VERSION 5.8 ;
BUSBITCHARS "[]" ;
DIVIDERCHAR "/" ;
UNITS
    DATABASE MICRONS 1000 ;
END UNITS

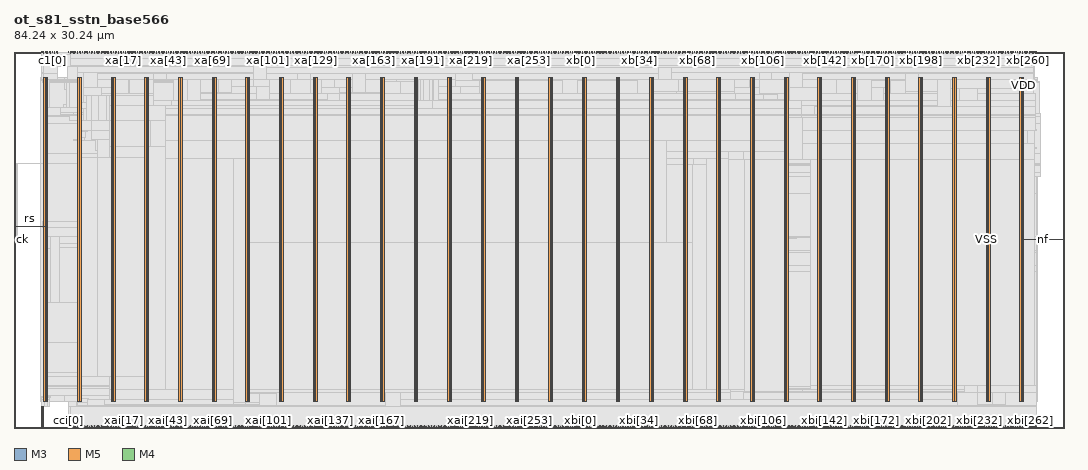
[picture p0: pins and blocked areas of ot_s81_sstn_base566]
MACRO ot_s81_sstn_base566
  FOREIGN ot_s81_sstn_base566 0 0 ;
  CLASS BLOCK ;
  SIZE 84.24 BY 30.24 ;
  PIN c0[0]
    DIRECTION INPUT ;
    USE SIGNAL ;
    PORT
      LAYER M3 ;
        RECT  2.808 30.096 2.826 30.24 ;
    END
  END c0[0]
  PIN c0[1]
    DIRECTION INPUT ;
    USE SIGNAL ;
    PORT
      LAYER M5 ;
        RECT  2.928 30.048 2.952 30.24 ;
    END
  END c0[1]
  PIN c1[0]
    DIRECTION INPUT ;
    USE SIGNAL ;
    PORT
      LAYER M3 ;
        RECT  3.096 30.096 3.114 30.24 ;
    END
  END c1[0]
  PIN c1[1]
    DIRECTION INPUT ;
    USE SIGNAL ;
    PORT
      LAYER M5 ;
        RECT  3.216 30.048 3.24 30.24 ;
    END
  END c1[1]
  PIN cc[0]
    DIRECTION OUTPUT ;
    USE SIGNAL ;
    PORT
      LAYER M3 ;
        RECT  4.392 30.096 4.41 30.24 ;
    END
  END cc[0]
  PIN cc[10]
    DIRECTION OUTPUT ;
    USE SIGNAL ;
    PORT
      LAYER M3 ;
        RECT  5.76 30.096 5.778 30.24 ;
    END
  END cc[10]
  PIN cc[11]
    DIRECTION OUTPUT ;
    USE SIGNAL ;
    PORT
      LAYER M5 ;
        RECT  5.904 30.048 5.928 30.24 ;
    END
  END cc[11]
  PIN cc[12]
    DIRECTION OUTPUT ;
    USE SIGNAL ;
    PORT
      LAYER M3 ;
        RECT  6.048 30.096 6.066 30.24 ;
    END
  END cc[12]
  PIN cc[13]
    DIRECTION OUTPUT ;
    USE SIGNAL ;
    PORT
      LAYER M5 ;
        RECT  6.192 30.048 6.216 30.24 ;
    END
  END cc[13]
  PIN cc[14]
    DIRECTION OUTPUT ;
    USE SIGNAL ;
    PORT
      LAYER M3 ;
        RECT  6.3 30.096 6.318 30.24 ;
    END
  END cc[14]
  PIN cc[1]
    DIRECTION OUTPUT ;
    USE SIGNAL ;
    PORT
      LAYER M5 ;
        RECT  4.512 30.048 4.536 30.24 ;
    END
  END cc[1]
  PIN cc[2]
    DIRECTION OUTPUT ;
    USE SIGNAL ;
    PORT
      LAYER M3 ;
        RECT  4.644 30.096 4.662 30.24 ;
    END
    PORT
      LAYER M3 ;
        RECT  4.608 30.108 4.734 30.173 ;
    END
  END cc[2]
  PIN cc[3]
    DIRECTION OUTPUT ;
    USE SIGNAL ;
    PORT
      LAYER M5 ;
        RECT  4.8 30.048 4.824 30.24 ;
    END
  END cc[3]
  PIN cc[4]
    DIRECTION OUTPUT ;
    USE SIGNAL ;
    PORT
      LAYER M3 ;
        RECT  4.932 30.096 4.95 30.24 ;
    END
  END cc[4]
  PIN cc[5]
    DIRECTION OUTPUT ;
    USE SIGNAL ;
    PORT
      LAYER M5 ;
        RECT  5.088 30.048 5.112 30.24 ;
    END
  END cc[5]
  PIN cc[6]
    DIRECTION OUTPUT ;
    USE SIGNAL ;
    PORT
      LAYER M3 ;
        RECT  5.22 30.096 5.238 30.24 ;
    END
  END cc[6]
  PIN cc[7]
    DIRECTION OUTPUT ;
    USE SIGNAL ;
    PORT
      LAYER M5 ;
        RECT  5.328 30.048 5.352 30.24 ;
    END
  END cc[7]
  PIN cc[8]
    DIRECTION OUTPUT ;
    USE SIGNAL ;
    PORT
      LAYER M3 ;
        RECT  5.472 30.096 5.49 30.24 ;
    END
  END cc[8]
  PIN cc[9]
    DIRECTION OUTPUT ;
    USE SIGNAL ;
    PORT
      LAYER M5 ;
        RECT  5.616 30.048 5.64 30.24 ;
    END
  END cc[9]
  PIN cci[0]
    DIRECTION INPUT ;
    USE SIGNAL ;
    PORT
      LAYER M3 ;
        RECT  4.392 0 4.41 0.144 ;
    END
  END cci[0]
  PIN cci[10]
    DIRECTION INPUT ;
    USE SIGNAL ;
    PORT
      LAYER M3 ;
        RECT  5.76 0 5.778 0.144 ;
    END
  END cci[10]
  PIN cci[11]
    DIRECTION INPUT ;
    USE SIGNAL ;
    PORT
      LAYER M5 ;
        RECT  5.904 0 5.928 0.192 ;
    END
  END cci[11]
  PIN cci[12]
    DIRECTION INPUT ;
    USE SIGNAL ;
    PORT
      LAYER M3 ;
        RECT  6.048 0 6.066 0.144 ;
    END
  END cci[12]
  PIN cci[13]
    DIRECTION INPUT ;
    USE SIGNAL ;
    PORT
      LAYER M5 ;
        RECT  6.192 0 6.216 0.192 ;
    END
  END cci[13]
  PIN cci[14]
    DIRECTION INPUT ;
    USE SIGNAL ;
    PORT
      LAYER M3 ;
        RECT  6.3 0 6.318 0.144 ;
    END
  END cci[14]
  PIN cci[1]
    DIRECTION INPUT ;
    USE SIGNAL ;
    PORT
      LAYER M5 ;
        RECT  4.512 0 4.536 0.192 ;
    END
  END cci[1]
  PIN cci[2]
    DIRECTION INPUT ;
    USE SIGNAL ;
    PORT
      LAYER M3 ;
        RECT  4.644 0 4.662 0.144 ;
    END
  END cci[2]
  PIN cci[3]
    DIRECTION INPUT ;
    USE SIGNAL ;
    PORT
      LAYER M5 ;
        RECT  4.8 0 4.824 0.192 ;
    END
  END cci[3]
  PIN cci[4]
    DIRECTION INPUT ;
    USE SIGNAL ;
    PORT
      LAYER M3 ;
        RECT  4.932 0 4.95 0.144 ;
    END
  END cci[4]
  PIN cci[5]
    DIRECTION INPUT ;
    USE SIGNAL ;
    PORT
      LAYER M5 ;
        RECT  5.088 0 5.112 0.192 ;
    END
  END cci[5]
  PIN cci[6]
    DIRECTION INPUT ;
    USE SIGNAL ;
    PORT
      LAYER M3 ;
        RECT  5.22 0 5.238 0.144 ;
    END
  END cci[6]
  PIN cci[7]
    DIRECTION INPUT ;
    USE SIGNAL ;
    PORT
      LAYER M5 ;
        RECT  5.328 0 5.352 0.192 ;
    END
  END cci[7]
  PIN cci[8]
    DIRECTION INPUT ;
    USE SIGNAL ;
    PORT
      LAYER M3 ;
        RECT  5.472 0 5.49 0.144 ;
    END
  END cci[8]
  PIN cci[9]
    DIRECTION INPUT ;
    USE SIGNAL ;
    PORT
      LAYER M5 ;
        RECT  5.616 0 5.64 0.192 ;
    END
  END cci[9]
  PIN ck
    DIRECTION INPUT ;
    USE SIGNAL ;
    PORT
      LAYER M4 ;
        RECT  0 15.12 0.192 15.144 ;
    END
    PORT
      LAYER M4 ;
        RECT  0.156 15.12 0.275 15.144 ;
    END
  END ck
  PIN e0[0]
    DIRECTION INPUT ;
    USE SIGNAL ;
    PORT
      LAYER M3 ;
        RECT  2.232 30.096 2.25 30.24 ;
    END
  END e0[0]
  PIN e0[1]
    DIRECTION INPUT ;
    USE SIGNAL ;
    PORT
      LAYER M5 ;
        RECT  2.352 30.048 2.376 30.24 ;
    END
  END e0[1]
  PIN e1[0]
    DIRECTION INPUT ;
    USE SIGNAL ;
    PORT
      LAYER M3 ;
        RECT  2.52 30.096 2.538 30.24 ;
    END
  END e1[0]
  PIN e1[1]
    DIRECTION INPUT ;
    USE SIGNAL ;
    PORT
      LAYER M5 ;
        RECT  2.64 30.048 2.664 30.24 ;
    END
  END e1[1]
  PIN nf
    DIRECTION INPUT ;
    USE SIGNAL ;
    PORT
      LAYER M4 ;
        RECT  84.048 15.12 84.24 15.144 ;
    END
    PORT
      LAYER M4 ;
        RECT  81.004 15.12 84.06 15.144 ;
    END
  END nf
  PIN rs
    DIRECTION INPUT ;
    USE SIGNAL ;
    PORT
      LAYER M4 ;
        RECT  0 16.128 0.192 16.152 ;
    END
    PORT
      LAYER M4 ;
        RECT  0.156 16.128 2.408 16.152 ;
    END
  END rs
  PIN si[0]
    DIRECTION INPUT ;
    USE SIGNAL ;
    PORT
      LAYER M3 ;
        RECT  3.384 30.096 3.402 30.24 ;
    END
  END si[0]
  PIN si[1]
    DIRECTION INPUT ;
    USE SIGNAL ;
    PORT
      LAYER M5 ;
        RECT  3.504 30.048 3.528 30.24 ;
    END
  END si[1]
  PIN so[0]
    DIRECTION OUTPUT ;
    USE SIGNAL ;
    PORT
      LAYER M3 ;
        RECT  2.232 0 2.25 0.144 ;
    END
    PORT
      LAYER M3 ;
        RECT  2.232 0.108 2.25 1.723 ;
    END
  END so[0]
  PIN so[1]
    DIRECTION OUTPUT ;
    USE SIGNAL ;
    PORT
      LAYER M5 ;
        RECT  2.352 0 2.376 0.192 ;
    END
    PORT
      LAYER M5 ;
        RECT  2.352 0.144 2.376 1.763 ;
    END
  END so[1]
  PIN xa[0]
    DIRECTION OUTPUT ;
    USE SIGNAL ;
    PORT
      LAYER M5 ;
        RECT  6.432 30.048 6.456 30.24 ;
    END
  END xa[0]
  PIN xa[100]
    DIRECTION OUTPUT ;
    USE SIGNAL ;
    PORT
      LAYER M5 ;
        RECT  20.256 30.048 20.28 30.24 ;
    END
  END xa[100]
  PIN xa[101]
    DIRECTION OUTPUT ;
    USE SIGNAL ;
    PORT
      LAYER M3 ;
        RECT  20.376 30.096 20.394 30.24 ;
    END
  END xa[101]
  PIN xa[102]
    DIRECTION OUTPUT ;
    USE SIGNAL ;
    PORT
      LAYER M5 ;
        RECT  20.496 30.048 20.52 30.24 ;
    END
  END xa[102]
  PIN xa[103]
    DIRECTION OUTPUT ;
    USE SIGNAL ;
    PORT
      LAYER M3 ;
        RECT  20.664 30.096 20.682 30.24 ;
    END
  END xa[103]
  PIN xa[104]
    DIRECTION OUTPUT ;
    USE SIGNAL ;
    PORT
      LAYER M5 ;
        RECT  20.784 30.048 20.808 30.24 ;
    END
  END xa[104]
  PIN xa[105]
    DIRECTION OUTPUT ;
    USE SIGNAL ;
    PORT
      LAYER M3 ;
        RECT  20.916 30.096 20.934 30.24 ;
    END
  END xa[105]
  PIN xa[106]
    DIRECTION OUTPUT ;
    USE SIGNAL ;
    PORT
      LAYER M5 ;
        RECT  21.072 30.048 21.096 30.24 ;
    END
  END xa[106]
  PIN xa[107]
    DIRECTION OUTPUT ;
    USE SIGNAL ;
    PORT
      LAYER M3 ;
        RECT  21.204 30.096 21.222 30.24 ;
    END
  END xa[107]
  PIN xa[108]
    DIRECTION OUTPUT ;
    USE SIGNAL ;
    PORT
      LAYER M5 ;
        RECT  21.312 30.048 21.336 30.24 ;
    END
  END xa[108]
  PIN xa[109]
    DIRECTION OUTPUT ;
    USE SIGNAL ;
    PORT
      LAYER M3 ;
        RECT  21.492 30.096 21.51 30.24 ;
    END
  END xa[109]
  PIN xa[10]
    DIRECTION OUTPUT ;
    USE SIGNAL ;
    PORT
      LAYER M5 ;
        RECT  7.824 30.048 7.848 30.24 ;
    END
  END xa[10]
  PIN xa[110]
    DIRECTION OUTPUT ;
    USE SIGNAL ;
    PORT
      LAYER M5 ;
        RECT  21.6 30.048 21.624 30.24 ;
    END
  END xa[110]
  PIN xa[111]
    DIRECTION OUTPUT ;
    USE SIGNAL ;
    PORT
      LAYER M3 ;
        RECT  21.744 30.096 21.762 30.24 ;
    END
  END xa[111]
  PIN xa[112]
    DIRECTION OUTPUT ;
    USE SIGNAL ;
    PORT
      LAYER M5 ;
        RECT  21.888 30.048 21.912 30.24 ;
    END
  END xa[112]
  PIN xa[113]
    DIRECTION OUTPUT ;
    USE SIGNAL ;
    PORT
      LAYER M3 ;
        RECT  22.032 30.096 22.05 30.24 ;
    END
  END xa[113]
  PIN xa[114]
    DIRECTION OUTPUT ;
    USE SIGNAL ;
    PORT
      LAYER M5 ;
        RECT  22.176 30.048 22.2 30.24 ;
    END
  END xa[114]
  PIN xa[115]
    DIRECTION OUTPUT ;
    USE SIGNAL ;
    PORT
      LAYER M3 ;
        RECT  22.32 30.096 22.338 30.24 ;
    END
  END xa[115]
  PIN xa[116]
    DIRECTION OUTPUT ;
    USE SIGNAL ;
    PORT
      LAYER M5 ;
        RECT  22.416 30.048 22.44 30.24 ;
    END
  END xa[116]
  PIN xa[117]
    DIRECTION OUTPUT ;
    USE SIGNAL ;
    PORT
      LAYER M3 ;
        RECT  22.572 30.096 22.59 30.24 ;
    END
  END xa[117]
  PIN xa[118]
    DIRECTION OUTPUT ;
    USE SIGNAL ;
    PORT
      LAYER M5 ;
        RECT  22.704 30.048 22.728 30.24 ;
    END
  END xa[118]
  PIN xa[119]
    DIRECTION OUTPUT ;
    USE SIGNAL ;
    PORT
      LAYER M3 ;
        RECT  22.86 30.096 22.878 30.24 ;
    END
  END xa[119]
  PIN xa[11]
    DIRECTION OUTPUT ;
    USE SIGNAL ;
    PORT
      LAYER M3 ;
        RECT  7.956 30.096 7.974 30.24 ;
    END
  END xa[11]
  PIN xa[120]
    DIRECTION OUTPUT ;
    USE SIGNAL ;
    PORT
      LAYER M5 ;
        RECT  22.992 30.048 23.016 30.24 ;
    END
  END xa[120]
  PIN xa[121]
    DIRECTION OUTPUT ;
    USE SIGNAL ;
    PORT
      LAYER M3 ;
        RECT  23.148 30.096 23.166 30.24 ;
    END
  END xa[121]
  PIN xa[122]
    DIRECTION OUTPUT ;
    USE SIGNAL ;
    PORT
      LAYER M5 ;
        RECT  23.28 30.048 23.304 30.24 ;
    END
  END xa[122]
  PIN xa[123]
    DIRECTION OUTPUT ;
    USE SIGNAL ;
    PORT
      LAYER M3 ;
        RECT  23.4 30.096 23.418 30.24 ;
    END
  END xa[123]
  PIN xa[124]
    DIRECTION OUTPUT ;
    USE SIGNAL ;
    PORT
      LAYER M5 ;
        RECT  23.52 30.048 23.544 30.24 ;
    END
  END xa[124]
  PIN xa[125]
    DIRECTION OUTPUT ;
    USE SIGNAL ;
    PORT
      LAYER M3 ;
        RECT  23.688 30.096 23.706 30.24 ;
    END
  END xa[125]
  PIN xa[126]
    DIRECTION OUTPUT ;
    USE SIGNAL ;
    PORT
      LAYER M5 ;
        RECT  23.808 30.048 23.832 30.24 ;
    END
  END xa[126]
  PIN xa[127]
    DIRECTION OUTPUT ;
    USE SIGNAL ;
    PORT
      LAYER M3 ;
        RECT  23.94 30.096 23.958 30.24 ;
    END
  END xa[127]
  PIN xa[128]
    DIRECTION OUTPUT ;
    USE SIGNAL ;
    PORT
      LAYER M5 ;
        RECT  24.096 30.048 24.12 30.24 ;
    END
  END xa[128]
  PIN xa[129]
    DIRECTION OUTPUT ;
    USE SIGNAL ;
    PORT
      LAYER M3 ;
        RECT  24.228 30.096 24.246 30.24 ;
    END
  END xa[129]
  PIN xa[12]
    DIRECTION OUTPUT ;
    USE SIGNAL ;
    PORT
      LAYER M5 ;
        RECT  8.112 30.048 8.136 30.24 ;
    END
  END xa[12]
  PIN xa[130]
    DIRECTION OUTPUT ;
    USE SIGNAL ;
    PORT
      LAYER M5 ;
        RECT  24.384 30.048 24.408 30.24 ;
    END
  END xa[130]
  PIN xa[131]
    DIRECTION OUTPUT ;
    USE SIGNAL ;
    PORT
      LAYER M3 ;
        RECT  24.516 30.096 24.534 30.24 ;
    END
  END xa[131]
  PIN xa[132]
    DIRECTION OUTPUT ;
    USE SIGNAL ;
    PORT
      LAYER M5 ;
        RECT  24.624 30.048 24.648 30.24 ;
    END
  END xa[132]
  PIN xa[133]
    DIRECTION OUTPUT ;
    USE SIGNAL ;
    PORT
      LAYER M3 ;
        RECT  24.768 30.096 24.786 30.24 ;
    END
  END xa[133]
  PIN xa[134]
    DIRECTION OUTPUT ;
    USE SIGNAL ;
    PORT
      LAYER M5 ;
        RECT  24.912 30.048 24.936 30.24 ;
    END
  END xa[134]
  PIN xa[135]
    DIRECTION OUTPUT ;
    USE SIGNAL ;
    PORT
      LAYER M3 ;
        RECT  25.056 30.096 25.074 30.24 ;
    END
  END xa[135]
  PIN xa[136]
    DIRECTION OUTPUT ;
    USE SIGNAL ;
    PORT
      LAYER M5 ;
        RECT  25.2 30.048 25.224 30.24 ;
    END
  END xa[136]
  PIN xa[137]
    DIRECTION OUTPUT ;
    USE SIGNAL ;
    PORT
      LAYER M3 ;
        RECT  25.344 30.096 25.362 30.24 ;
    END
  END xa[137]
  PIN xa[138]
    DIRECTION OUTPUT ;
    USE SIGNAL ;
    PORT
      LAYER M5 ;
        RECT  25.488 30.048 25.512 30.24 ;
    END
  END xa[138]
  PIN xa[139]
    DIRECTION OUTPUT ;
    USE SIGNAL ;
    PORT
      LAYER M3 ;
        RECT  25.596 30.096 25.614 30.24 ;
    END
  END xa[139]
  PIN xa[13]
    DIRECTION OUTPUT ;
    USE SIGNAL ;
    PORT
      LAYER M3 ;
        RECT  8.244 30.096 8.262 30.24 ;
    END
  END xa[13]
  PIN xa[140]
    DIRECTION OUTPUT ;
    USE SIGNAL ;
    PORT
      LAYER M5 ;
        RECT  25.728 30.048 25.752 30.24 ;
    END
  END xa[140]
  PIN xa[141]
    DIRECTION OUTPUT ;
    USE SIGNAL ;
    PORT
      LAYER M3 ;
        RECT  25.884 30.096 25.902 30.24 ;
    END
  END xa[141]
  PIN xa[142]
    DIRECTION OUTPUT ;
    USE SIGNAL ;
    PORT
      LAYER M5 ;
        RECT  26.016 30.048 26.04 30.24 ;
    END
  END xa[142]
  PIN xa[143]
    DIRECTION OUTPUT ;
    USE SIGNAL ;
    PORT
      LAYER M3 ;
        RECT  26.172 30.096 26.19 30.24 ;
    END
  END xa[143]
  PIN xa[144]
    DIRECTION OUTPUT ;
    USE SIGNAL ;
    PORT
      LAYER M5 ;
        RECT  26.304 30.048 26.328 30.24 ;
    END
  END xa[144]
  PIN xa[145]
    DIRECTION OUTPUT ;
    USE SIGNAL ;
    PORT
      LAYER M3 ;
        RECT  26.424 30.096 26.442 30.24 ;
    END
  END xa[145]
  PIN xa[146]
    DIRECTION OUTPUT ;
    USE SIGNAL ;
    PORT
      LAYER M5 ;
        RECT  26.592 30.048 26.616 30.24 ;
    END
  END xa[146]
  PIN xa[147]
    DIRECTION OUTPUT ;
    USE SIGNAL ;
    PORT
      LAYER M3 ;
        RECT  26.712 30.096 26.73 30.24 ;
    END
  END xa[147]
  PIN xa[148]
    DIRECTION OUTPUT ;
    USE SIGNAL ;
    PORT
      LAYER M5 ;
        RECT  26.832 30.048 26.856 30.24 ;
    END
  END xa[148]
  PIN xa[149]
    DIRECTION OUTPUT ;
    USE SIGNAL ;
    PORT
      LAYER M3 ;
        RECT  27 30.096 27.018 30.24 ;
    END
  END xa[149]
  PIN xa[14]
    DIRECTION OUTPUT ;
    USE SIGNAL ;
    PORT
      LAYER M5 ;
        RECT  8.352 30.048 8.376 30.24 ;
    END
  END xa[14]
  PIN xa[150]
    DIRECTION OUTPUT ;
    USE SIGNAL ;
    PORT
      LAYER M5 ;
        RECT  27.12 30.048 27.144 30.24 ;
    END
  END xa[150]
  PIN xa[151]
    DIRECTION OUTPUT ;
    USE SIGNAL ;
    PORT
      LAYER M3 ;
        RECT  27.252 30.096 27.27 30.24 ;
    END
  END xa[151]
  PIN xa[152]
    DIRECTION OUTPUT ;
    USE SIGNAL ;
    PORT
      LAYER M5 ;
        RECT  27.408 30.048 27.432 30.24 ;
    END
  END xa[152]
  PIN xa[153]
    DIRECTION OUTPUT ;
    USE SIGNAL ;
    PORT
      LAYER M3 ;
        RECT  27.54 30.096 27.558 30.24 ;
    END
  END xa[153]
  PIN xa[154]
    DIRECTION OUTPUT ;
    USE SIGNAL ;
    PORT
      LAYER M5 ;
        RECT  27.696 30.048 27.72 30.24 ;
    END
  END xa[154]
  PIN xa[155]
    DIRECTION OUTPUT ;
    USE SIGNAL ;
    PORT
      LAYER M3 ;
        RECT  27.828 30.096 27.846 30.24 ;
    END
  END xa[155]
  PIN xa[156]
    DIRECTION OUTPUT ;
    USE SIGNAL ;
    PORT
      LAYER M5 ;
        RECT  27.936 30.048 27.96 30.24 ;
    END
  END xa[156]
  PIN xa[157]
    DIRECTION OUTPUT ;
    USE SIGNAL ;
    PORT
      LAYER M3 ;
        RECT  28.08 30.096 28.098 30.24 ;
    END
  END xa[157]
  PIN xa[158]
    DIRECTION OUTPUT ;
    USE SIGNAL ;
    PORT
      LAYER M5 ;
        RECT  28.224 30.048 28.248 30.24 ;
    END
  END xa[158]
  PIN xa[159]
    DIRECTION OUTPUT ;
    USE SIGNAL ;
    PORT
      LAYER M3 ;
        RECT  28.368 30.096 28.386 30.24 ;
    END
  END xa[159]
  PIN xa[15]
    DIRECTION OUTPUT ;
    USE SIGNAL ;
    PORT
      LAYER M3 ;
        RECT  8.532 30.096 8.55 30.24 ;
    END
  END xa[15]
  PIN xa[160]
    DIRECTION OUTPUT ;
    USE SIGNAL ;
    PORT
      LAYER M5 ;
        RECT  28.512 30.048 28.536 30.24 ;
    END
  END xa[160]
  PIN xa[161]
    DIRECTION OUTPUT ;
    USE SIGNAL ;
    PORT
      LAYER M3 ;
        RECT  28.656 30.096 28.674 30.24 ;
    END
  END xa[161]
  PIN xa[162]
    DIRECTION OUTPUT ;
    USE SIGNAL ;
    PORT
      LAYER M5 ;
        RECT  28.8 30.048 28.824 30.24 ;
    END
  END xa[162]
  PIN xa[163]
    DIRECTION OUTPUT ;
    USE SIGNAL ;
    PORT
      LAYER M3 ;
        RECT  28.908 30.096 28.926 30.24 ;
    END
  END xa[163]
  PIN xa[164]
    DIRECTION OUTPUT ;
    USE SIGNAL ;
    PORT
      LAYER M5 ;
        RECT  29.04 30.048 29.064 30.24 ;
    END
  END xa[164]
  PIN xa[165]
    DIRECTION OUTPUT ;
    USE SIGNAL ;
    PORT
      LAYER M3 ;
        RECT  29.196 30.096 29.214 30.24 ;
    END
  END xa[165]
  PIN xa[166]
    DIRECTION OUTPUT ;
    USE SIGNAL ;
    PORT
      LAYER M5 ;
        RECT  29.328 30.048 29.352 30.24 ;
    END
  END xa[166]
  PIN xa[167]
    DIRECTION OUTPUT ;
    USE SIGNAL ;
    PORT
      LAYER M3 ;
        RECT  29.484 30.096 29.502 30.24 ;
    END
  END xa[167]
  PIN xa[168]
    DIRECTION OUTPUT ;
    USE SIGNAL ;
    PORT
      LAYER M5 ;
        RECT  29.616 30.048 29.64 30.24 ;
    END
  END xa[168]
  PIN xa[169]
    DIRECTION OUTPUT ;
    USE SIGNAL ;
    PORT
      LAYER M3 ;
        RECT  29.736 30.096 29.754 30.24 ;
    END
  END xa[169]
  PIN xa[16]
    DIRECTION OUTPUT ;
    USE SIGNAL ;
    PORT
      LAYER M5 ;
        RECT  8.64 30.048 8.664 30.24 ;
    END
  END xa[16]
  PIN xa[170]
    DIRECTION OUTPUT ;
    USE SIGNAL ;
    PORT
      LAYER M5 ;
        RECT  29.904 30.048 29.928 30.24 ;
    END
  END xa[170]
  PIN xa[171]
    DIRECTION OUTPUT ;
    USE SIGNAL ;
    PORT
      LAYER M3 ;
        RECT  30.024 30.096 30.042 30.24 ;
    END
  END xa[171]
  PIN xa[172]
    DIRECTION OUTPUT ;
    USE SIGNAL ;
    PORT
      LAYER M5 ;
        RECT  30.144 30.048 30.168 30.24 ;
    END
  END xa[172]
  PIN xa[173]
    DIRECTION OUTPUT ;
    USE SIGNAL ;
    PORT
      LAYER M3 ;
        RECT  30.312 30.096 30.33 30.24 ;
    END
  END xa[173]
  PIN xa[174]
    DIRECTION OUTPUT ;
    USE SIGNAL ;
    PORT
      LAYER M5 ;
        RECT  30.432 30.048 30.456 30.24 ;
    END
  END xa[174]
  PIN xa[175]
    DIRECTION OUTPUT ;
    USE SIGNAL ;
    PORT
      LAYER M3 ;
        RECT  30.564 30.096 30.582 30.24 ;
    END
  END xa[175]
  PIN xa[176]
    DIRECTION OUTPUT ;
    USE SIGNAL ;
    PORT
      LAYER M5 ;
        RECT  30.72 30.048 30.744 30.24 ;
    END
  END xa[176]
  PIN xa[177]
    DIRECTION OUTPUT ;
    USE SIGNAL ;
    PORT
      LAYER M3 ;
        RECT  30.852 30.096 30.87 30.24 ;
    END
  END xa[177]
  PIN xa[178]
    DIRECTION OUTPUT ;
    USE SIGNAL ;
    PORT
      LAYER M5 ;
        RECT  31.008 30.048 31.032 30.24 ;
    END
  END xa[178]
  PIN xa[179]
    DIRECTION OUTPUT ;
    USE SIGNAL ;
    PORT
      LAYER M3 ;
        RECT  31.14 30.096 31.158 30.24 ;
    END
  END xa[179]
  PIN xa[17]
    DIRECTION OUTPUT ;
    USE SIGNAL ;
    PORT
      LAYER M3 ;
        RECT  8.784 30.096 8.802 30.24 ;
    END
  END xa[17]
  PIN xa[180]
    DIRECTION OUTPUT ;
    USE SIGNAL ;
    PORT
      LAYER M5 ;
        RECT  31.248 30.048 31.272 30.24 ;
    END
  END xa[180]
  PIN xa[181]
    DIRECTION OUTPUT ;
    USE SIGNAL ;
    PORT
      LAYER M3 ;
        RECT  31.392 30.096 31.41 30.24 ;
    END
  END xa[181]
  PIN xa[182]
    DIRECTION OUTPUT ;
    USE SIGNAL ;
    PORT
      LAYER M5 ;
        RECT  31.536 30.048 31.56 30.24 ;
    END
  END xa[182]
  PIN xa[183]
    DIRECTION OUTPUT ;
    USE SIGNAL ;
    PORT
      LAYER M3 ;
        RECT  31.68 30.096 31.698 30.24 ;
    END
  END xa[183]
  PIN xa[184]
    DIRECTION OUTPUT ;
    USE SIGNAL ;
    PORT
      LAYER M5 ;
        RECT  31.824 30.048 31.848 30.24 ;
    END
  END xa[184]
  PIN xa[185]
    DIRECTION OUTPUT ;
    USE SIGNAL ;
    PORT
      LAYER M3 ;
        RECT  31.968 30.096 31.986 30.24 ;
    END
  END xa[185]
  PIN xa[186]
    DIRECTION OUTPUT ;
    USE SIGNAL ;
    PORT
      LAYER M5 ;
        RECT  32.112 30.048 32.136 30.24 ;
    END
  END xa[186]
  PIN xa[187]
    DIRECTION OUTPUT ;
    USE SIGNAL ;
    PORT
      LAYER M3 ;
        RECT  32.22 30.096 32.238 30.24 ;
    END
  END xa[187]
  PIN xa[188]
    DIRECTION OUTPUT ;
    USE SIGNAL ;
    PORT
      LAYER M5 ;
        RECT  32.352 30.048 32.376 30.24 ;
    END
  END xa[188]
  PIN xa[189]
    DIRECTION OUTPUT ;
    USE SIGNAL ;
    PORT
      LAYER M3 ;
        RECT  32.508 30.096 32.526 30.24 ;
    END
  END xa[189]
  PIN xa[18]
    DIRECTION OUTPUT ;
    USE SIGNAL ;
    PORT
      LAYER M5 ;
        RECT  8.928 30.048 8.952 30.24 ;
    END
  END xa[18]
  PIN xa[190]
    DIRECTION OUTPUT ;
    USE SIGNAL ;
    PORT
      LAYER M5 ;
        RECT  32.64 30.048 32.664 30.24 ;
    END
  END xa[190]
  PIN xa[191]
    DIRECTION OUTPUT ;
    USE SIGNAL ;
    PORT
      LAYER M3 ;
        RECT  32.796 30.096 32.814 30.24 ;
    END
  END xa[191]
  PIN xa[192]
    DIRECTION OUTPUT ;
    USE SIGNAL ;
    PORT
      LAYER M5 ;
        RECT  32.928 30.048 32.952 30.24 ;
    END
  END xa[192]
  PIN xa[193]
    DIRECTION OUTPUT ;
    USE SIGNAL ;
    PORT
      LAYER M3 ;
        RECT  33.048 30.096 33.066 30.24 ;
    END
  END xa[193]
  PIN xa[194]
    DIRECTION OUTPUT ;
    USE SIGNAL ;
    PORT
      LAYER M5 ;
        RECT  33.216 30.048 33.24 30.24 ;
    END
  END xa[194]
  PIN xa[195]
    DIRECTION OUTPUT ;
    USE SIGNAL ;
    PORT
      LAYER M3 ;
        RECT  33.336 30.096 33.354 30.24 ;
    END
  END xa[195]
  PIN xa[196]
    DIRECTION OUTPUT ;
    USE SIGNAL ;
    PORT
      LAYER M5 ;
        RECT  33.456 30.048 33.48 30.24 ;
    END
  END xa[196]
  PIN xa[197]
    DIRECTION OUTPUT ;
    USE SIGNAL ;
    PORT
      LAYER M3 ;
        RECT  33.624 30.096 33.642 30.24 ;
    END
  END xa[197]
  PIN xa[198]
    DIRECTION OUTPUT ;
    USE SIGNAL ;
    PORT
      LAYER M5 ;
        RECT  33.744 30.048 33.768 30.24 ;
    END
  END xa[198]
  PIN xa[199]
    DIRECTION OUTPUT ;
    USE SIGNAL ;
    PORT
      LAYER M3 ;
        RECT  33.876 30.096 33.894 30.24 ;
    END
  END xa[199]
  PIN xa[19]
    DIRECTION OUTPUT ;
    USE SIGNAL ;
    PORT
      LAYER M3 ;
        RECT  9.072 30.096 9.09 30.24 ;
    END
  END xa[19]
  PIN xa[1]
    DIRECTION OUTPUT ;
    USE SIGNAL ;
    PORT
      LAYER M3 ;
        RECT  6.588 30.096 6.606 30.24 ;
    END
  END xa[1]
  PIN xa[200]
    DIRECTION OUTPUT ;
    USE SIGNAL ;
    PORT
      LAYER M5 ;
        RECT  34.032 30.048 34.056 30.24 ;
    END
  END xa[200]
  PIN xa[201]
    DIRECTION OUTPUT ;
    USE SIGNAL ;
    PORT
      LAYER M3 ;
        RECT  34.164 30.096 34.182 30.24 ;
    END
  END xa[201]
  PIN xa[202]
    DIRECTION OUTPUT ;
    USE SIGNAL ;
    PORT
      LAYER M5 ;
        RECT  34.272 30.048 34.296 30.24 ;
    END
  END xa[202]
  PIN xa[203]
    DIRECTION OUTPUT ;
    USE SIGNAL ;
    PORT
      LAYER M3 ;
        RECT  34.452 30.096 34.47 30.24 ;
    END
  END xa[203]
  PIN xa[204]
    DIRECTION OUTPUT ;
    USE SIGNAL ;
    PORT
      LAYER M5 ;
        RECT  34.56 30.048 34.584 30.24 ;
    END
  END xa[204]
  PIN xa[205]
    DIRECTION OUTPUT ;
    USE SIGNAL ;
    PORT
      LAYER M3 ;
        RECT  34.704 30.096 34.722 30.24 ;
    END
  END xa[205]
  PIN xa[206]
    DIRECTION OUTPUT ;
    USE SIGNAL ;
    PORT
      LAYER M5 ;
        RECT  34.848 30.048 34.872 30.24 ;
    END
  END xa[206]
  PIN xa[207]
    DIRECTION OUTPUT ;
    USE SIGNAL ;
    PORT
      LAYER M3 ;
        RECT  34.992 30.096 35.01 30.24 ;
    END
  END xa[207]
  PIN xa[208]
    DIRECTION OUTPUT ;
    USE SIGNAL ;
    PORT
      LAYER M5 ;
        RECT  35.136 30.048 35.16 30.24 ;
    END
  END xa[208]
  PIN xa[209]
    DIRECTION OUTPUT ;
    USE SIGNAL ;
    PORT
      LAYER M3 ;
        RECT  35.28 30.096 35.298 30.24 ;
    END
  END xa[209]
  PIN xa[20]
    DIRECTION OUTPUT ;
    USE SIGNAL ;
    PORT
      LAYER M5 ;
        RECT  9.216 30.048 9.24 30.24 ;
    END
  END xa[20]
  PIN xa[210]
    DIRECTION OUTPUT ;
    USE SIGNAL ;
    PORT
      LAYER M5 ;
        RECT  35.376 30.048 35.4 30.24 ;
    END
  END xa[210]
  PIN xa[211]
    DIRECTION OUTPUT ;
    USE SIGNAL ;
    PORT
      LAYER M3 ;
        RECT  35.532 30.096 35.55 30.24 ;
    END
  END xa[211]
  PIN xa[212]
    DIRECTION OUTPUT ;
    USE SIGNAL ;
    PORT
      LAYER M5 ;
        RECT  35.664 30.048 35.688 30.24 ;
    END
  END xa[212]
  PIN xa[213]
    DIRECTION OUTPUT ;
    USE SIGNAL ;
    PORT
      LAYER M3 ;
        RECT  35.82 30.096 35.838 30.24 ;
    END
  END xa[213]
  PIN xa[214]
    DIRECTION OUTPUT ;
    USE SIGNAL ;
    PORT
      LAYER M5 ;
        RECT  35.952 30.048 35.976 30.24 ;
    END
  END xa[214]
  PIN xa[215]
    DIRECTION OUTPUT ;
    USE SIGNAL ;
    PORT
      LAYER M3 ;
        RECT  36.108 30.096 36.126 30.24 ;
    END
  END xa[215]
  PIN xa[216]
    DIRECTION OUTPUT ;
    USE SIGNAL ;
    PORT
      LAYER M5 ;
        RECT  36.24 30.048 36.264 30.24 ;
    END
  END xa[216]
  PIN xa[217]
    DIRECTION OUTPUT ;
    USE SIGNAL ;
    PORT
      LAYER M3 ;
        RECT  36.36 30.096 36.378 30.24 ;
    END
  END xa[217]
  PIN xa[218]
    DIRECTION OUTPUT ;
    USE SIGNAL ;
    PORT
      LAYER M5 ;
        RECT  36.48 30.048 36.504 30.24 ;
    END
  END xa[218]
  PIN xa[219]
    DIRECTION OUTPUT ;
    USE SIGNAL ;
    PORT
      LAYER M3 ;
        RECT  36.648 30.096 36.666 30.24 ;
    END
  END xa[219]
  PIN xa[21]
    DIRECTION OUTPUT ;
    USE SIGNAL ;
    PORT
      LAYER M3 ;
        RECT  9.36 30.096 9.378 30.24 ;
    END
  END xa[21]
  PIN xa[220]
    DIRECTION OUTPUT ;
    USE SIGNAL ;
    PORT
      LAYER M5 ;
        RECT  36.768 30.048 36.792 30.24 ;
    END
  END xa[220]
  PIN xa[221]
    DIRECTION OUTPUT ;
    USE SIGNAL ;
    PORT
      LAYER M3 ;
        RECT  36.9 30.096 36.918 30.24 ;
    END
  END xa[221]
  PIN xa[222]
    DIRECTION OUTPUT ;
    USE SIGNAL ;
    PORT
      LAYER M5 ;
        RECT  37.056 30.048 37.08 30.24 ;
    END
  END xa[222]
  PIN xa[223]
    DIRECTION OUTPUT ;
    USE SIGNAL ;
    PORT
      LAYER M3 ;
        RECT  37.188 30.096 37.206 30.24 ;
    END
  END xa[223]
  PIN xa[224]
    DIRECTION OUTPUT ;
    USE SIGNAL ;
    PORT
      LAYER M5 ;
        RECT  37.344 30.048 37.368 30.24 ;
    END
  END xa[224]
  PIN xa[225]
    DIRECTION OUTPUT ;
    USE SIGNAL ;
    PORT
      LAYER M3 ;
        RECT  37.476 30.096 37.494 30.24 ;
    END
  END xa[225]
  PIN xa[226]
    DIRECTION OUTPUT ;
    USE SIGNAL ;
    PORT
      LAYER M5 ;
        RECT  37.584 30.048 37.608 30.24 ;
    END
  END xa[226]
  PIN xa[227]
    DIRECTION OUTPUT ;
    USE SIGNAL ;
    PORT
      LAYER M3 ;
        RECT  37.728 30.096 37.746 30.24 ;
    END
  END xa[227]
  PIN xa[228]
    DIRECTION OUTPUT ;
    USE SIGNAL ;
    PORT
      LAYER M5 ;
        RECT  37.872 30.048 37.896 30.24 ;
    END
  END xa[228]
  PIN xa[229]
    DIRECTION OUTPUT ;
    USE SIGNAL ;
    PORT
      LAYER M3 ;
        RECT  38.016 30.096 38.034 30.24 ;
    END
  END xa[229]
  PIN xa[22]
    DIRECTION OUTPUT ;
    USE SIGNAL ;
    PORT
      LAYER M5 ;
        RECT  9.456 30.048 9.48 30.24 ;
    END
  END xa[22]
  PIN xa[230]
    DIRECTION OUTPUT ;
    USE SIGNAL ;
    PORT
      LAYER M5 ;
        RECT  38.16 30.048 38.184 30.24 ;
    END
  END xa[230]
  PIN xa[231]
    DIRECTION OUTPUT ;
    USE SIGNAL ;
    PORT
      LAYER M3 ;
        RECT  38.304 30.096 38.322 30.24 ;
    END
  END xa[231]
  PIN xa[232]
    DIRECTION OUTPUT ;
    USE SIGNAL ;
    PORT
      LAYER M5 ;
        RECT  38.448 30.048 38.472 30.24 ;
    END
  END xa[232]
  PIN xa[233]
    DIRECTION OUTPUT ;
    USE SIGNAL ;
    PORT
      LAYER M3 ;
        RECT  38.556 30.096 38.574 30.24 ;
    END
  END xa[233]
  PIN xa[234]
    DIRECTION OUTPUT ;
    USE SIGNAL ;
    PORT
      LAYER M5 ;
        RECT  38.688 30.048 38.712 30.24 ;
    END
  END xa[234]
  PIN xa[235]
    DIRECTION OUTPUT ;
    USE SIGNAL ;
    PORT
      LAYER M3 ;
        RECT  38.844 30.096 38.862 30.24 ;
    END
  END xa[235]
  PIN xa[236]
    DIRECTION OUTPUT ;
    USE SIGNAL ;
    PORT
      LAYER M5 ;
        RECT  38.976 30.048 39 30.24 ;
    END
  END xa[236]
  PIN xa[237]
    DIRECTION OUTPUT ;
    USE SIGNAL ;
    PORT
      LAYER M3 ;
        RECT  39.132 30.096 39.15 30.24 ;
    END
  END xa[237]
  PIN xa[238]
    DIRECTION OUTPUT ;
    USE SIGNAL ;
    PORT
      LAYER M5 ;
        RECT  39.264 30.048 39.288 30.24 ;
    END
  END xa[238]
  PIN xa[239]
    DIRECTION OUTPUT ;
    USE SIGNAL ;
    PORT
      LAYER M3 ;
        RECT  39.384 30.096 39.402 30.24 ;
    END
  END xa[239]
  PIN xa[23]
    DIRECTION OUTPUT ;
    USE SIGNAL ;
    PORT
      LAYER M3 ;
        RECT  9.612 30.096 9.63 30.24 ;
    END
  END xa[23]
  PIN xa[240]
    DIRECTION OUTPUT ;
    USE SIGNAL ;
    PORT
      LAYER M5 ;
        RECT  39.552 30.048 39.576 30.24 ;
    END
  END xa[240]
  PIN xa[241]
    DIRECTION OUTPUT ;
    USE SIGNAL ;
    PORT
      LAYER M3 ;
        RECT  39.672 30.096 39.69 30.24 ;
    END
  END xa[241]
  PIN xa[242]
    DIRECTION OUTPUT ;
    USE SIGNAL ;
    PORT
      LAYER M5 ;
        RECT  39.792 30.048 39.816 30.24 ;
    END
  END xa[242]
  PIN xa[243]
    DIRECTION OUTPUT ;
    USE SIGNAL ;
    PORT
      LAYER M3 ;
        RECT  39.96 30.096 39.978 30.24 ;
    END
  END xa[243]
  PIN xa[244]
    DIRECTION OUTPUT ;
    USE SIGNAL ;
    PORT
      LAYER M5 ;
        RECT  40.08 30.048 40.104 30.24 ;
    END
  END xa[244]
  PIN xa[245]
    DIRECTION OUTPUT ;
    USE SIGNAL ;
    PORT
      LAYER M3 ;
        RECT  40.212 30.096 40.23 30.24 ;
    END
  END xa[245]
  PIN xa[246]
    DIRECTION OUTPUT ;
    USE SIGNAL ;
    PORT
      LAYER M5 ;
        RECT  40.368 30.048 40.392 30.24 ;
    END
  END xa[246]
  PIN xa[247]
    DIRECTION OUTPUT ;
    USE SIGNAL ;
    PORT
      LAYER M3 ;
        RECT  40.5 30.096 40.518 30.24 ;
    END
  END xa[247]
  PIN xa[248]
    DIRECTION OUTPUT ;
    USE SIGNAL ;
    PORT
      LAYER M5 ;
        RECT  40.656 30.048 40.68 30.24 ;
    END
  END xa[248]
  PIN xa[249]
    DIRECTION OUTPUT ;
    USE SIGNAL ;
    PORT
      LAYER M3 ;
        RECT  40.788 30.096 40.806 30.24 ;
    END
  END xa[249]
  PIN xa[24]
    DIRECTION OUTPUT ;
    USE SIGNAL ;
    PORT
      LAYER M5 ;
        RECT  9.744 30.048 9.768 30.24 ;
    END
  END xa[24]
  PIN xa[250]
    DIRECTION OUTPUT ;
    USE SIGNAL ;
    PORT
      LAYER M5 ;
        RECT  40.896 30.048 40.92 30.24 ;
    END
  END xa[250]
  PIN xa[251]
    DIRECTION OUTPUT ;
    USE SIGNAL ;
    PORT
      LAYER M3 ;
        RECT  41.04 30.096 41.058 30.24 ;
    END
  END xa[251]
  PIN xa[252]
    DIRECTION OUTPUT ;
    USE SIGNAL ;
    PORT
      LAYER M5 ;
        RECT  41.184 30.048 41.208 30.24 ;
    END
  END xa[252]
  PIN xa[253]
    DIRECTION OUTPUT ;
    USE SIGNAL ;
    PORT
      LAYER M3 ;
        RECT  41.328 30.096 41.346 30.24 ;
    END
  END xa[253]
  PIN xa[254]
    DIRECTION OUTPUT ;
    USE SIGNAL ;
    PORT
      LAYER M5 ;
        RECT  41.472 30.048 41.496 30.24 ;
    END
  END xa[254]
  PIN xa[255]
    DIRECTION OUTPUT ;
    USE SIGNAL ;
    PORT
      LAYER M3 ;
        RECT  41.616 30.096 41.634 30.24 ;
    END
  END xa[255]
  PIN xa[256]
    DIRECTION OUTPUT ;
    USE SIGNAL ;
    PORT
      LAYER M5 ;
        RECT  41.76 30.048 41.784 30.24 ;
    END
  END xa[256]
  PIN xa[257]
    DIRECTION OUTPUT ;
    USE SIGNAL ;
    PORT
      LAYER M3 ;
        RECT  41.868 30.096 41.886 30.24 ;
    END
  END xa[257]
  PIN xa[258]
    DIRECTION OUTPUT ;
    USE SIGNAL ;
    PORT
      LAYER M5 ;
        RECT  42 30.048 42.024 30.24 ;
    END
  END xa[258]
  PIN xa[259]
    DIRECTION OUTPUT ;
    USE SIGNAL ;
    PORT
      LAYER M3 ;
        RECT  42.156 30.096 42.174 30.24 ;
    END
  END xa[259]
  PIN xa[25]
    DIRECTION OUTPUT ;
    USE SIGNAL ;
    PORT
      LAYER M3 ;
        RECT  9.9 30.096 9.918 30.24 ;
    END
  END xa[25]
  PIN xa[260]
    DIRECTION OUTPUT ;
    USE SIGNAL ;
    PORT
      LAYER M5 ;
        RECT  42.288 30.048 42.312 30.24 ;
    END
  END xa[260]
  PIN xa[261]
    DIRECTION OUTPUT ;
    USE SIGNAL ;
    PORT
      LAYER M3 ;
        RECT  42.444 30.096 42.462 30.24 ;
    END
  END xa[261]
  PIN xa[262]
    DIRECTION OUTPUT ;
    USE SIGNAL ;
    PORT
      LAYER M5 ;
        RECT  42.576 30.048 42.6 30.24 ;
    END
  END xa[262]
  PIN xa[263]
    DIRECTION OUTPUT ;
    USE SIGNAL ;
    PORT
      LAYER M3 ;
        RECT  42.696 30.096 42.714 30.24 ;
    END
  END xa[263]
  PIN xa[264]
    DIRECTION OUTPUT ;
    USE SIGNAL ;
    PORT
      LAYER M5 ;
        RECT  42.864 30.048 42.888 30.24 ;
    END
  END xa[264]
  PIN xa[265]
    DIRECTION OUTPUT ;
    USE SIGNAL ;
    PORT
      LAYER M3 ;
        RECT  42.984 30.096 43.002 30.24 ;
    END
  END xa[265]
  PIN xa[266]
    DIRECTION OUTPUT ;
    USE SIGNAL ;
    PORT
      LAYER M5 ;
        RECT  43.104 30.048 43.128 30.24 ;
    END
  END xa[266]
  PIN xa[267]
    DIRECTION OUTPUT ;
    USE SIGNAL ;
    PORT
      LAYER M3 ;
        RECT  43.272 30.096 43.29 30.24 ;
    END
  END xa[267]
  PIN xa[268]
    DIRECTION OUTPUT ;
    USE SIGNAL ;
    PORT
      LAYER M5 ;
        RECT  43.392 30.048 43.416 30.24 ;
    END
  END xa[268]
  PIN xa[269]
    DIRECTION OUTPUT ;
    USE SIGNAL ;
    PORT
      LAYER M3 ;
        RECT  43.524 30.096 43.542 30.24 ;
    END
  END xa[269]
  PIN xa[26]
    DIRECTION OUTPUT ;
    USE SIGNAL ;
    PORT
      LAYER M5 ;
        RECT  10.032 30.048 10.056 30.24 ;
    END
  END xa[26]
  PIN xa[270]
    DIRECTION OUTPUT ;
    USE SIGNAL ;
    PORT
      LAYER M5 ;
        RECT  43.68 30.048 43.704 30.24 ;
    END
  END xa[270]
  PIN xa[271]
    DIRECTION OUTPUT ;
    USE SIGNAL ;
    PORT
      LAYER M3 ;
        RECT  43.812 30.096 43.83 30.24 ;
    END
  END xa[271]
  PIN xa[272]
    DIRECTION OUTPUT ;
    USE SIGNAL ;
    PORT
      LAYER M5 ;
        RECT  43.968 30.048 43.992 30.24 ;
    END
  END xa[272]
  PIN xa[273]
    DIRECTION OUTPUT ;
    USE SIGNAL ;
    PORT
      LAYER M3 ;
        RECT  44.1 30.096 44.118 30.24 ;
    END
  END xa[273]
  PIN xa[274]
    DIRECTION OUTPUT ;
    USE SIGNAL ;
    PORT
      LAYER M5 ;
        RECT  44.208 30.048 44.232 30.24 ;
    END
  END xa[274]
  PIN xa[275]
    DIRECTION OUTPUT ;
    USE SIGNAL ;
    PORT
      LAYER M3 ;
        RECT  44.352 30.096 44.37 30.24 ;
    END
  END xa[275]
  PIN xa[276]
    DIRECTION OUTPUT ;
    USE SIGNAL ;
    PORT
      LAYER M5 ;
        RECT  44.496 30.048 44.52 30.24 ;
    END
  END xa[276]
  PIN xa[277]
    DIRECTION OUTPUT ;
    USE SIGNAL ;
    PORT
      LAYER M3 ;
        RECT  44.64 30.096 44.658 30.24 ;
    END
  END xa[277]
  PIN xa[278]
    DIRECTION OUTPUT ;
    USE SIGNAL ;
    PORT
      LAYER M5 ;
        RECT  44.784 30.048 44.808 30.24 ;
    END
  END xa[278]
  PIN xa[279]
    DIRECTION OUTPUT ;
    USE SIGNAL ;
    PORT
      LAYER M3 ;
        RECT  44.928 30.096 44.946 30.24 ;
    END
  END xa[279]
  PIN xa[27]
    DIRECTION OUTPUT ;
    USE SIGNAL ;
    PORT
      LAYER M3 ;
        RECT  10.188 30.096 10.206 30.24 ;
    END
  END xa[27]
  PIN xa[280]
    DIRECTION OUTPUT ;
    USE SIGNAL ;
    PORT
      LAYER M5 ;
        RECT  45.072 30.048 45.096 30.24 ;
    END
  END xa[280]
  PIN xa[281]
    DIRECTION OUTPUT ;
    USE SIGNAL ;
    PORT
      LAYER M3 ;
        RECT  45.18 30.096 45.198 30.24 ;
    END
  END xa[281]
  PIN xa[282]
    DIRECTION OUTPUT ;
    USE SIGNAL ;
    PORT
      LAYER M5 ;
        RECT  45.312 30.048 45.336 30.24 ;
    END
  END xa[282]
  PIN xa[28]
    DIRECTION OUTPUT ;
    USE SIGNAL ;
    PORT
      LAYER M5 ;
        RECT  10.32 30.048 10.344 30.24 ;
    END
  END xa[28]
  PIN xa[29]
    DIRECTION OUTPUT ;
    USE SIGNAL ;
    PORT
      LAYER M3 ;
        RECT  10.44 30.096 10.458 30.24 ;
    END
  END xa[29]
  PIN xa[2]
    DIRECTION OUTPUT ;
    USE SIGNAL ;
    PORT
      LAYER M5 ;
        RECT  6.72 30.048 6.744 30.24 ;
    END
  END xa[2]
  PIN xa[30]
    DIRECTION OUTPUT ;
    USE SIGNAL ;
    PORT
      LAYER M5 ;
        RECT  10.56 30.048 10.584 30.24 ;
    END
  END xa[30]
  PIN xa[31]
    DIRECTION OUTPUT ;
    USE SIGNAL ;
    PORT
      LAYER M3 ;
        RECT  10.728 30.096 10.746 30.24 ;
    END
  END xa[31]
  PIN xa[32]
    DIRECTION OUTPUT ;
    USE SIGNAL ;
    PORT
      LAYER M5 ;
        RECT  10.848 30.048 10.872 30.24 ;
    END
  END xa[32]
  PIN xa[33]
    DIRECTION OUTPUT ;
    USE SIGNAL ;
    PORT
      LAYER M3 ;
        RECT  10.98 30.096 10.998 30.24 ;
    END
  END xa[33]
  PIN xa[34]
    DIRECTION OUTPUT ;
    USE SIGNAL ;
    PORT
      LAYER M5 ;
        RECT  11.136 30.048 11.16 30.24 ;
    END
  END xa[34]
  PIN xa[35]
    DIRECTION OUTPUT ;
    USE SIGNAL ;
    PORT
      LAYER M3 ;
        RECT  11.268 30.096 11.286 30.24 ;
    END
  END xa[35]
  PIN xa[36]
    DIRECTION OUTPUT ;
    USE SIGNAL ;
    PORT
      LAYER M5 ;
        RECT  11.424 30.048 11.448 30.24 ;
    END
  END xa[36]
  PIN xa[37]
    DIRECTION OUTPUT ;
    USE SIGNAL ;
    PORT
      LAYER M3 ;
        RECT  11.556 30.096 11.574 30.24 ;
    END
  END xa[37]
  PIN xa[38]
    DIRECTION OUTPUT ;
    USE SIGNAL ;
    PORT
      LAYER M5 ;
        RECT  11.664 30.048 11.688 30.24 ;
    END
  END xa[38]
  PIN xa[39]
    DIRECTION OUTPUT ;
    USE SIGNAL ;
    PORT
      LAYER M3 ;
        RECT  11.808 30.096 11.826 30.24 ;
    END
  END xa[39]
  PIN xa[3]
    DIRECTION OUTPUT ;
    USE SIGNAL ;
    PORT
      LAYER M3 ;
        RECT  6.876 30.096 6.894 30.24 ;
    END
  END xa[3]
  PIN xa[40]
    DIRECTION OUTPUT ;
    USE SIGNAL ;
    PORT
      LAYER M5 ;
        RECT  11.952 30.048 11.976 30.24 ;
    END
  END xa[40]
  PIN xa[41]
    DIRECTION OUTPUT ;
    USE SIGNAL ;
    PORT
      LAYER M3 ;
        RECT  12.096 30.096 12.114 30.24 ;
    END
  END xa[41]
  PIN xa[42]
    DIRECTION OUTPUT ;
    USE SIGNAL ;
    PORT
      LAYER M5 ;
        RECT  12.24 30.048 12.264 30.24 ;
    END
  END xa[42]
  PIN xa[43]
    DIRECTION OUTPUT ;
    USE SIGNAL ;
    PORT
      LAYER M3 ;
        RECT  12.384 30.096 12.402 30.24 ;
    END
  END xa[43]
  PIN xa[44]
    DIRECTION OUTPUT ;
    USE SIGNAL ;
    PORT
      LAYER M5 ;
        RECT  12.528 30.048 12.552 30.24 ;
    END
  END xa[44]
  PIN xa[45]
    DIRECTION OUTPUT ;
    USE SIGNAL ;
    PORT
      LAYER M3 ;
        RECT  12.636 30.096 12.654 30.24 ;
    END
  END xa[45]
  PIN xa[46]
    DIRECTION OUTPUT ;
    USE SIGNAL ;
    PORT
      LAYER M5 ;
        RECT  12.768 30.048 12.792 30.24 ;
    END
  END xa[46]
  PIN xa[47]
    DIRECTION OUTPUT ;
    USE SIGNAL ;
    PORT
      LAYER M3 ;
        RECT  12.924 30.096 12.942 30.24 ;
    END
  END xa[47]
  PIN xa[48]
    DIRECTION OUTPUT ;
    USE SIGNAL ;
    PORT
      LAYER M5 ;
        RECT  13.056 30.048 13.08 30.24 ;
    END
  END xa[48]
  PIN xa[49]
    DIRECTION OUTPUT ;
    USE SIGNAL ;
    PORT
      LAYER M3 ;
        RECT  13.212 30.096 13.23 30.24 ;
    END
  END xa[49]
  PIN xa[4]
    DIRECTION OUTPUT ;
    USE SIGNAL ;
    PORT
      LAYER M5 ;
        RECT  7.008 30.048 7.032 30.24 ;
    END
  END xa[4]
  PIN xa[50]
    DIRECTION OUTPUT ;
    USE SIGNAL ;
    PORT
      LAYER M5 ;
        RECT  13.344 30.048 13.368 30.24 ;
    END
  END xa[50]
  PIN xa[51]
    DIRECTION OUTPUT ;
    USE SIGNAL ;
    PORT
      LAYER M3 ;
        RECT  13.464 30.096 13.482 30.24 ;
    END
  END xa[51]
  PIN xa[52]
    DIRECTION OUTPUT ;
    USE SIGNAL ;
    PORT
      LAYER M5 ;
        RECT  13.632 30.048 13.656 30.24 ;
    END
  END xa[52]
  PIN xa[53]
    DIRECTION OUTPUT ;
    USE SIGNAL ;
    PORT
      LAYER M3 ;
        RECT  13.752 30.096 13.77 30.24 ;
    END
  END xa[53]
  PIN xa[54]
    DIRECTION OUTPUT ;
    USE SIGNAL ;
    PORT
      LAYER M5 ;
        RECT  13.872 30.048 13.896 30.24 ;
    END
  END xa[54]
  PIN xa[55]
    DIRECTION OUTPUT ;
    USE SIGNAL ;
    PORT
      LAYER M3 ;
        RECT  14.04 30.096 14.058 30.24 ;
    END
  END xa[55]
  PIN xa[56]
    DIRECTION OUTPUT ;
    USE SIGNAL ;
    PORT
      LAYER M5 ;
        RECT  14.16 30.048 14.184 30.24 ;
    END
  END xa[56]
  PIN xa[57]
    DIRECTION OUTPUT ;
    USE SIGNAL ;
    PORT
      LAYER M3 ;
        RECT  14.292 30.096 14.31 30.24 ;
    END
  END xa[57]
  PIN xa[58]
    DIRECTION OUTPUT ;
    USE SIGNAL ;
    PORT
      LAYER M5 ;
        RECT  14.448 30.048 14.472 30.24 ;
    END
  END xa[58]
  PIN xa[59]
    DIRECTION OUTPUT ;
    USE SIGNAL ;
    PORT
      LAYER M3 ;
        RECT  14.58 30.096 14.598 30.24 ;
    END
  END xa[59]
  PIN xa[5]
    DIRECTION OUTPUT ;
    USE SIGNAL ;
    PORT
      LAYER M3 ;
        RECT  7.128 30.096 7.146 30.24 ;
    END
  END xa[5]
  PIN xa[60]
    DIRECTION OUTPUT ;
    USE SIGNAL ;
    PORT
      LAYER M5 ;
        RECT  14.736 30.048 14.76 30.24 ;
    END
  END xa[60]
  PIN xa[61]
    DIRECTION OUTPUT ;
    USE SIGNAL ;
    PORT
      LAYER M3 ;
        RECT  14.868 30.096 14.886 30.24 ;
    END
  END xa[61]
  PIN xa[62]
    DIRECTION OUTPUT ;
    USE SIGNAL ;
    PORT
      LAYER M5 ;
        RECT  14.976 30.048 15 30.24 ;
    END
  END xa[62]
  PIN xa[63]
    DIRECTION OUTPUT ;
    USE SIGNAL ;
    PORT
      LAYER M3 ;
        RECT  15.12 30.096 15.138 30.24 ;
    END
  END xa[63]
  PIN xa[64]
    DIRECTION OUTPUT ;
    USE SIGNAL ;
    PORT
      LAYER M5 ;
        RECT  15.264 30.048 15.288 30.24 ;
    END
  END xa[64]
  PIN xa[65]
    DIRECTION OUTPUT ;
    USE SIGNAL ;
    PORT
      LAYER M3 ;
        RECT  15.408 30.096 15.426 30.24 ;
    END
  END xa[65]
  PIN xa[66]
    DIRECTION OUTPUT ;
    USE SIGNAL ;
    PORT
      LAYER M5 ;
        RECT  15.552 30.048 15.576 30.24 ;
    END
  END xa[66]
  PIN xa[67]
    DIRECTION OUTPUT ;
    USE SIGNAL ;
    PORT
      LAYER M3 ;
        RECT  15.696 30.096 15.714 30.24 ;
    END
  END xa[67]
  PIN xa[68]
    DIRECTION OUTPUT ;
    USE SIGNAL ;
    PORT
      LAYER M5 ;
        RECT  15.84 30.048 15.864 30.24 ;
    END
  END xa[68]
  PIN xa[69]
    DIRECTION OUTPUT ;
    USE SIGNAL ;
    PORT
      LAYER M3 ;
        RECT  15.948 30.096 15.966 30.24 ;
    END
  END xa[69]
  PIN xa[6]
    DIRECTION OUTPUT ;
    USE SIGNAL ;
    PORT
      LAYER M5 ;
        RECT  7.296 30.048 7.32 30.24 ;
    END
  END xa[6]
  PIN xa[70]
    DIRECTION OUTPUT ;
    USE SIGNAL ;
    PORT
      LAYER M5 ;
        RECT  16.08 30.048 16.104 30.24 ;
    END
  END xa[70]
  PIN xa[71]
    DIRECTION OUTPUT ;
    USE SIGNAL ;
    PORT
      LAYER M3 ;
        RECT  16.236 30.096 16.254 30.24 ;
    END
  END xa[71]
  PIN xa[72]
    DIRECTION OUTPUT ;
    USE SIGNAL ;
    PORT
      LAYER M5 ;
        RECT  16.368 30.048 16.392 30.24 ;
    END
  END xa[72]
  PIN xa[73]
    DIRECTION OUTPUT ;
    USE SIGNAL ;
    PORT
      LAYER M3 ;
        RECT  16.524 30.096 16.542 30.24 ;
    END
  END xa[73]
  PIN xa[74]
    DIRECTION OUTPUT ;
    USE SIGNAL ;
    PORT
      LAYER M5 ;
        RECT  16.656 30.048 16.68 30.24 ;
    END
  END xa[74]
  PIN xa[75]
    DIRECTION OUTPUT ;
    USE SIGNAL ;
    PORT
      LAYER M3 ;
        RECT  16.776 30.096 16.794 30.24 ;
    END
  END xa[75]
  PIN xa[76]
    DIRECTION OUTPUT ;
    USE SIGNAL ;
    PORT
      LAYER M5 ;
        RECT  16.944 30.048 16.968 30.24 ;
    END
  END xa[76]
  PIN xa[77]
    DIRECTION OUTPUT ;
    USE SIGNAL ;
    PORT
      LAYER M3 ;
        RECT  17.064 30.096 17.082 30.24 ;
    END
  END xa[77]
  PIN xa[78]
    DIRECTION OUTPUT ;
    USE SIGNAL ;
    PORT
      LAYER M5 ;
        RECT  17.184 30.048 17.208 30.24 ;
    END
  END xa[78]
  PIN xa[79]
    DIRECTION OUTPUT ;
    USE SIGNAL ;
    PORT
      LAYER M3 ;
        RECT  17.352 30.096 17.37 30.24 ;
    END
  END xa[79]
  PIN xa[7]
    DIRECTION OUTPUT ;
    USE SIGNAL ;
    PORT
      LAYER M3 ;
        RECT  7.416 30.096 7.434 30.24 ;
    END
  END xa[7]
  PIN xa[80]
    DIRECTION OUTPUT ;
    USE SIGNAL ;
    PORT
      LAYER M5 ;
        RECT  17.472 30.048 17.496 30.24 ;
    END
  END xa[80]
  PIN xa[81]
    DIRECTION OUTPUT ;
    USE SIGNAL ;
    PORT
      LAYER M3 ;
        RECT  17.604 30.096 17.622 30.24 ;
    END
  END xa[81]
  PIN xa[82]
    DIRECTION OUTPUT ;
    USE SIGNAL ;
    PORT
      LAYER M5 ;
        RECT  17.76 30.048 17.784 30.24 ;
    END
  END xa[82]
  PIN xa[83]
    DIRECTION OUTPUT ;
    USE SIGNAL ;
    PORT
      LAYER M3 ;
        RECT  17.892 30.096 17.91 30.24 ;
    END
  END xa[83]
  PIN xa[84]
    DIRECTION OUTPUT ;
    USE SIGNAL ;
    PORT
      LAYER M5 ;
        RECT  18.048 30.048 18.072 30.24 ;
    END
  END xa[84]
  PIN xa[85]
    DIRECTION OUTPUT ;
    USE SIGNAL ;
    PORT
      LAYER M3 ;
        RECT  18.18 30.096 18.198 30.24 ;
    END
  END xa[85]
  PIN xa[86]
    DIRECTION OUTPUT ;
    USE SIGNAL ;
    PORT
      LAYER M5 ;
        RECT  18.288 30.048 18.312 30.24 ;
    END
  END xa[86]
  PIN xa[87]
    DIRECTION OUTPUT ;
    USE SIGNAL ;
    PORT
      LAYER M3 ;
        RECT  18.432 30.096 18.45 30.24 ;
    END
  END xa[87]
  PIN xa[88]
    DIRECTION OUTPUT ;
    USE SIGNAL ;
    PORT
      LAYER M5 ;
        RECT  18.576 30.048 18.6 30.24 ;
    END
  END xa[88]
  PIN xa[89]
    DIRECTION OUTPUT ;
    USE SIGNAL ;
    PORT
      LAYER M3 ;
        RECT  18.72 30.096 18.738 30.24 ;
    END
  END xa[89]
  PIN xa[8]
    DIRECTION OUTPUT ;
    USE SIGNAL ;
    PORT
      LAYER M5 ;
        RECT  7.536 30.048 7.56 30.24 ;
    END
  END xa[8]
  PIN xa[90]
    DIRECTION OUTPUT ;
    USE SIGNAL ;
    PORT
      LAYER M5 ;
        RECT  18.864 30.048 18.888 30.24 ;
    END
  END xa[90]
  PIN xa[91]
    DIRECTION OUTPUT ;
    USE SIGNAL ;
    PORT
      LAYER M3 ;
        RECT  19.008 30.096 19.026 30.24 ;
    END
  END xa[91]
  PIN xa[92]
    DIRECTION OUTPUT ;
    USE SIGNAL ;
    PORT
      LAYER M5 ;
        RECT  19.152 30.048 19.176 30.24 ;
    END
  END xa[92]
  PIN xa[93]
    DIRECTION OUTPUT ;
    USE SIGNAL ;
    PORT
      LAYER M3 ;
        RECT  19.26 30.096 19.278 30.24 ;
    END
  END xa[93]
  PIN xa[94]
    DIRECTION OUTPUT ;
    USE SIGNAL ;
    PORT
      LAYER M5 ;
        RECT  19.392 30.048 19.416 30.24 ;
    END
  END xa[94]
  PIN xa[95]
    DIRECTION OUTPUT ;
    USE SIGNAL ;
    PORT
      LAYER M3 ;
        RECT  19.548 30.096 19.566 30.24 ;
    END
  END xa[95]
  PIN xa[96]
    DIRECTION OUTPUT ;
    USE SIGNAL ;
    PORT
      LAYER M5 ;
        RECT  19.68 30.048 19.704 30.24 ;
    END
  END xa[96]
  PIN xa[97]
    DIRECTION OUTPUT ;
    USE SIGNAL ;
    PORT
      LAYER M3 ;
        RECT  19.836 30.096 19.854 30.24 ;
    END
  END xa[97]
  PIN xa[98]
    DIRECTION OUTPUT ;
    USE SIGNAL ;
    PORT
      LAYER M5 ;
        RECT  19.968 30.048 19.992 30.24 ;
    END
  END xa[98]
  PIN xa[99]
    DIRECTION OUTPUT ;
    USE SIGNAL ;
    PORT
      LAYER M3 ;
        RECT  20.088 30.096 20.106 30.24 ;
    END
  END xa[99]
  PIN xa[9]
    DIRECTION OUTPUT ;
    USE SIGNAL ;
    PORT
      LAYER M3 ;
        RECT  7.704 30.096 7.722 30.24 ;
    END
  END xa[9]
  PIN xai[0]
    DIRECTION INPUT ;
    USE SIGNAL ;
    PORT
      LAYER M5 ;
        RECT  6.432 0 6.456 0.192 ;
    END
  END xai[0]
  PIN xai[100]
    DIRECTION INPUT ;
    USE SIGNAL ;
    PORT
      LAYER M5 ;
        RECT  20.256 0 20.28 0.192 ;
    END
  END xai[100]
  PIN xai[101]
    DIRECTION INPUT ;
    USE SIGNAL ;
    PORT
      LAYER M3 ;
        RECT  20.376 0 20.394 0.144 ;
    END
  END xai[101]
  PIN xai[102]
    DIRECTION INPUT ;
    USE SIGNAL ;
    PORT
      LAYER M5 ;
        RECT  20.496 0 20.52 0.192 ;
    END
  END xai[102]
  PIN xai[103]
    DIRECTION INPUT ;
    USE SIGNAL ;
    PORT
      LAYER M3 ;
        RECT  20.664 0 20.682 0.144 ;
    END
  END xai[103]
  PIN xai[104]
    DIRECTION INPUT ;
    USE SIGNAL ;
    PORT
      LAYER M5 ;
        RECT  20.784 0 20.808 0.192 ;
    END
  END xai[104]
  PIN xai[105]
    DIRECTION INPUT ;
    USE SIGNAL ;
    PORT
      LAYER M3 ;
        RECT  20.916 0 20.934 0.144 ;
    END
  END xai[105]
  PIN xai[106]
    DIRECTION INPUT ;
    USE SIGNAL ;
    PORT
      LAYER M5 ;
        RECT  21.072 0 21.096 0.192 ;
    END
  END xai[106]
  PIN xai[107]
    DIRECTION INPUT ;
    USE SIGNAL ;
    PORT
      LAYER M3 ;
        RECT  21.204 0 21.222 0.144 ;
    END
  END xai[107]
  PIN xai[108]
    DIRECTION INPUT ;
    USE SIGNAL ;
    PORT
      LAYER M5 ;
        RECT  21.312 0 21.336 0.192 ;
    END
  END xai[108]
  PIN xai[109]
    DIRECTION INPUT ;
    USE SIGNAL ;
    PORT
      LAYER M3 ;
        RECT  21.492 0 21.51 0.144 ;
    END
  END xai[109]
  PIN xai[10]
    DIRECTION INPUT ;
    USE SIGNAL ;
    PORT
      LAYER M5 ;
        RECT  7.824 0 7.848 0.192 ;
    END
  END xai[10]
  PIN xai[110]
    DIRECTION INPUT ;
    USE SIGNAL ;
    PORT
      LAYER M5 ;
        RECT  21.6 0 21.624 0.192 ;
    END
  END xai[110]
  PIN xai[111]
    DIRECTION INPUT ;
    USE SIGNAL ;
    PORT
      LAYER M3 ;
        RECT  21.744 0 21.762 0.144 ;
    END
  END xai[111]
  PIN xai[112]
    DIRECTION INPUT ;
    USE SIGNAL ;
    PORT
      LAYER M5 ;
        RECT  21.888 0 21.912 0.192 ;
    END
  END xai[112]
  PIN xai[113]
    DIRECTION INPUT ;
    USE SIGNAL ;
    PORT
      LAYER M3 ;
        RECT  22.032 0 22.05 0.144 ;
    END
  END xai[113]
  PIN xai[114]
    DIRECTION INPUT ;
    USE SIGNAL ;
    PORT
      LAYER M5 ;
        RECT  22.176 0 22.2 0.192 ;
    END
  END xai[114]
  PIN xai[115]
    DIRECTION INPUT ;
    USE SIGNAL ;
    PORT
      LAYER M3 ;
        RECT  22.32 0 22.338 0.144 ;
    END
  END xai[115]
  PIN xai[116]
    DIRECTION INPUT ;
    USE SIGNAL ;
    PORT
      LAYER M5 ;
        RECT  22.416 0 22.44 0.192 ;
    END
  END xai[116]
  PIN xai[117]
    DIRECTION INPUT ;
    USE SIGNAL ;
    PORT
      LAYER M3 ;
        RECT  22.572 0 22.59 0.144 ;
    END
  END xai[117]
  PIN xai[118]
    DIRECTION INPUT ;
    USE SIGNAL ;
    PORT
      LAYER M5 ;
        RECT  22.704 0 22.728 0.192 ;
    END
  END xai[118]
  PIN xai[119]
    DIRECTION INPUT ;
    USE SIGNAL ;
    PORT
      LAYER M3 ;
        RECT  22.86 0 22.878 0.144 ;
    END
  END xai[119]
  PIN xai[11]
    DIRECTION INPUT ;
    USE SIGNAL ;
    PORT
      LAYER M3 ;
        RECT  7.956 0 7.974 0.144 ;
    END
  END xai[11]
  PIN xai[120]
    DIRECTION INPUT ;
    USE SIGNAL ;
    PORT
      LAYER M5 ;
        RECT  22.992 0 23.016 0.192 ;
    END
  END xai[120]
  PIN xai[121]
    DIRECTION INPUT ;
    USE SIGNAL ;
    PORT
      LAYER M3 ;
        RECT  23.148 0 23.166 0.144 ;
    END
  END xai[121]
  PIN xai[122]
    DIRECTION INPUT ;
    USE SIGNAL ;
    PORT
      LAYER M5 ;
        RECT  23.28 0 23.304 0.192 ;
    END
  END xai[122]
  PIN xai[123]
    DIRECTION INPUT ;
    USE SIGNAL ;
    PORT
      LAYER M3 ;
        RECT  23.4 0 23.418 0.144 ;
    END
  END xai[123]
  PIN xai[124]
    DIRECTION INPUT ;
    USE SIGNAL ;
    PORT
      LAYER M5 ;
        RECT  23.52 0 23.544 0.192 ;
    END
  END xai[124]
  PIN xai[125]
    DIRECTION INPUT ;
    USE SIGNAL ;
    PORT
      LAYER M3 ;
        RECT  23.688 0 23.706 0.144 ;
    END
  END xai[125]
  PIN xai[126]
    DIRECTION INPUT ;
    USE SIGNAL ;
    PORT
      LAYER M5 ;
        RECT  23.808 0 23.832 0.192 ;
    END
  END xai[126]
  PIN xai[127]
    DIRECTION INPUT ;
    USE SIGNAL ;
    PORT
      LAYER M3 ;
        RECT  23.94 0 23.958 0.144 ;
    END
  END xai[127]
  PIN xai[128]
    DIRECTION INPUT ;
    USE SIGNAL ;
    PORT
      LAYER M5 ;
        RECT  24.096 0 24.12 0.192 ;
    END
  END xai[128]
  PIN xai[129]
    DIRECTION INPUT ;
    USE SIGNAL ;
    PORT
      LAYER M3 ;
        RECT  24.228 0 24.246 0.144 ;
    END
  END xai[129]
  PIN xai[12]
    DIRECTION INPUT ;
    USE SIGNAL ;
    PORT
      LAYER M5 ;
        RECT  8.112 0 8.136 0.192 ;
    END
  END xai[12]
  PIN xai[130]
    DIRECTION INPUT ;
    USE SIGNAL ;
    PORT
      LAYER M5 ;
        RECT  24.384 0 24.408 0.192 ;
    END
  END xai[130]
  PIN xai[131]
    DIRECTION INPUT ;
    USE SIGNAL ;
    PORT
      LAYER M3 ;
        RECT  24.516 0 24.534 0.144 ;
    END
  END xai[131]
  PIN xai[132]
    DIRECTION INPUT ;
    USE SIGNAL ;
    PORT
      LAYER M5 ;
        RECT  24.624 0 24.648 0.192 ;
    END
  END xai[132]
  PIN xai[133]
    DIRECTION INPUT ;
    USE SIGNAL ;
    PORT
      LAYER M3 ;
        RECT  24.768 0 24.786 0.144 ;
    END
  END xai[133]
  PIN xai[134]
    DIRECTION INPUT ;
    USE SIGNAL ;
    PORT
      LAYER M5 ;
        RECT  24.912 0 24.936 0.192 ;
    END
  END xai[134]
  PIN xai[135]
    DIRECTION INPUT ;
    USE SIGNAL ;
    PORT
      LAYER M3 ;
        RECT  25.056 0 25.074 0.144 ;
    END
  END xai[135]
  PIN xai[136]
    DIRECTION INPUT ;
    USE SIGNAL ;
    PORT
      LAYER M5 ;
        RECT  25.2 0 25.224 0.192 ;
    END
  END xai[136]
  PIN xai[137]
    DIRECTION INPUT ;
    USE SIGNAL ;
    PORT
      LAYER M3 ;
        RECT  25.344 0 25.362 0.144 ;
    END
  END xai[137]
  PIN xai[138]
    DIRECTION INPUT ;
    USE SIGNAL ;
    PORT
      LAYER M5 ;
        RECT  25.488 0 25.512 0.192 ;
    END
  END xai[138]
  PIN xai[139]
    DIRECTION INPUT ;
    USE SIGNAL ;
    PORT
      LAYER M3 ;
        RECT  25.596 0 25.614 0.144 ;
    END
  END xai[139]
  PIN xai[13]
    DIRECTION INPUT ;
    USE SIGNAL ;
    PORT
      LAYER M3 ;
        RECT  8.244 0 8.262 0.144 ;
    END
  END xai[13]
  PIN xai[140]
    DIRECTION INPUT ;
    USE SIGNAL ;
    PORT
      LAYER M5 ;
        RECT  25.728 0 25.752 0.192 ;
    END
  END xai[140]
  PIN xai[141]
    DIRECTION INPUT ;
    USE SIGNAL ;
    PORT
      LAYER M3 ;
        RECT  25.884 0 25.902 0.144 ;
    END
  END xai[141]
  PIN xai[142]
    DIRECTION INPUT ;
    USE SIGNAL ;
    PORT
      LAYER M5 ;
        RECT  26.016 0 26.04 0.192 ;
    END
  END xai[142]
  PIN xai[143]
    DIRECTION INPUT ;
    USE SIGNAL ;
    PORT
      LAYER M3 ;
        RECT  26.172 0 26.19 0.144 ;
    END
  END xai[143]
  PIN xai[144]
    DIRECTION INPUT ;
    USE SIGNAL ;
    PORT
      LAYER M5 ;
        RECT  26.304 0 26.328 0.192 ;
    END
  END xai[144]
  PIN xai[145]
    DIRECTION INPUT ;
    USE SIGNAL ;
    PORT
      LAYER M3 ;
        RECT  26.424 0 26.442 0.144 ;
    END
  END xai[145]
  PIN xai[146]
    DIRECTION INPUT ;
    USE SIGNAL ;
    PORT
      LAYER M5 ;
        RECT  26.592 0 26.616 0.192 ;
    END
  END xai[146]
  PIN xai[147]
    DIRECTION INPUT ;
    USE SIGNAL ;
    PORT
      LAYER M3 ;
        RECT  26.712 0 26.73 0.144 ;
    END
  END xai[147]
  PIN xai[148]
    DIRECTION INPUT ;
    USE SIGNAL ;
    PORT
      LAYER M5 ;
        RECT  26.832 0 26.856 0.192 ;
    END
  END xai[148]
  PIN xai[149]
    DIRECTION INPUT ;
    USE SIGNAL ;
    PORT
      LAYER M3 ;
        RECT  27 0 27.018 0.144 ;
    END
  END xai[149]
  PIN xai[14]
    DIRECTION INPUT ;
    USE SIGNAL ;
    PORT
      LAYER M5 ;
        RECT  8.352 0 8.376 0.192 ;
    END
  END xai[14]
  PIN xai[150]
    DIRECTION INPUT ;
    USE SIGNAL ;
    PORT
      LAYER M5 ;
        RECT  27.12 0 27.144 0.192 ;
    END
  END xai[150]
  PIN xai[151]
    DIRECTION INPUT ;
    USE SIGNAL ;
    PORT
      LAYER M3 ;
        RECT  27.252 0 27.27 0.144 ;
    END
  END xai[151]
  PIN xai[152]
    DIRECTION INPUT ;
    USE SIGNAL ;
    PORT
      LAYER M5 ;
        RECT  27.408 0 27.432 0.192 ;
    END
  END xai[152]
  PIN xai[153]
    DIRECTION INPUT ;
    USE SIGNAL ;
    PORT
      LAYER M3 ;
        RECT  27.54 0 27.558 0.144 ;
    END
  END xai[153]
  PIN xai[154]
    DIRECTION INPUT ;
    USE SIGNAL ;
    PORT
      LAYER M5 ;
        RECT  27.696 0 27.72 0.192 ;
    END
  END xai[154]
  PIN xai[155]
    DIRECTION INPUT ;
    USE SIGNAL ;
    PORT
      LAYER M3 ;
        RECT  27.828 0 27.846 0.144 ;
    END
  END xai[155]
  PIN xai[156]
    DIRECTION INPUT ;
    USE SIGNAL ;
    PORT
      LAYER M5 ;
        RECT  27.936 0 27.96 0.192 ;
    END
  END xai[156]
  PIN xai[157]
    DIRECTION INPUT ;
    USE SIGNAL ;
    PORT
      LAYER M3 ;
        RECT  28.08 0 28.098 0.144 ;
    END
  END xai[157]
  PIN xai[158]
    DIRECTION INPUT ;
    USE SIGNAL ;
    PORT
      LAYER M5 ;
        RECT  28.224 0 28.248 0.192 ;
    END
  END xai[158]
  PIN xai[159]
    DIRECTION INPUT ;
    USE SIGNAL ;
    PORT
      LAYER M3 ;
        RECT  28.368 0 28.386 0.144 ;
    END
  END xai[159]
  PIN xai[15]
    DIRECTION INPUT ;
    USE SIGNAL ;
    PORT
      LAYER M3 ;
        RECT  8.532 0 8.55 0.144 ;
    END
  END xai[15]
  PIN xai[160]
    DIRECTION INPUT ;
    USE SIGNAL ;
    PORT
      LAYER M5 ;
        RECT  28.512 0 28.536 0.192 ;
    END
  END xai[160]
  PIN xai[161]
    DIRECTION INPUT ;
    USE SIGNAL ;
    PORT
      LAYER M3 ;
        RECT  28.656 0 28.674 0.144 ;
    END
  END xai[161]
  PIN xai[162]
    DIRECTION INPUT ;
    USE SIGNAL ;
    PORT
      LAYER M5 ;
        RECT  28.8 0 28.824 0.192 ;
    END
  END xai[162]
  PIN xai[163]
    DIRECTION INPUT ;
    USE SIGNAL ;
    PORT
      LAYER M3 ;
        RECT  28.908 0 28.926 0.144 ;
    END
  END xai[163]
  PIN xai[164]
    DIRECTION INPUT ;
    USE SIGNAL ;
    PORT
      LAYER M5 ;
        RECT  29.04 0 29.064 0.192 ;
    END
  END xai[164]
  PIN xai[165]
    DIRECTION INPUT ;
    USE SIGNAL ;
    PORT
      LAYER M3 ;
        RECT  29.196 0 29.214 0.144 ;
    END
  END xai[165]
  PIN xai[166]
    DIRECTION INPUT ;
    USE SIGNAL ;
    PORT
      LAYER M5 ;
        RECT  29.328 0 29.352 0.192 ;
    END
  END xai[166]
  PIN xai[167]
    DIRECTION INPUT ;
    USE SIGNAL ;
    PORT
      LAYER M3 ;
        RECT  29.484 0 29.502 0.144 ;
    END
  END xai[167]
  PIN xai[168]
    DIRECTION INPUT ;
    USE SIGNAL ;
    PORT
      LAYER M5 ;
        RECT  29.616 0 29.64 0.192 ;
    END
  END xai[168]
  PIN xai[169]
    DIRECTION INPUT ;
    USE SIGNAL ;
    PORT
      LAYER M3 ;
        RECT  29.736 0 29.754 0.144 ;
    END
  END xai[169]
  PIN xai[16]
    DIRECTION INPUT ;
    USE SIGNAL ;
    PORT
      LAYER M5 ;
        RECT  8.64 0 8.664 0.192 ;
    END
  END xai[16]
  PIN xai[170]
    DIRECTION INPUT ;
    USE SIGNAL ;
    PORT
      LAYER M5 ;
        RECT  29.904 0 29.928 0.192 ;
    END
  END xai[170]
  PIN xai[171]
    DIRECTION INPUT ;
    USE SIGNAL ;
    PORT
      LAYER M3 ;
        RECT  30.024 0 30.042 0.144 ;
    END
  END xai[171]
  PIN xai[172]
    DIRECTION INPUT ;
    USE SIGNAL ;
    PORT
      LAYER M5 ;
        RECT  30.144 0 30.168 0.192 ;
    END
  END xai[172]
  PIN xai[173]
    DIRECTION INPUT ;
    USE SIGNAL ;
    PORT
      LAYER M3 ;
        RECT  30.312 0 30.33 0.144 ;
    END
  END xai[173]
  PIN xai[174]
    DIRECTION INPUT ;
    USE SIGNAL ;
    PORT
      LAYER M5 ;
        RECT  30.432 0 30.456 0.192 ;
    END
  END xai[174]
  PIN xai[175]
    DIRECTION INPUT ;
    USE SIGNAL ;
    PORT
      LAYER M3 ;
        RECT  30.564 0 30.582 0.144 ;
    END
  END xai[175]
  PIN xai[176]
    DIRECTION INPUT ;
    USE SIGNAL ;
    PORT
      LAYER M5 ;
        RECT  30.72 0 30.744 0.192 ;
    END
  END xai[176]
  PIN xai[177]
    DIRECTION INPUT ;
    USE SIGNAL ;
    PORT
      LAYER M3 ;
        RECT  30.852 0 30.87 0.144 ;
    END
  END xai[177]
  PIN xai[178]
    DIRECTION INPUT ;
    USE SIGNAL ;
    PORT
      LAYER M5 ;
        RECT  31.008 0 31.032 0.192 ;
    END
  END xai[178]
  PIN xai[179]
    DIRECTION INPUT ;
    USE SIGNAL ;
    PORT
      LAYER M3 ;
        RECT  31.14 0 31.158 0.144 ;
    END
  END xai[179]
  PIN xai[17]
    DIRECTION INPUT ;
    USE SIGNAL ;
    PORT
      LAYER M3 ;
        RECT  8.784 0 8.802 0.144 ;
    END
  END xai[17]
  PIN xai[180]
    DIRECTION INPUT ;
    USE SIGNAL ;
    PORT
      LAYER M5 ;
        RECT  31.248 0 31.272 0.192 ;
    END
  END xai[180]
  PIN xai[181]
    DIRECTION INPUT ;
    USE SIGNAL ;
    PORT
      LAYER M3 ;
        RECT  31.392 0 31.41 0.144 ;
    END
  END xai[181]
  PIN xai[182]
    DIRECTION INPUT ;
    USE SIGNAL ;
    PORT
      LAYER M5 ;
        RECT  31.536 0 31.56 0.192 ;
    END
  END xai[182]
  PIN xai[183]
    DIRECTION INPUT ;
    USE SIGNAL ;
    PORT
      LAYER M3 ;
        RECT  31.68 0 31.698 0.144 ;
    END
  END xai[183]
  PIN xai[184]
    DIRECTION INPUT ;
    USE SIGNAL ;
    PORT
      LAYER M5 ;
        RECT  31.824 0 31.848 0.192 ;
    END
  END xai[184]
  PIN xai[185]
    DIRECTION INPUT ;
    USE SIGNAL ;
    PORT
      LAYER M3 ;
        RECT  31.968 0 31.986 0.144 ;
    END
  END xai[185]
  PIN xai[186]
    DIRECTION INPUT ;
    USE SIGNAL ;
    PORT
      LAYER M5 ;
        RECT  32.112 0 32.136 0.192 ;
    END
  END xai[186]
  PIN xai[187]
    DIRECTION INPUT ;
    USE SIGNAL ;
    PORT
      LAYER M3 ;
        RECT  32.22 0 32.238 0.144 ;
    END
  END xai[187]
  PIN xai[188]
    DIRECTION INPUT ;
    USE SIGNAL ;
    PORT
      LAYER M5 ;
        RECT  32.352 0 32.376 0.192 ;
    END
  END xai[188]
  PIN xai[189]
    DIRECTION INPUT ;
    USE SIGNAL ;
    PORT
      LAYER M3 ;
        RECT  32.508 0 32.526 0.144 ;
    END
  END xai[189]
  PIN xai[18]
    DIRECTION INPUT ;
    USE SIGNAL ;
    PORT
      LAYER M5 ;
        RECT  8.928 0 8.952 0.192 ;
    END
  END xai[18]
  PIN xai[190]
    DIRECTION INPUT ;
    USE SIGNAL ;
    PORT
      LAYER M5 ;
        RECT  32.64 0 32.664 0.192 ;
    END
  END xai[190]
  PIN xai[191]
    DIRECTION INPUT ;
    USE SIGNAL ;
    PORT
      LAYER M3 ;
        RECT  32.796 0 32.814 0.144 ;
    END
  END xai[191]
  PIN xai[192]
    DIRECTION INPUT ;
    USE SIGNAL ;
    PORT
      LAYER M5 ;
        RECT  32.928 0 32.952 0.192 ;
    END
  END xai[192]
  PIN xai[193]
    DIRECTION INPUT ;
    USE SIGNAL ;
    PORT
      LAYER M3 ;
        RECT  33.048 0 33.066 0.144 ;
    END
  END xai[193]
  PIN xai[194]
    DIRECTION INPUT ;
    USE SIGNAL ;
    PORT
      LAYER M5 ;
        RECT  33.216 0 33.24 0.192 ;
    END
  END xai[194]
  PIN xai[195]
    DIRECTION INPUT ;
    USE SIGNAL ;
    PORT
      LAYER M3 ;
        RECT  33.336 0 33.354 0.144 ;
    END
  END xai[195]
  PIN xai[196]
    DIRECTION INPUT ;
    USE SIGNAL ;
    PORT
      LAYER M5 ;
        RECT  33.456 0 33.48 0.192 ;
    END
  END xai[196]
  PIN xai[197]
    DIRECTION INPUT ;
    USE SIGNAL ;
    PORT
      LAYER M3 ;
        RECT  33.624 0 33.642 0.144 ;
    END
  END xai[197]
  PIN xai[198]
    DIRECTION INPUT ;
    USE SIGNAL ;
    PORT
      LAYER M5 ;
        RECT  33.744 0 33.768 0.192 ;
    END
  END xai[198]
  PIN xai[199]
    DIRECTION INPUT ;
    USE SIGNAL ;
    PORT
      LAYER M3 ;
        RECT  33.876 0 33.894 0.144 ;
    END
  END xai[199]
  PIN xai[19]
    DIRECTION INPUT ;
    USE SIGNAL ;
    PORT
      LAYER M3 ;
        RECT  9.072 0 9.09 0.144 ;
    END
  END xai[19]
  PIN xai[1]
    DIRECTION INPUT ;
    USE SIGNAL ;
    PORT
      LAYER M3 ;
        RECT  6.588 0 6.606 0.144 ;
    END
  END xai[1]
  PIN xai[200]
    DIRECTION INPUT ;
    USE SIGNAL ;
    PORT
      LAYER M5 ;
        RECT  34.032 0 34.056 0.192 ;
    END
  END xai[200]
  PIN xai[201]
    DIRECTION INPUT ;
    USE SIGNAL ;
    PORT
      LAYER M3 ;
        RECT  34.164 0 34.182 0.144 ;
    END
  END xai[201]
  PIN xai[202]
    DIRECTION INPUT ;
    USE SIGNAL ;
    PORT
      LAYER M5 ;
        RECT  34.272 0 34.296 0.192 ;
    END
  END xai[202]
  PIN xai[203]
    DIRECTION INPUT ;
    USE SIGNAL ;
    PORT
      LAYER M3 ;
        RECT  34.452 0 34.47 0.144 ;
    END
  END xai[203]
  PIN xai[204]
    DIRECTION INPUT ;
    USE SIGNAL ;
    PORT
      LAYER M5 ;
        RECT  34.56 0 34.584 0.192 ;
    END
  END xai[204]
  PIN xai[205]
    DIRECTION INPUT ;
    USE SIGNAL ;
    PORT
      LAYER M3 ;
        RECT  34.704 0 34.722 0.144 ;
    END
  END xai[205]
  PIN xai[206]
    DIRECTION INPUT ;
    USE SIGNAL ;
    PORT
      LAYER M5 ;
        RECT  34.848 0 34.872 0.192 ;
    END
  END xai[206]
  PIN xai[207]
    DIRECTION INPUT ;
    USE SIGNAL ;
    PORT
      LAYER M3 ;
        RECT  34.992 0 35.01 0.144 ;
    END
  END xai[207]
  PIN xai[208]
    DIRECTION INPUT ;
    USE SIGNAL ;
    PORT
      LAYER M5 ;
        RECT  35.136 0 35.16 0.192 ;
    END
  END xai[208]
  PIN xai[209]
    DIRECTION INPUT ;
    USE SIGNAL ;
    PORT
      LAYER M3 ;
        RECT  35.28 0 35.298 0.144 ;
    END
  END xai[209]
  PIN xai[20]
    DIRECTION INPUT ;
    USE SIGNAL ;
    PORT
      LAYER M5 ;
        RECT  9.216 0 9.24 0.192 ;
    END
  END xai[20]
  PIN xai[210]
    DIRECTION INPUT ;
    USE SIGNAL ;
    PORT
      LAYER M5 ;
        RECT  35.376 0 35.4 0.192 ;
    END
  END xai[210]
  PIN xai[211]
    DIRECTION INPUT ;
    USE SIGNAL ;
    PORT
      LAYER M3 ;
        RECT  35.532 0 35.55 0.144 ;
    END
  END xai[211]
  PIN xai[212]
    DIRECTION INPUT ;
    USE SIGNAL ;
    PORT
      LAYER M5 ;
        RECT  35.664 0 35.688 0.192 ;
    END
  END xai[212]
  PIN xai[213]
    DIRECTION INPUT ;
    USE SIGNAL ;
    PORT
      LAYER M3 ;
        RECT  35.82 0 35.838 0.144 ;
    END
  END xai[213]
  PIN xai[214]
    DIRECTION INPUT ;
    USE SIGNAL ;
    PORT
      LAYER M5 ;
        RECT  35.952 0 35.976 0.192 ;
    END
  END xai[214]
  PIN xai[215]
    DIRECTION INPUT ;
    USE SIGNAL ;
    PORT
      LAYER M3 ;
        RECT  36.108 0 36.126 0.144 ;
    END
  END xai[215]
  PIN xai[216]
    DIRECTION INPUT ;
    USE SIGNAL ;
    PORT
      LAYER M5 ;
        RECT  36.24 0 36.264 0.192 ;
    END
  END xai[216]
  PIN xai[217]
    DIRECTION INPUT ;
    USE SIGNAL ;
    PORT
      LAYER M3 ;
        RECT  36.36 0 36.378 0.144 ;
    END
  END xai[217]
  PIN xai[218]
    DIRECTION INPUT ;
    USE SIGNAL ;
    PORT
      LAYER M5 ;
        RECT  36.48 0 36.504 0.192 ;
    END
  END xai[218]
  PIN xai[219]
    DIRECTION INPUT ;
    USE SIGNAL ;
    PORT
      LAYER M3 ;
        RECT  36.648 0 36.666 0.144 ;
    END
  END xai[219]
  PIN xai[21]
    DIRECTION INPUT ;
    USE SIGNAL ;
    PORT
      LAYER M3 ;
        RECT  9.36 0 9.378 0.144 ;
    END
  END xai[21]
  PIN xai[220]
    DIRECTION INPUT ;
    USE SIGNAL ;
    PORT
      LAYER M5 ;
        RECT  36.768 0 36.792 0.192 ;
    END
  END xai[220]
  PIN xai[221]
    DIRECTION INPUT ;
    USE SIGNAL ;
    PORT
      LAYER M3 ;
        RECT  36.9 0 36.918 0.144 ;
    END
  END xai[221]
  PIN xai[222]
    DIRECTION INPUT ;
    USE SIGNAL ;
    PORT
      LAYER M5 ;
        RECT  37.056 0 37.08 0.192 ;
    END
  END xai[222]
  PIN xai[223]
    DIRECTION INPUT ;
    USE SIGNAL ;
    PORT
      LAYER M3 ;
        RECT  37.188 0 37.206 0.144 ;
    END
  END xai[223]
  PIN xai[224]
    DIRECTION INPUT ;
    USE SIGNAL ;
    PORT
      LAYER M5 ;
        RECT  37.344 0 37.368 0.192 ;
    END
  END xai[224]
  PIN xai[225]
    DIRECTION INPUT ;
    USE SIGNAL ;
    PORT
      LAYER M3 ;
        RECT  37.476 0 37.494 0.144 ;
    END
  END xai[225]
  PIN xai[226]
    DIRECTION INPUT ;
    USE SIGNAL ;
    PORT
      LAYER M5 ;
        RECT  37.584 0 37.608 0.192 ;
    END
  END xai[226]
  PIN xai[227]
    DIRECTION INPUT ;
    USE SIGNAL ;
    PORT
      LAYER M3 ;
        RECT  37.728 0 37.746 0.144 ;
    END
  END xai[227]
  PIN xai[228]
    DIRECTION INPUT ;
    USE SIGNAL ;
    PORT
      LAYER M5 ;
        RECT  37.872 0 37.896 0.192 ;
    END
  END xai[228]
  PIN xai[229]
    DIRECTION INPUT ;
    USE SIGNAL ;
    PORT
      LAYER M3 ;
        RECT  38.016 0 38.034 0.144 ;
    END
  END xai[229]
  PIN xai[22]
    DIRECTION INPUT ;
    USE SIGNAL ;
    PORT
      LAYER M5 ;
        RECT  9.456 0 9.48 0.192 ;
    END
  END xai[22]
  PIN xai[230]
    DIRECTION INPUT ;
    USE SIGNAL ;
    PORT
      LAYER M5 ;
        RECT  38.16 0 38.184 0.192 ;
    END
  END xai[230]
  PIN xai[231]
    DIRECTION INPUT ;
    USE SIGNAL ;
    PORT
      LAYER M3 ;
        RECT  38.304 0 38.322 0.144 ;
    END
  END xai[231]
  PIN xai[232]
    DIRECTION INPUT ;
    USE SIGNAL ;
    PORT
      LAYER M5 ;
        RECT  38.448 0 38.472 0.192 ;
    END
  END xai[232]
  PIN xai[233]
    DIRECTION INPUT ;
    USE SIGNAL ;
    PORT
      LAYER M3 ;
        RECT  38.556 0 38.574 0.144 ;
    END
  END xai[233]
  PIN xai[234]
    DIRECTION INPUT ;
    USE SIGNAL ;
    PORT
      LAYER M5 ;
        RECT  38.688 0 38.712 0.192 ;
    END
  END xai[234]
  PIN xai[235]
    DIRECTION INPUT ;
    USE SIGNAL ;
    PORT
      LAYER M3 ;
        RECT  38.844 0 38.862 0.144 ;
    END
  END xai[235]
  PIN xai[236]
    DIRECTION INPUT ;
    USE SIGNAL ;
    PORT
      LAYER M5 ;
        RECT  38.976 0 39 0.192 ;
    END
  END xai[236]
  PIN xai[237]
    DIRECTION INPUT ;
    USE SIGNAL ;
    PORT
      LAYER M3 ;
        RECT  39.132 0 39.15 0.144 ;
    END
  END xai[237]
  PIN xai[238]
    DIRECTION INPUT ;
    USE SIGNAL ;
    PORT
      LAYER M5 ;
        RECT  39.264 0 39.288 0.192 ;
    END
  END xai[238]
  PIN xai[239]
    DIRECTION INPUT ;
    USE SIGNAL ;
    PORT
      LAYER M3 ;
        RECT  39.384 0 39.402 0.144 ;
    END
  END xai[239]
  PIN xai[23]
    DIRECTION INPUT ;
    USE SIGNAL ;
    PORT
      LAYER M3 ;
        RECT  9.612 0 9.63 0.144 ;
    END
  END xai[23]
  PIN xai[240]
    DIRECTION INPUT ;
    USE SIGNAL ;
    PORT
      LAYER M5 ;
        RECT  39.552 0 39.576 0.192 ;
    END
  END xai[240]
  PIN xai[241]
    DIRECTION INPUT ;
    USE SIGNAL ;
    PORT
      LAYER M3 ;
        RECT  39.672 0 39.69 0.144 ;
    END
  END xai[241]
  PIN xai[242]
    DIRECTION INPUT ;
    USE SIGNAL ;
    PORT
      LAYER M5 ;
        RECT  39.792 0 39.816 0.192 ;
    END
  END xai[242]
  PIN xai[243]
    DIRECTION INPUT ;
    USE SIGNAL ;
    PORT
      LAYER M3 ;
        RECT  39.96 0 39.978 0.144 ;
    END
  END xai[243]
  PIN xai[244]
    DIRECTION INPUT ;
    USE SIGNAL ;
    PORT
      LAYER M5 ;
        RECT  40.08 0 40.104 0.192 ;
    END
  END xai[244]
  PIN xai[245]
    DIRECTION INPUT ;
    USE SIGNAL ;
    PORT
      LAYER M3 ;
        RECT  40.212 0 40.23 0.144 ;
    END
  END xai[245]
  PIN xai[246]
    DIRECTION INPUT ;
    USE SIGNAL ;
    PORT
      LAYER M5 ;
        RECT  40.368 0 40.392 0.192 ;
    END
  END xai[246]
  PIN xai[247]
    DIRECTION INPUT ;
    USE SIGNAL ;
    PORT
      LAYER M3 ;
        RECT  40.5 0 40.518 0.144 ;
    END
  END xai[247]
  PIN xai[248]
    DIRECTION INPUT ;
    USE SIGNAL ;
    PORT
      LAYER M5 ;
        RECT  40.656 0 40.68 0.192 ;
    END
  END xai[248]
  PIN xai[249]
    DIRECTION INPUT ;
    USE SIGNAL ;
    PORT
      LAYER M3 ;
        RECT  40.788 0 40.806 0.144 ;
    END
  END xai[249]
  PIN xai[24]
    DIRECTION INPUT ;
    USE SIGNAL ;
    PORT
      LAYER M5 ;
        RECT  9.744 0 9.768 0.192 ;
    END
  END xai[24]
  PIN xai[250]
    DIRECTION INPUT ;
    USE SIGNAL ;
    PORT
      LAYER M5 ;
        RECT  40.896 0 40.92 0.192 ;
    END
  END xai[250]
  PIN xai[251]
    DIRECTION INPUT ;
    USE SIGNAL ;
    PORT
      LAYER M3 ;
        RECT  41.04 0 41.058 0.144 ;
    END
  END xai[251]
  PIN xai[252]
    DIRECTION INPUT ;
    USE SIGNAL ;
    PORT
      LAYER M5 ;
        RECT  41.184 0 41.208 0.192 ;
    END
  END xai[252]
  PIN xai[253]
    DIRECTION INPUT ;
    USE SIGNAL ;
    PORT
      LAYER M3 ;
        RECT  41.328 0 41.346 0.144 ;
    END
  END xai[253]
  PIN xai[254]
    DIRECTION INPUT ;
    USE SIGNAL ;
    PORT
      LAYER M5 ;
        RECT  41.472 0 41.496 0.192 ;
    END
  END xai[254]
  PIN xai[255]
    DIRECTION INPUT ;
    USE SIGNAL ;
    PORT
      LAYER M3 ;
        RECT  41.616 0 41.634 0.144 ;
    END
  END xai[255]
  PIN xai[256]
    DIRECTION INPUT ;
    USE SIGNAL ;
    PORT
      LAYER M5 ;
        RECT  41.76 0 41.784 0.192 ;
    END
  END xai[256]
  PIN xai[257]
    DIRECTION INPUT ;
    USE SIGNAL ;
    PORT
      LAYER M3 ;
        RECT  41.868 0 41.886 0.144 ;
    END
  END xai[257]
  PIN xai[258]
    DIRECTION INPUT ;
    USE SIGNAL ;
    PORT
      LAYER M5 ;
        RECT  42 0 42.024 0.192 ;
    END
  END xai[258]
  PIN xai[259]
    DIRECTION INPUT ;
    USE SIGNAL ;
    PORT
      LAYER M3 ;
        RECT  42.156 0 42.174 0.144 ;
    END
  END xai[259]
  PIN xai[25]
    DIRECTION INPUT ;
    USE SIGNAL ;
    PORT
      LAYER M3 ;
        RECT  9.9 0 9.918 0.144 ;
    END
  END xai[25]
  PIN xai[260]
    DIRECTION INPUT ;
    USE SIGNAL ;
    PORT
      LAYER M5 ;
        RECT  42.288 0 42.312 0.192 ;
    END
  END xai[260]
  PIN xai[261]
    DIRECTION INPUT ;
    USE SIGNAL ;
    PORT
      LAYER M3 ;
        RECT  42.444 0 42.462 0.144 ;
    END
  END xai[261]
  PIN xai[262]
    DIRECTION INPUT ;
    USE SIGNAL ;
    PORT
      LAYER M5 ;
        RECT  42.576 0 42.6 0.192 ;
    END
  END xai[262]
  PIN xai[263]
    DIRECTION INPUT ;
    USE SIGNAL ;
    PORT
      LAYER M3 ;
        RECT  42.696 0 42.714 0.144 ;
    END
  END xai[263]
  PIN xai[264]
    DIRECTION INPUT ;
    USE SIGNAL ;
    PORT
      LAYER M5 ;
        RECT  42.864 0 42.888 0.192 ;
    END
  END xai[264]
  PIN xai[265]
    DIRECTION INPUT ;
    USE SIGNAL ;
    PORT
      LAYER M3 ;
        RECT  42.984 0 43.002 0.144 ;
    END
  END xai[265]
  PIN xai[266]
    DIRECTION INPUT ;
    USE SIGNAL ;
    PORT
      LAYER M5 ;
        RECT  43.104 0 43.128 0.192 ;
    END
  END xai[266]
  PIN xai[267]
    DIRECTION INPUT ;
    USE SIGNAL ;
    PORT
      LAYER M3 ;
        RECT  43.272 0 43.29 0.144 ;
    END
  END xai[267]
  PIN xai[268]
    DIRECTION INPUT ;
    USE SIGNAL ;
    PORT
      LAYER M5 ;
        RECT  43.392 0 43.416 0.192 ;
    END
  END xai[268]
  PIN xai[269]
    DIRECTION INPUT ;
    USE SIGNAL ;
    PORT
      LAYER M3 ;
        RECT  43.524 0 43.542 0.144 ;
    END
  END xai[269]
  PIN xai[26]
    DIRECTION INPUT ;
    USE SIGNAL ;
    PORT
      LAYER M5 ;
        RECT  10.032 0 10.056 0.192 ;
    END
  END xai[26]
  PIN xai[270]
    DIRECTION INPUT ;
    USE SIGNAL ;
    PORT
      LAYER M5 ;
        RECT  43.68 0 43.704 0.192 ;
    END
  END xai[270]
  PIN xai[271]
    DIRECTION INPUT ;
    USE SIGNAL ;
    PORT
      LAYER M3 ;
        RECT  43.812 0 43.83 0.144 ;
    END
  END xai[271]
  PIN xai[272]
    DIRECTION INPUT ;
    USE SIGNAL ;
    PORT
      LAYER M5 ;
        RECT  43.968 0 43.992 0.192 ;
    END
  END xai[272]
  PIN xai[273]
    DIRECTION INPUT ;
    USE SIGNAL ;
    PORT
      LAYER M3 ;
        RECT  44.1 0 44.118 0.144 ;
    END
  END xai[273]
  PIN xai[274]
    DIRECTION INPUT ;
    USE SIGNAL ;
    PORT
      LAYER M5 ;
        RECT  44.208 0 44.232 0.192 ;
    END
  END xai[274]
  PIN xai[275]
    DIRECTION INPUT ;
    USE SIGNAL ;
    PORT
      LAYER M3 ;
        RECT  44.352 0 44.37 0.144 ;
    END
  END xai[275]
  PIN xai[276]
    DIRECTION INPUT ;
    USE SIGNAL ;
    PORT
      LAYER M5 ;
        RECT  44.496 0 44.52 0.192 ;
    END
  END xai[276]
  PIN xai[277]
    DIRECTION INPUT ;
    USE SIGNAL ;
    PORT
      LAYER M3 ;
        RECT  44.64 0 44.658 0.144 ;
    END
  END xai[277]
  PIN xai[278]
    DIRECTION INPUT ;
    USE SIGNAL ;
    PORT
      LAYER M5 ;
        RECT  44.784 0 44.808 0.192 ;
    END
  END xai[278]
  PIN xai[279]
    DIRECTION INPUT ;
    USE SIGNAL ;
    PORT
      LAYER M3 ;
        RECT  44.928 0 44.946 0.144 ;
    END
  END xai[279]
  PIN xai[27]
    DIRECTION INPUT ;
    USE SIGNAL ;
    PORT
      LAYER M3 ;
        RECT  10.188 0 10.206 0.144 ;
    END
  END xai[27]
  PIN xai[280]
    DIRECTION INPUT ;
    USE SIGNAL ;
    PORT
      LAYER M5 ;
        RECT  45.072 0 45.096 0.192 ;
    END
  END xai[280]
  PIN xai[281]
    DIRECTION INPUT ;
    USE SIGNAL ;
    PORT
      LAYER M3 ;
        RECT  45.18 0 45.198 0.144 ;
    END
  END xai[281]
  PIN xai[282]
    DIRECTION INPUT ;
    USE SIGNAL ;
    PORT
      LAYER M5 ;
        RECT  45.312 0 45.336 0.192 ;
    END
  END xai[282]
  PIN xai[28]
    DIRECTION INPUT ;
    USE SIGNAL ;
    PORT
      LAYER M5 ;
        RECT  10.32 0 10.344 0.192 ;
    END
  END xai[28]
  PIN xai[29]
    DIRECTION INPUT ;
    USE SIGNAL ;
    PORT
      LAYER M3 ;
        RECT  10.44 0 10.458 0.144 ;
    END
  END xai[29]
  PIN xai[2]
    DIRECTION INPUT ;
    USE SIGNAL ;
    PORT
      LAYER M5 ;
        RECT  6.72 0 6.744 0.192 ;
    END
  END xai[2]
  PIN xai[30]
    DIRECTION INPUT ;
    USE SIGNAL ;
    PORT
      LAYER M5 ;
        RECT  10.56 0 10.584 0.192 ;
    END
  END xai[30]
  PIN xai[31]
    DIRECTION INPUT ;
    USE SIGNAL ;
    PORT
      LAYER M3 ;
        RECT  10.728 0 10.746 0.144 ;
    END
  END xai[31]
  PIN xai[32]
    DIRECTION INPUT ;
    USE SIGNAL ;
    PORT
      LAYER M5 ;
        RECT  10.848 0 10.872 0.192 ;
    END
  END xai[32]
  PIN xai[33]
    DIRECTION INPUT ;
    USE SIGNAL ;
    PORT
      LAYER M3 ;
        RECT  10.98 0 10.998 0.144 ;
    END
  END xai[33]
  PIN xai[34]
    DIRECTION INPUT ;
    USE SIGNAL ;
    PORT
      LAYER M5 ;
        RECT  11.136 0 11.16 0.192 ;
    END
  END xai[34]
  PIN xai[35]
    DIRECTION INPUT ;
    USE SIGNAL ;
    PORT
      LAYER M3 ;
        RECT  11.268 0 11.286 0.144 ;
    END
  END xai[35]
  PIN xai[36]
    DIRECTION INPUT ;
    USE SIGNAL ;
    PORT
      LAYER M5 ;
        RECT  11.424 0 11.448 0.192 ;
    END
  END xai[36]
  PIN xai[37]
    DIRECTION INPUT ;
    USE SIGNAL ;
    PORT
      LAYER M3 ;
        RECT  11.556 0 11.574 0.144 ;
    END
  END xai[37]
  PIN xai[38]
    DIRECTION INPUT ;
    USE SIGNAL ;
    PORT
      LAYER M5 ;
        RECT  11.664 0 11.688 0.192 ;
    END
  END xai[38]
  PIN xai[39]
    DIRECTION INPUT ;
    USE SIGNAL ;
    PORT
      LAYER M3 ;
        RECT  11.808 0 11.826 0.144 ;
    END
  END xai[39]
  PIN xai[3]
    DIRECTION INPUT ;
    USE SIGNAL ;
    PORT
      LAYER M3 ;
        RECT  6.876 0 6.894 0.144 ;
    END
  END xai[3]
  PIN xai[40]
    DIRECTION INPUT ;
    USE SIGNAL ;
    PORT
      LAYER M5 ;
        RECT  11.952 0 11.976 0.192 ;
    END
  END xai[40]
  PIN xai[41]
    DIRECTION INPUT ;
    USE SIGNAL ;
    PORT
      LAYER M3 ;
        RECT  12.096 0 12.114 0.144 ;
    END
  END xai[41]
  PIN xai[42]
    DIRECTION INPUT ;
    USE SIGNAL ;
    PORT
      LAYER M5 ;
        RECT  12.24 0 12.264 0.192 ;
    END
  END xai[42]
  PIN xai[43]
    DIRECTION INPUT ;
    USE SIGNAL ;
    PORT
      LAYER M3 ;
        RECT  12.384 0 12.402 0.144 ;
    END
  END xai[43]
  PIN xai[44]
    DIRECTION INPUT ;
    USE SIGNAL ;
    PORT
      LAYER M5 ;
        RECT  12.528 0 12.552 0.192 ;
    END
  END xai[44]
  PIN xai[45]
    DIRECTION INPUT ;
    USE SIGNAL ;
    PORT
      LAYER M3 ;
        RECT  12.636 0 12.654 0.144 ;
    END
  END xai[45]
  PIN xai[46]
    DIRECTION INPUT ;
    USE SIGNAL ;
    PORT
      LAYER M5 ;
        RECT  12.768 0 12.792 0.192 ;
    END
  END xai[46]
  PIN xai[47]
    DIRECTION INPUT ;
    USE SIGNAL ;
    PORT
      LAYER M3 ;
        RECT  12.924 0 12.942 0.144 ;
    END
  END xai[47]
  PIN xai[48]
    DIRECTION INPUT ;
    USE SIGNAL ;
    PORT
      LAYER M5 ;
        RECT  13.056 0 13.08 0.192 ;
    END
  END xai[48]
  PIN xai[49]
    DIRECTION INPUT ;
    USE SIGNAL ;
    PORT
      LAYER M3 ;
        RECT  13.212 0 13.23 0.144 ;
    END
  END xai[49]
  PIN xai[4]
    DIRECTION INPUT ;
    USE SIGNAL ;
    PORT
      LAYER M5 ;
        RECT  7.008 0 7.032 0.192 ;
    END
  END xai[4]
  PIN xai[50]
    DIRECTION INPUT ;
    USE SIGNAL ;
    PORT
      LAYER M5 ;
        RECT  13.344 0 13.368 0.192 ;
    END
  END xai[50]
  PIN xai[51]
    DIRECTION INPUT ;
    USE SIGNAL ;
    PORT
      LAYER M3 ;
        RECT  13.464 0 13.482 0.144 ;
    END
  END xai[51]
  PIN xai[52]
    DIRECTION INPUT ;
    USE SIGNAL ;
    PORT
      LAYER M5 ;
        RECT  13.632 0 13.656 0.192 ;
    END
  END xai[52]
  PIN xai[53]
    DIRECTION INPUT ;
    USE SIGNAL ;
    PORT
      LAYER M3 ;
        RECT  13.752 0 13.77 0.144 ;
    END
  END xai[53]
  PIN xai[54]
    DIRECTION INPUT ;
    USE SIGNAL ;
    PORT
      LAYER M5 ;
        RECT  13.872 0 13.896 0.192 ;
    END
  END xai[54]
  PIN xai[55]
    DIRECTION INPUT ;
    USE SIGNAL ;
    PORT
      LAYER M3 ;
        RECT  14.04 0 14.058 0.144 ;
    END
  END xai[55]
  PIN xai[56]
    DIRECTION INPUT ;
    USE SIGNAL ;
    PORT
      LAYER M5 ;
        RECT  14.16 0 14.184 0.192 ;
    END
  END xai[56]
  PIN xai[57]
    DIRECTION INPUT ;
    USE SIGNAL ;
    PORT
      LAYER M3 ;
        RECT  14.292 0 14.31 0.144 ;
    END
  END xai[57]
  PIN xai[58]
    DIRECTION INPUT ;
    USE SIGNAL ;
    PORT
      LAYER M5 ;
        RECT  14.448 0 14.472 0.192 ;
    END
  END xai[58]
  PIN xai[59]
    DIRECTION INPUT ;
    USE SIGNAL ;
    PORT
      LAYER M3 ;
        RECT  14.58 0 14.598 0.144 ;
    END
  END xai[59]
  PIN xai[5]
    DIRECTION INPUT ;
    USE SIGNAL ;
    PORT
      LAYER M3 ;
        RECT  7.128 0 7.146 0.144 ;
    END
  END xai[5]
  PIN xai[60]
    DIRECTION INPUT ;
    USE SIGNAL ;
    PORT
      LAYER M5 ;
        RECT  14.736 0 14.76 0.192 ;
    END
  END xai[60]
  PIN xai[61]
    DIRECTION INPUT ;
    USE SIGNAL ;
    PORT
      LAYER M3 ;
        RECT  14.868 0 14.886 0.144 ;
    END
  END xai[61]
  PIN xai[62]
    DIRECTION INPUT ;
    USE SIGNAL ;
    PORT
      LAYER M5 ;
        RECT  14.976 0 15 0.192 ;
    END
  END xai[62]
  PIN xai[63]
    DIRECTION INPUT ;
    USE SIGNAL ;
    PORT
      LAYER M3 ;
        RECT  15.12 0 15.138 0.144 ;
    END
  END xai[63]
  PIN xai[64]
    DIRECTION INPUT ;
    USE SIGNAL ;
    PORT
      LAYER M5 ;
        RECT  15.264 0 15.288 0.192 ;
    END
  END xai[64]
  PIN xai[65]
    DIRECTION INPUT ;
    USE SIGNAL ;
    PORT
      LAYER M3 ;
        RECT  15.408 0 15.426 0.144 ;
    END
  END xai[65]
  PIN xai[66]
    DIRECTION INPUT ;
    USE SIGNAL ;
    PORT
      LAYER M5 ;
        RECT  15.552 0 15.576 0.192 ;
    END
  END xai[66]
  PIN xai[67]
    DIRECTION INPUT ;
    USE SIGNAL ;
    PORT
      LAYER M3 ;
        RECT  15.696 0 15.714 0.144 ;
    END
  END xai[67]
  PIN xai[68]
    DIRECTION INPUT ;
    USE SIGNAL ;
    PORT
      LAYER M5 ;
        RECT  15.84 0 15.864 0.192 ;
    END
  END xai[68]
  PIN xai[69]
    DIRECTION INPUT ;
    USE SIGNAL ;
    PORT
      LAYER M3 ;
        RECT  15.948 0 15.966 0.144 ;
    END
  END xai[69]
  PIN xai[6]
    DIRECTION INPUT ;
    USE SIGNAL ;
    PORT
      LAYER M5 ;
        RECT  7.296 0 7.32 0.192 ;
    END
  END xai[6]
  PIN xai[70]
    DIRECTION INPUT ;
    USE SIGNAL ;
    PORT
      LAYER M5 ;
        RECT  16.08 0 16.104 0.192 ;
    END
  END xai[70]
  PIN xai[71]
    DIRECTION INPUT ;
    USE SIGNAL ;
    PORT
      LAYER M3 ;
        RECT  16.236 0 16.254 0.144 ;
    END
  END xai[71]
  PIN xai[72]
    DIRECTION INPUT ;
    USE SIGNAL ;
    PORT
      LAYER M5 ;
        RECT  16.368 0 16.392 0.192 ;
    END
  END xai[72]
  PIN xai[73]
    DIRECTION INPUT ;
    USE SIGNAL ;
    PORT
      LAYER M3 ;
        RECT  16.524 0 16.542 0.144 ;
    END
  END xai[73]
  PIN xai[74]
    DIRECTION INPUT ;
    USE SIGNAL ;
    PORT
      LAYER M5 ;
        RECT  16.656 0 16.68 0.192 ;
    END
  END xai[74]
  PIN xai[75]
    DIRECTION INPUT ;
    USE SIGNAL ;
    PORT
      LAYER M3 ;
        RECT  16.776 0 16.794 0.144 ;
    END
  END xai[75]
  PIN xai[76]
    DIRECTION INPUT ;
    USE SIGNAL ;
    PORT
      LAYER M5 ;
        RECT  16.944 0 16.968 0.192 ;
    END
  END xai[76]
  PIN xai[77]
    DIRECTION INPUT ;
    USE SIGNAL ;
    PORT
      LAYER M3 ;
        RECT  17.064 0 17.082 0.144 ;
    END
  END xai[77]
  PIN xai[78]
    DIRECTION INPUT ;
    USE SIGNAL ;
    PORT
      LAYER M5 ;
        RECT  17.184 0 17.208 0.192 ;
    END
  END xai[78]
  PIN xai[79]
    DIRECTION INPUT ;
    USE SIGNAL ;
    PORT
      LAYER M3 ;
        RECT  17.352 0 17.37 0.144 ;
    END
  END xai[79]
  PIN xai[7]
    DIRECTION INPUT ;
    USE SIGNAL ;
    PORT
      LAYER M3 ;
        RECT  7.416 0 7.434 0.144 ;
    END
  END xai[7]
  PIN xai[80]
    DIRECTION INPUT ;
    USE SIGNAL ;
    PORT
      LAYER M5 ;
        RECT  17.472 0 17.496 0.192 ;
    END
  END xai[80]
  PIN xai[81]
    DIRECTION INPUT ;
    USE SIGNAL ;
    PORT
      LAYER M3 ;
        RECT  17.604 0 17.622 0.144 ;
    END
  END xai[81]
  PIN xai[82]
    DIRECTION INPUT ;
    USE SIGNAL ;
    PORT
      LAYER M5 ;
        RECT  17.76 0 17.784 0.192 ;
    END
  END xai[82]
  PIN xai[83]
    DIRECTION INPUT ;
    USE SIGNAL ;
    PORT
      LAYER M3 ;
        RECT  17.892 0 17.91 0.144 ;
    END
  END xai[83]
  PIN xai[84]
    DIRECTION INPUT ;
    USE SIGNAL ;
    PORT
      LAYER M5 ;
        RECT  18.048 0 18.072 0.192 ;
    END
  END xai[84]
  PIN xai[85]
    DIRECTION INPUT ;
    USE SIGNAL ;
    PORT
      LAYER M3 ;
        RECT  18.18 0 18.198 0.144 ;
    END
  END xai[85]
  PIN xai[86]
    DIRECTION INPUT ;
    USE SIGNAL ;
    PORT
      LAYER M5 ;
        RECT  18.288 0 18.312 0.192 ;
    END
  END xai[86]
  PIN xai[87]
    DIRECTION INPUT ;
    USE SIGNAL ;
    PORT
      LAYER M3 ;
        RECT  18.432 0 18.45 0.144 ;
    END
  END xai[87]
  PIN xai[88]
    DIRECTION INPUT ;
    USE SIGNAL ;
    PORT
      LAYER M5 ;
        RECT  18.576 0 18.6 0.192 ;
    END
  END xai[88]
  PIN xai[89]
    DIRECTION INPUT ;
    USE SIGNAL ;
    PORT
      LAYER M3 ;
        RECT  18.72 0 18.738 0.144 ;
    END
  END xai[89]
  PIN xai[8]
    DIRECTION INPUT ;
    USE SIGNAL ;
    PORT
      LAYER M5 ;
        RECT  7.536 0 7.56 0.192 ;
    END
  END xai[8]
  PIN xai[90]
    DIRECTION INPUT ;
    USE SIGNAL ;
    PORT
      LAYER M5 ;
        RECT  18.864 0 18.888 0.192 ;
    END
  END xai[90]
  PIN xai[91]
    DIRECTION INPUT ;
    USE SIGNAL ;
    PORT
      LAYER M3 ;
        RECT  19.008 0 19.026 0.144 ;
    END
  END xai[91]
  PIN xai[92]
    DIRECTION INPUT ;
    USE SIGNAL ;
    PORT
      LAYER M5 ;
        RECT  19.152 0 19.176 0.192 ;
    END
  END xai[92]
  PIN xai[93]
    DIRECTION INPUT ;
    USE SIGNAL ;
    PORT
      LAYER M3 ;
        RECT  19.26 0 19.278 0.144 ;
    END
  END xai[93]
  PIN xai[94]
    DIRECTION INPUT ;
    USE SIGNAL ;
    PORT
      LAYER M5 ;
        RECT  19.392 0 19.416 0.192 ;
    END
  END xai[94]
  PIN xai[95]
    DIRECTION INPUT ;
    USE SIGNAL ;
    PORT
      LAYER M3 ;
        RECT  19.548 0 19.566 0.144 ;
    END
  END xai[95]
  PIN xai[96]
    DIRECTION INPUT ;
    USE SIGNAL ;
    PORT
      LAYER M5 ;
        RECT  19.68 0 19.704 0.192 ;
    END
  END xai[96]
  PIN xai[97]
    DIRECTION INPUT ;
    USE SIGNAL ;
    PORT
      LAYER M3 ;
        RECT  19.836 0 19.854 0.144 ;
    END
  END xai[97]
  PIN xai[98]
    DIRECTION INPUT ;
    USE SIGNAL ;
    PORT
      LAYER M5 ;
        RECT  19.968 0 19.992 0.192 ;
    END
  END xai[98]
  PIN xai[99]
    DIRECTION INPUT ;
    USE SIGNAL ;
    PORT
      LAYER M3 ;
        RECT  20.088 0 20.106 0.144 ;
    END
  END xai[99]
  PIN xai[9]
    DIRECTION INPUT ;
    USE SIGNAL ;
    PORT
      LAYER M3 ;
        RECT  7.704 0 7.722 0.144 ;
    END
  END xai[9]
  PIN xb[0]
    DIRECTION OUTPUT ;
    USE SIGNAL ;
    PORT
      LAYER M3 ;
        RECT  45.468 30.096 45.486 30.24 ;
    END
  END xb[0]
  PIN xb[100]
    DIRECTION OUTPUT ;
    USE SIGNAL ;
    PORT
      LAYER M3 ;
        RECT  59.256 30.096 59.274 30.24 ;
    END
  END xb[100]
  PIN xb[101]
    DIRECTION OUTPUT ;
    USE SIGNAL ;
    PORT
      LAYER M5 ;
        RECT  59.376 30.048 59.4 30.24 ;
    END
  END xb[101]
  PIN xb[102]
    DIRECTION OUTPUT ;
    USE SIGNAL ;
    PORT
      LAYER M3 ;
        RECT  59.544 30.096 59.562 30.24 ;
    END
  END xb[102]
  PIN xb[103]
    DIRECTION OUTPUT ;
    USE SIGNAL ;
    PORT
      LAYER M5 ;
        RECT  59.664 30.048 59.688 30.24 ;
    END
  END xb[103]
  PIN xb[104]
    DIRECTION OUTPUT ;
    USE SIGNAL ;
    PORT
      LAYER M3 ;
        RECT  59.796 30.096 59.814 30.24 ;
    END
  END xb[104]
  PIN xb[105]
    DIRECTION OUTPUT ;
    USE SIGNAL ;
    PORT
      LAYER M5 ;
        RECT  59.952 30.048 59.976 30.24 ;
    END
  END xb[105]
  PIN xb[106]
    DIRECTION OUTPUT ;
    USE SIGNAL ;
    PORT
      LAYER M3 ;
        RECT  60.084 30.096 60.102 30.24 ;
    END
  END xb[106]
  PIN xb[107]
    DIRECTION OUTPUT ;
    USE SIGNAL ;
    PORT
      LAYER M5 ;
        RECT  60.192 30.048 60.216 30.24 ;
    END
  END xb[107]
  PIN xb[108]
    DIRECTION OUTPUT ;
    USE SIGNAL ;
    PORT
      LAYER M3 ;
        RECT  60.372 30.096 60.39 30.24 ;
    END
  END xb[108]
  PIN xb[109]
    DIRECTION OUTPUT ;
    USE SIGNAL ;
    PORT
      LAYER M5 ;
        RECT  60.48 30.048 60.504 30.24 ;
    END
  END xb[109]
  PIN xb[10]
    DIRECTION OUTPUT ;
    USE SIGNAL ;
    PORT
      LAYER M3 ;
        RECT  46.836 30.096 46.854 30.24 ;
    END
  END xb[10]
  PIN xb[110]
    DIRECTION OUTPUT ;
    USE SIGNAL ;
    PORT
      LAYER M3 ;
        RECT  60.624 30.096 60.642 30.24 ;
    END
  END xb[110]
  PIN xb[111]
    DIRECTION OUTPUT ;
    USE SIGNAL ;
    PORT
      LAYER M5 ;
        RECT  60.768 30.048 60.792 30.24 ;
    END
  END xb[111]
  PIN xb[112]
    DIRECTION OUTPUT ;
    USE SIGNAL ;
    PORT
      LAYER M3 ;
        RECT  60.912 30.096 60.93 30.24 ;
    END
  END xb[112]
  PIN xb[113]
    DIRECTION OUTPUT ;
    USE SIGNAL ;
    PORT
      LAYER M5 ;
        RECT  61.056 30.048 61.08 30.24 ;
    END
  END xb[113]
  PIN xb[114]
    DIRECTION OUTPUT ;
    USE SIGNAL ;
    PORT
      LAYER M3 ;
        RECT  61.2 30.096 61.218 30.24 ;
    END
  END xb[114]
  PIN xb[115]
    DIRECTION OUTPUT ;
    USE SIGNAL ;
    PORT
      LAYER M5 ;
        RECT  61.296 30.048 61.32 30.24 ;
    END
  END xb[115]
  PIN xb[116]
    DIRECTION OUTPUT ;
    USE SIGNAL ;
    PORT
      LAYER M3 ;
        RECT  61.452 30.096 61.47 30.24 ;
    END
  END xb[116]
  PIN xb[117]
    DIRECTION OUTPUT ;
    USE SIGNAL ;
    PORT
      LAYER M5 ;
        RECT  61.584 30.048 61.608 30.24 ;
    END
  END xb[117]
  PIN xb[118]
    DIRECTION OUTPUT ;
    USE SIGNAL ;
    PORT
      LAYER M3 ;
        RECT  61.74 30.096 61.758 30.24 ;
    END
  END xb[118]
  PIN xb[119]
    DIRECTION OUTPUT ;
    USE SIGNAL ;
    PORT
      LAYER M5 ;
        RECT  61.872 30.048 61.896 30.24 ;
    END
  END xb[119]
  PIN xb[11]
    DIRECTION OUTPUT ;
    USE SIGNAL ;
    PORT
      LAYER M5 ;
        RECT  46.992 30.048 47.016 30.24 ;
    END
  END xb[11]
  PIN xb[120]
    DIRECTION OUTPUT ;
    USE SIGNAL ;
    PORT
      LAYER M3 ;
        RECT  62.028 30.096 62.046 30.24 ;
    END
  END xb[120]
  PIN xb[121]
    DIRECTION OUTPUT ;
    USE SIGNAL ;
    PORT
      LAYER M5 ;
        RECT  62.16 30.048 62.184 30.24 ;
    END
  END xb[121]
  PIN xb[122]
    DIRECTION OUTPUT ;
    USE SIGNAL ;
    PORT
      LAYER M3 ;
        RECT  62.28 30.096 62.298 30.24 ;
    END
  END xb[122]
  PIN xb[123]
    DIRECTION OUTPUT ;
    USE SIGNAL ;
    PORT
      LAYER M5 ;
        RECT  62.4 30.048 62.424 30.24 ;
    END
  END xb[123]
  PIN xb[124]
    DIRECTION OUTPUT ;
    USE SIGNAL ;
    PORT
      LAYER M3 ;
        RECT  62.568 30.096 62.586 30.24 ;
    END
  END xb[124]
  PIN xb[125]
    DIRECTION OUTPUT ;
    USE SIGNAL ;
    PORT
      LAYER M5 ;
        RECT  62.688 30.048 62.712 30.24 ;
    END
  END xb[125]
  PIN xb[126]
    DIRECTION OUTPUT ;
    USE SIGNAL ;
    PORT
      LAYER M3 ;
        RECT  62.82 30.096 62.838 30.24 ;
    END
  END xb[126]
  PIN xb[127]
    DIRECTION OUTPUT ;
    USE SIGNAL ;
    PORT
      LAYER M5 ;
        RECT  62.976 30.048 63 30.24 ;
    END
  END xb[127]
  PIN xb[128]
    DIRECTION OUTPUT ;
    USE SIGNAL ;
    PORT
      LAYER M3 ;
        RECT  63.108 30.096 63.126 30.24 ;
    END
  END xb[128]
  PIN xb[129]
    DIRECTION OUTPUT ;
    USE SIGNAL ;
    PORT
      LAYER M5 ;
        RECT  63.264 30.048 63.288 30.24 ;
    END
  END xb[129]
  PIN xb[12]
    DIRECTION OUTPUT ;
    USE SIGNAL ;
    PORT
      LAYER M3 ;
        RECT  47.124 30.096 47.142 30.24 ;
    END
  END xb[12]
  PIN xb[130]
    DIRECTION OUTPUT ;
    USE SIGNAL ;
    PORT
      LAYER M3 ;
        RECT  63.396 30.096 63.414 30.24 ;
    END
  END xb[130]
  PIN xb[131]
    DIRECTION OUTPUT ;
    USE SIGNAL ;
    PORT
      LAYER M5 ;
        RECT  63.504 30.048 63.528 30.24 ;
    END
  END xb[131]
  PIN xb[132]
    DIRECTION OUTPUT ;
    USE SIGNAL ;
    PORT
      LAYER M3 ;
        RECT  63.648 30.096 63.666 30.24 ;
    END
  END xb[132]
  PIN xb[133]
    DIRECTION OUTPUT ;
    USE SIGNAL ;
    PORT
      LAYER M5 ;
        RECT  63.792 30.048 63.816 30.24 ;
    END
  END xb[133]
  PIN xb[134]
    DIRECTION OUTPUT ;
    USE SIGNAL ;
    PORT
      LAYER M3 ;
        RECT  63.936 30.096 63.954 30.24 ;
    END
  END xb[134]
  PIN xb[135]
    DIRECTION OUTPUT ;
    USE SIGNAL ;
    PORT
      LAYER M5 ;
        RECT  64.08 30.048 64.104 30.24 ;
    END
  END xb[135]
  PIN xb[136]
    DIRECTION OUTPUT ;
    USE SIGNAL ;
    PORT
      LAYER M3 ;
        RECT  64.224 30.096 64.242 30.24 ;
    END
  END xb[136]
  PIN xb[137]
    DIRECTION OUTPUT ;
    USE SIGNAL ;
    PORT
      LAYER M5 ;
        RECT  64.368 30.048 64.392 30.24 ;
    END
  END xb[137]
  PIN xb[138]
    DIRECTION OUTPUT ;
    USE SIGNAL ;
    PORT
      LAYER M3 ;
        RECT  64.476 30.096 64.494 30.24 ;
    END
  END xb[138]
  PIN xb[139]
    DIRECTION OUTPUT ;
    USE SIGNAL ;
    PORT
      LAYER M5 ;
        RECT  64.608 30.048 64.632 30.24 ;
    END
  END xb[139]
  PIN xb[13]
    DIRECTION OUTPUT ;
    USE SIGNAL ;
    PORT
      LAYER M5 ;
        RECT  47.232 30.048 47.256 30.24 ;
    END
  END xb[13]
  PIN xb[140]
    DIRECTION OUTPUT ;
    USE SIGNAL ;
    PORT
      LAYER M3 ;
        RECT  64.764 30.096 64.782 30.24 ;
    END
  END xb[140]
  PIN xb[141]
    DIRECTION OUTPUT ;
    USE SIGNAL ;
    PORT
      LAYER M5 ;
        RECT  64.896 30.048 64.92 30.24 ;
    END
  END xb[141]
  PIN xb[142]
    DIRECTION OUTPUT ;
    USE SIGNAL ;
    PORT
      LAYER M3 ;
        RECT  65.052 30.096 65.07 30.24 ;
    END
  END xb[142]
  PIN xb[143]
    DIRECTION OUTPUT ;
    USE SIGNAL ;
    PORT
      LAYER M5 ;
        RECT  65.184 30.048 65.208 30.24 ;
    END
  END xb[143]
  PIN xb[144]
    DIRECTION OUTPUT ;
    USE SIGNAL ;
    PORT
      LAYER M3 ;
        RECT  65.304 30.096 65.322 30.24 ;
    END
  END xb[144]
  PIN xb[145]
    DIRECTION OUTPUT ;
    USE SIGNAL ;
    PORT
      LAYER M5 ;
        RECT  65.472 30.048 65.496 30.24 ;
    END
  END xb[145]
  PIN xb[146]
    DIRECTION OUTPUT ;
    USE SIGNAL ;
    PORT
      LAYER M3 ;
        RECT  65.592 30.096 65.61 30.24 ;
    END
  END xb[146]
  PIN xb[147]
    DIRECTION OUTPUT ;
    USE SIGNAL ;
    PORT
      LAYER M5 ;
        RECT  65.712 30.048 65.736 30.24 ;
    END
  END xb[147]
  PIN xb[148]
    DIRECTION OUTPUT ;
    USE SIGNAL ;
    PORT
      LAYER M3 ;
        RECT  65.88 30.096 65.898 30.24 ;
    END
  END xb[148]
  PIN xb[149]
    DIRECTION OUTPUT ;
    USE SIGNAL ;
    PORT
      LAYER M5 ;
        RECT  66 30.048 66.024 30.24 ;
    END
  END xb[149]
  PIN xb[14]
    DIRECTION OUTPUT ;
    USE SIGNAL ;
    PORT
      LAYER M3 ;
        RECT  47.412 30.096 47.43 30.24 ;
    END
  END xb[14]
  PIN xb[150]
    DIRECTION OUTPUT ;
    USE SIGNAL ;
    PORT
      LAYER M3 ;
        RECT  66.132 30.096 66.15 30.24 ;
    END
  END xb[150]
  PIN xb[151]
    DIRECTION OUTPUT ;
    USE SIGNAL ;
    PORT
      LAYER M5 ;
        RECT  66.288 30.048 66.312 30.24 ;
    END
  END xb[151]
  PIN xb[152]
    DIRECTION OUTPUT ;
    USE SIGNAL ;
    PORT
      LAYER M3 ;
        RECT  66.42 30.096 66.438 30.24 ;
    END
  END xb[152]
  PIN xb[153]
    DIRECTION OUTPUT ;
    USE SIGNAL ;
    PORT
      LAYER M5 ;
        RECT  66.576 30.048 66.6 30.24 ;
    END
  END xb[153]
  PIN xb[154]
    DIRECTION OUTPUT ;
    USE SIGNAL ;
    PORT
      LAYER M3 ;
        RECT  66.708 30.096 66.726 30.24 ;
    END
  END xb[154]
  PIN xb[155]
    DIRECTION OUTPUT ;
    USE SIGNAL ;
    PORT
      LAYER M5 ;
        RECT  66.816 30.048 66.84 30.24 ;
    END
  END xb[155]
  PIN xb[156]
    DIRECTION OUTPUT ;
    USE SIGNAL ;
    PORT
      LAYER M3 ;
        RECT  66.96 30.096 66.978 30.24 ;
    END
  END xb[156]
  PIN xb[157]
    DIRECTION OUTPUT ;
    USE SIGNAL ;
    PORT
      LAYER M5 ;
        RECT  67.104 30.048 67.128 30.24 ;
    END
  END xb[157]
  PIN xb[158]
    DIRECTION OUTPUT ;
    USE SIGNAL ;
    PORT
      LAYER M3 ;
        RECT  67.248 30.096 67.266 30.24 ;
    END
  END xb[158]
  PIN xb[159]
    DIRECTION OUTPUT ;
    USE SIGNAL ;
    PORT
      LAYER M5 ;
        RECT  67.392 30.048 67.416 30.24 ;
    END
  END xb[159]
  PIN xb[15]
    DIRECTION OUTPUT ;
    USE SIGNAL ;
    PORT
      LAYER M5 ;
        RECT  47.52 30.048 47.544 30.24 ;
    END
  END xb[15]
  PIN xb[160]
    DIRECTION OUTPUT ;
    USE SIGNAL ;
    PORT
      LAYER M3 ;
        RECT  67.536 30.096 67.554 30.24 ;
    END
  END xb[160]
  PIN xb[161]
    DIRECTION OUTPUT ;
    USE SIGNAL ;
    PORT
      LAYER M5 ;
        RECT  67.68 30.048 67.704 30.24 ;
    END
  END xb[161]
  PIN xb[162]
    DIRECTION OUTPUT ;
    USE SIGNAL ;
    PORT
      LAYER M3 ;
        RECT  67.788 30.096 67.806 30.24 ;
    END
  END xb[162]
  PIN xb[163]
    DIRECTION OUTPUT ;
    USE SIGNAL ;
    PORT
      LAYER M5 ;
        RECT  67.92 30.048 67.944 30.24 ;
    END
  END xb[163]
  PIN xb[164]
    DIRECTION OUTPUT ;
    USE SIGNAL ;
    PORT
      LAYER M3 ;
        RECT  68.076 30.096 68.094 30.24 ;
    END
  END xb[164]
  PIN xb[165]
    DIRECTION OUTPUT ;
    USE SIGNAL ;
    PORT
      LAYER M5 ;
        RECT  68.208 30.048 68.232 30.24 ;
    END
  END xb[165]
  PIN xb[166]
    DIRECTION OUTPUT ;
    USE SIGNAL ;
    PORT
      LAYER M3 ;
        RECT  68.364 30.096 68.382 30.24 ;
    END
  END xb[166]
  PIN xb[167]
    DIRECTION OUTPUT ;
    USE SIGNAL ;
    PORT
      LAYER M5 ;
        RECT  68.496 30.048 68.52 30.24 ;
    END
  END xb[167]
  PIN xb[168]
    DIRECTION OUTPUT ;
    USE SIGNAL ;
    PORT
      LAYER M3 ;
        RECT  68.616 30.096 68.634 30.24 ;
    END
  END xb[168]
  PIN xb[169]
    DIRECTION OUTPUT ;
    USE SIGNAL ;
    PORT
      LAYER M5 ;
        RECT  68.784 30.048 68.808 30.24 ;
    END
  END xb[169]
  PIN xb[16]
    DIRECTION OUTPUT ;
    USE SIGNAL ;
    PORT
      LAYER M3 ;
        RECT  47.664 30.096 47.682 30.24 ;
    END
  END xb[16]
  PIN xb[170]
    DIRECTION OUTPUT ;
    USE SIGNAL ;
    PORT
      LAYER M3 ;
        RECT  68.904 30.096 68.922 30.24 ;
    END
  END xb[170]
  PIN xb[171]
    DIRECTION OUTPUT ;
    USE SIGNAL ;
    PORT
      LAYER M5 ;
        RECT  69.024 30.048 69.048 30.24 ;
    END
  END xb[171]
  PIN xb[172]
    DIRECTION OUTPUT ;
    USE SIGNAL ;
    PORT
      LAYER M3 ;
        RECT  69.192 30.096 69.21 30.24 ;
    END
  END xb[172]
  PIN xb[173]
    DIRECTION OUTPUT ;
    USE SIGNAL ;
    PORT
      LAYER M5 ;
        RECT  69.312 30.048 69.336 30.24 ;
    END
  END xb[173]
  PIN xb[174]
    DIRECTION OUTPUT ;
    USE SIGNAL ;
    PORT
      LAYER M3 ;
        RECT  69.444 30.096 69.462 30.24 ;
    END
  END xb[174]
  PIN xb[175]
    DIRECTION OUTPUT ;
    USE SIGNAL ;
    PORT
      LAYER M5 ;
        RECT  69.6 30.048 69.624 30.24 ;
    END
  END xb[175]
  PIN xb[176]
    DIRECTION OUTPUT ;
    USE SIGNAL ;
    PORT
      LAYER M3 ;
        RECT  69.732 30.096 69.75 30.24 ;
    END
  END xb[176]
  PIN xb[177]
    DIRECTION OUTPUT ;
    USE SIGNAL ;
    PORT
      LAYER M5 ;
        RECT  69.888 30.048 69.912 30.24 ;
    END
  END xb[177]
  PIN xb[178]
    DIRECTION OUTPUT ;
    USE SIGNAL ;
    PORT
      LAYER M3 ;
        RECT  70.02 30.096 70.038 30.24 ;
    END
  END xb[178]
  PIN xb[179]
    DIRECTION OUTPUT ;
    USE SIGNAL ;
    PORT
      LAYER M5 ;
        RECT  70.128 30.048 70.152 30.24 ;
    END
  END xb[179]
  PIN xb[17]
    DIRECTION OUTPUT ;
    USE SIGNAL ;
    PORT
      LAYER M5 ;
        RECT  47.808 30.048 47.832 30.24 ;
    END
  END xb[17]
  PIN xb[180]
    DIRECTION OUTPUT ;
    USE SIGNAL ;
    PORT
      LAYER M3 ;
        RECT  70.272 30.096 70.29 30.24 ;
    END
  END xb[180]
  PIN xb[181]
    DIRECTION OUTPUT ;
    USE SIGNAL ;
    PORT
      LAYER M5 ;
        RECT  70.416 30.048 70.44 30.24 ;
    END
  END xb[181]
  PIN xb[182]
    DIRECTION OUTPUT ;
    USE SIGNAL ;
    PORT
      LAYER M3 ;
        RECT  70.56 30.096 70.578 30.24 ;
    END
  END xb[182]
  PIN xb[183]
    DIRECTION OUTPUT ;
    USE SIGNAL ;
    PORT
      LAYER M5 ;
        RECT  70.704 30.048 70.728 30.24 ;
    END
  END xb[183]
  PIN xb[184]
    DIRECTION OUTPUT ;
    USE SIGNAL ;
    PORT
      LAYER M3 ;
        RECT  70.848 30.096 70.866 30.24 ;
    END
  END xb[184]
  PIN xb[185]
    DIRECTION OUTPUT ;
    USE SIGNAL ;
    PORT
      LAYER M5 ;
        RECT  70.992 30.048 71.016 30.24 ;
    END
  END xb[185]
  PIN xb[186]
    DIRECTION OUTPUT ;
    USE SIGNAL ;
    PORT
      LAYER M3 ;
        RECT  71.1 30.096 71.118 30.24 ;
    END
  END xb[186]
  PIN xb[187]
    DIRECTION OUTPUT ;
    USE SIGNAL ;
    PORT
      LAYER M5 ;
        RECT  71.232 30.048 71.256 30.24 ;
    END
  END xb[187]
  PIN xb[188]
    DIRECTION OUTPUT ;
    USE SIGNAL ;
    PORT
      LAYER M3 ;
        RECT  71.388 30.096 71.406 30.24 ;
    END
  END xb[188]
  PIN xb[189]
    DIRECTION OUTPUT ;
    USE SIGNAL ;
    PORT
      LAYER M5 ;
        RECT  71.52 30.048 71.544 30.24 ;
    END
  END xb[189]
  PIN xb[18]
    DIRECTION OUTPUT ;
    USE SIGNAL ;
    PORT
      LAYER M3 ;
        RECT  47.952 30.096 47.97 30.24 ;
    END
  END xb[18]
  PIN xb[190]
    DIRECTION OUTPUT ;
    USE SIGNAL ;
    PORT
      LAYER M3 ;
        RECT  71.676 30.096 71.694 30.24 ;
    END
  END xb[190]
  PIN xb[191]
    DIRECTION OUTPUT ;
    USE SIGNAL ;
    PORT
      LAYER M5 ;
        RECT  71.808 30.048 71.832 30.24 ;
    END
  END xb[191]
  PIN xb[192]
    DIRECTION OUTPUT ;
    USE SIGNAL ;
    PORT
      LAYER M3 ;
        RECT  71.928 30.096 71.946 30.24 ;
    END
  END xb[192]
  PIN xb[193]
    DIRECTION OUTPUT ;
    USE SIGNAL ;
    PORT
      LAYER M5 ;
        RECT  72.096 30.048 72.12 30.24 ;
    END
  END xb[193]
  PIN xb[194]
    DIRECTION OUTPUT ;
    USE SIGNAL ;
    PORT
      LAYER M3 ;
        RECT  72.216 30.096 72.234 30.24 ;
    END
  END xb[194]
  PIN xb[195]
    DIRECTION OUTPUT ;
    USE SIGNAL ;
    PORT
      LAYER M5 ;
        RECT  72.336 30.048 72.36 30.24 ;
    END
  END xb[195]
  PIN xb[196]
    DIRECTION OUTPUT ;
    USE SIGNAL ;
    PORT
      LAYER M3 ;
        RECT  72.504 30.096 72.522 30.24 ;
    END
  END xb[196]
  PIN xb[197]
    DIRECTION OUTPUT ;
    USE SIGNAL ;
    PORT
      LAYER M5 ;
        RECT  72.624 30.048 72.648 30.24 ;
    END
  END xb[197]
  PIN xb[198]
    DIRECTION OUTPUT ;
    USE SIGNAL ;
    PORT
      LAYER M3 ;
        RECT  72.756 30.096 72.774 30.24 ;
    END
  END xb[198]
  PIN xb[199]
    DIRECTION OUTPUT ;
    USE SIGNAL ;
    PORT
      LAYER M5 ;
        RECT  72.912 30.048 72.936 30.24 ;
    END
  END xb[199]
  PIN xb[19]
    DIRECTION OUTPUT ;
    USE SIGNAL ;
    PORT
      LAYER M5 ;
        RECT  48.096 30.048 48.12 30.24 ;
    END
  END xb[19]
  PIN xb[1]
    DIRECTION OUTPUT ;
    USE SIGNAL ;
    PORT
      LAYER M5 ;
        RECT  45.6 30.048 45.624 30.24 ;
    END
  END xb[1]
  PIN xb[200]
    DIRECTION OUTPUT ;
    USE SIGNAL ;
    PORT
      LAYER M3 ;
        RECT  73.044 30.096 73.062 30.24 ;
    END
  END xb[200]
  PIN xb[201]
    DIRECTION OUTPUT ;
    USE SIGNAL ;
    PORT
      LAYER M5 ;
        RECT  73.152 30.048 73.176 30.24 ;
    END
  END xb[201]
  PIN xb[202]
    DIRECTION OUTPUT ;
    USE SIGNAL ;
    PORT
      LAYER M3 ;
        RECT  73.332 30.096 73.35 30.24 ;
    END
  END xb[202]
  PIN xb[203]
    DIRECTION OUTPUT ;
    USE SIGNAL ;
    PORT
      LAYER M5 ;
        RECT  73.44 30.048 73.464 30.24 ;
    END
  END xb[203]
  PIN xb[204]
    DIRECTION OUTPUT ;
    USE SIGNAL ;
    PORT
      LAYER M3 ;
        RECT  73.584 30.096 73.602 30.24 ;
    END
  END xb[204]
  PIN xb[205]
    DIRECTION OUTPUT ;
    USE SIGNAL ;
    PORT
      LAYER M5 ;
        RECT  73.728 30.048 73.752 30.24 ;
    END
  END xb[205]
  PIN xb[206]
    DIRECTION OUTPUT ;
    USE SIGNAL ;
    PORT
      LAYER M3 ;
        RECT  73.872 30.096 73.89 30.24 ;
    END
  END xb[206]
  PIN xb[207]
    DIRECTION OUTPUT ;
    USE SIGNAL ;
    PORT
      LAYER M5 ;
        RECT  74.016 30.048 74.04 30.24 ;
    END
  END xb[207]
  PIN xb[208]
    DIRECTION OUTPUT ;
    USE SIGNAL ;
    PORT
      LAYER M3 ;
        RECT  74.16 30.096 74.178 30.24 ;
    END
  END xb[208]
  PIN xb[209]
    DIRECTION OUTPUT ;
    USE SIGNAL ;
    PORT
      LAYER M5 ;
        RECT  74.256 30.048 74.28 30.24 ;
    END
  END xb[209]
  PIN xb[20]
    DIRECTION OUTPUT ;
    USE SIGNAL ;
    PORT
      LAYER M3 ;
        RECT  48.24 30.096 48.258 30.24 ;
    END
  END xb[20]
  PIN xb[210]
    DIRECTION OUTPUT ;
    USE SIGNAL ;
    PORT
      LAYER M3 ;
        RECT  74.412 30.096 74.43 30.24 ;
    END
  END xb[210]
  PIN xb[211]
    DIRECTION OUTPUT ;
    USE SIGNAL ;
    PORT
      LAYER M5 ;
        RECT  74.544 30.048 74.568 30.24 ;
    END
  END xb[211]
  PIN xb[212]
    DIRECTION OUTPUT ;
    USE SIGNAL ;
    PORT
      LAYER M3 ;
        RECT  74.7 30.096 74.718 30.24 ;
    END
  END xb[212]
  PIN xb[213]
    DIRECTION OUTPUT ;
    USE SIGNAL ;
    PORT
      LAYER M5 ;
        RECT  74.832 30.048 74.856 30.24 ;
    END
  END xb[213]
  PIN xb[214]
    DIRECTION OUTPUT ;
    USE SIGNAL ;
    PORT
      LAYER M3 ;
        RECT  74.988 30.096 75.006 30.24 ;
    END
  END xb[214]
  PIN xb[215]
    DIRECTION OUTPUT ;
    USE SIGNAL ;
    PORT
      LAYER M5 ;
        RECT  75.12 30.048 75.144 30.24 ;
    END
  END xb[215]
  PIN xb[216]
    DIRECTION OUTPUT ;
    USE SIGNAL ;
    PORT
      LAYER M3 ;
        RECT  75.24 30.096 75.258 30.24 ;
    END
  END xb[216]
  PIN xb[217]
    DIRECTION OUTPUT ;
    USE SIGNAL ;
    PORT
      LAYER M5 ;
        RECT  75.36 30.048 75.384 30.24 ;
    END
  END xb[217]
  PIN xb[218]
    DIRECTION OUTPUT ;
    USE SIGNAL ;
    PORT
      LAYER M3 ;
        RECT  75.528 30.096 75.546 30.24 ;
    END
  END xb[218]
  PIN xb[219]
    DIRECTION OUTPUT ;
    USE SIGNAL ;
    PORT
      LAYER M5 ;
        RECT  75.648 30.048 75.672 30.24 ;
    END
  END xb[219]
  PIN xb[21]
    DIRECTION OUTPUT ;
    USE SIGNAL ;
    PORT
      LAYER M5 ;
        RECT  48.336 30.048 48.36 30.24 ;
    END
  END xb[21]
  PIN xb[220]
    DIRECTION OUTPUT ;
    USE SIGNAL ;
    PORT
      LAYER M3 ;
        RECT  75.78 30.096 75.798 30.24 ;
    END
  END xb[220]
  PIN xb[221]
    DIRECTION OUTPUT ;
    USE SIGNAL ;
    PORT
      LAYER M5 ;
        RECT  75.936 30.048 75.96 30.24 ;
    END
  END xb[221]
  PIN xb[222]
    DIRECTION OUTPUT ;
    USE SIGNAL ;
    PORT
      LAYER M3 ;
        RECT  76.068 30.096 76.086 30.24 ;
    END
  END xb[222]
  PIN xb[223]
    DIRECTION OUTPUT ;
    USE SIGNAL ;
    PORT
      LAYER M5 ;
        RECT  76.224 30.048 76.248 30.24 ;
    END
  END xb[223]
  PIN xb[224]
    DIRECTION OUTPUT ;
    USE SIGNAL ;
    PORT
      LAYER M3 ;
        RECT  76.356 30.096 76.374 30.24 ;
    END
  END xb[224]
  PIN xb[225]
    DIRECTION OUTPUT ;
    USE SIGNAL ;
    PORT
      LAYER M5 ;
        RECT  76.464 30.048 76.488 30.24 ;
    END
  END xb[225]
  PIN xb[226]
    DIRECTION OUTPUT ;
    USE SIGNAL ;
    PORT
      LAYER M3 ;
        RECT  76.608 30.096 76.626 30.24 ;
    END
  END xb[226]
  PIN xb[227]
    DIRECTION OUTPUT ;
    USE SIGNAL ;
    PORT
      LAYER M5 ;
        RECT  76.752 30.048 76.776 30.24 ;
    END
  END xb[227]
  PIN xb[228]
    DIRECTION OUTPUT ;
    USE SIGNAL ;
    PORT
      LAYER M3 ;
        RECT  76.896 30.096 76.914 30.24 ;
    END
  END xb[228]
  PIN xb[229]
    DIRECTION OUTPUT ;
    USE SIGNAL ;
    PORT
      LAYER M5 ;
        RECT  77.04 30.048 77.064 30.24 ;
    END
  END xb[229]
  PIN xb[22]
    DIRECTION OUTPUT ;
    USE SIGNAL ;
    PORT
      LAYER M3 ;
        RECT  48.492 30.096 48.51 30.24 ;
    END
  END xb[22]
  PIN xb[230]
    DIRECTION OUTPUT ;
    USE SIGNAL ;
    PORT
      LAYER M3 ;
        RECT  77.184 30.096 77.202 30.24 ;
    END
  END xb[230]
  PIN xb[231]
    DIRECTION OUTPUT ;
    USE SIGNAL ;
    PORT
      LAYER M5 ;
        RECT  77.328 30.048 77.352 30.24 ;
    END
  END xb[231]
  PIN xb[232]
    DIRECTION OUTPUT ;
    USE SIGNAL ;
    PORT
      LAYER M3 ;
        RECT  77.436 30.096 77.454 30.24 ;
    END
  END xb[232]
  PIN xb[233]
    DIRECTION OUTPUT ;
    USE SIGNAL ;
    PORT
      LAYER M5 ;
        RECT  77.568 30.048 77.592 30.24 ;
    END
  END xb[233]
  PIN xb[234]
    DIRECTION OUTPUT ;
    USE SIGNAL ;
    PORT
      LAYER M3 ;
        RECT  77.724 30.096 77.742 30.24 ;
    END
  END xb[234]
  PIN xb[235]
    DIRECTION OUTPUT ;
    USE SIGNAL ;
    PORT
      LAYER M5 ;
        RECT  77.856 30.048 77.88 30.24 ;
    END
  END xb[235]
  PIN xb[236]
    DIRECTION OUTPUT ;
    USE SIGNAL ;
    PORT
      LAYER M3 ;
        RECT  78.012 30.096 78.03 30.24 ;
    END
  END xb[236]
  PIN xb[237]
    DIRECTION OUTPUT ;
    USE SIGNAL ;
    PORT
      LAYER M5 ;
        RECT  78.144 30.048 78.168 30.24 ;
    END
  END xb[237]
  PIN xb[238]
    DIRECTION OUTPUT ;
    USE SIGNAL ;
    PORT
      LAYER M3 ;
        RECT  78.264 30.096 78.282 30.24 ;
    END
  END xb[238]
  PIN xb[239]
    DIRECTION OUTPUT ;
    USE SIGNAL ;
    PORT
      LAYER M5 ;
        RECT  78.432 30.048 78.456 30.24 ;
    END
  END xb[239]
  PIN xb[23]
    DIRECTION OUTPUT ;
    USE SIGNAL ;
    PORT
      LAYER M5 ;
        RECT  48.624 30.048 48.648 30.24 ;
    END
  END xb[23]
  PIN xb[240]
    DIRECTION OUTPUT ;
    USE SIGNAL ;
    PORT
      LAYER M3 ;
        RECT  78.552 30.096 78.57 30.24 ;
    END
  END xb[240]
  PIN xb[241]
    DIRECTION OUTPUT ;
    USE SIGNAL ;
    PORT
      LAYER M5 ;
        RECT  78.672 30.048 78.696 30.24 ;
    END
  END xb[241]
  PIN xb[242]
    DIRECTION OUTPUT ;
    USE SIGNAL ;
    PORT
      LAYER M3 ;
        RECT  78.84 30.096 78.858 30.24 ;
    END
  END xb[242]
  PIN xb[243]
    DIRECTION OUTPUT ;
    USE SIGNAL ;
    PORT
      LAYER M5 ;
        RECT  78.96 30.048 78.984 30.24 ;
    END
  END xb[243]
  PIN xb[244]
    DIRECTION OUTPUT ;
    USE SIGNAL ;
    PORT
      LAYER M3 ;
        RECT  79.092 30.096 79.11 30.24 ;
    END
  END xb[244]
  PIN xb[245]
    DIRECTION OUTPUT ;
    USE SIGNAL ;
    PORT
      LAYER M5 ;
        RECT  79.248 30.048 79.272 30.24 ;
    END
  END xb[245]
  PIN xb[246]
    DIRECTION OUTPUT ;
    USE SIGNAL ;
    PORT
      LAYER M3 ;
        RECT  79.38 30.096 79.398 30.24 ;
    END
  END xb[246]
  PIN xb[247]
    DIRECTION OUTPUT ;
    USE SIGNAL ;
    PORT
      LAYER M5 ;
        RECT  79.536 30.048 79.56 30.24 ;
    END
  END xb[247]
  PIN xb[248]
    DIRECTION OUTPUT ;
    USE SIGNAL ;
    PORT
      LAYER M3 ;
        RECT  79.668 30.096 79.686 30.24 ;
    END
  END xb[248]
  PIN xb[249]
    DIRECTION OUTPUT ;
    USE SIGNAL ;
    PORT
      LAYER M5 ;
        RECT  79.776 30.048 79.8 30.24 ;
    END
  END xb[249]
  PIN xb[24]
    DIRECTION OUTPUT ;
    USE SIGNAL ;
    PORT
      LAYER M3 ;
        RECT  48.78 30.096 48.798 30.24 ;
    END
  END xb[24]
  PIN xb[250]
    DIRECTION OUTPUT ;
    USE SIGNAL ;
    PORT
      LAYER M3 ;
        RECT  79.92 30.096 79.938 30.24 ;
    END
  END xb[250]
  PIN xb[251]
    DIRECTION OUTPUT ;
    USE SIGNAL ;
    PORT
      LAYER M5 ;
        RECT  80.064 30.048 80.088 30.24 ;
    END
  END xb[251]
  PIN xb[252]
    DIRECTION OUTPUT ;
    USE SIGNAL ;
    PORT
      LAYER M3 ;
        RECT  80.208 30.096 80.226 30.24 ;
    END
  END xb[252]
  PIN xb[253]
    DIRECTION OUTPUT ;
    USE SIGNAL ;
    PORT
      LAYER M5 ;
        RECT  80.352 30.048 80.376 30.24 ;
    END
  END xb[253]
  PIN xb[254]
    DIRECTION OUTPUT ;
    USE SIGNAL ;
    PORT
      LAYER M3 ;
        RECT  80.496 30.096 80.514 30.24 ;
    END
  END xb[254]
  PIN xb[255]
    DIRECTION OUTPUT ;
    USE SIGNAL ;
    PORT
      LAYER M5 ;
        RECT  80.64 30.048 80.664 30.24 ;
    END
  END xb[255]
  PIN xb[256]
    DIRECTION OUTPUT ;
    USE SIGNAL ;
    PORT
      LAYER M3 ;
        RECT  80.748 30.096 80.766 30.24 ;
    END
  END xb[256]
  PIN xb[257]
    DIRECTION OUTPUT ;
    USE SIGNAL ;
    PORT
      LAYER M5 ;
        RECT  80.88 30.048 80.904 30.24 ;
    END
  END xb[257]
  PIN xb[258]
    DIRECTION OUTPUT ;
    USE SIGNAL ;
    PORT
      LAYER M3 ;
        RECT  81.036 30.096 81.054 30.24 ;
    END
  END xb[258]
  PIN xb[259]
    DIRECTION OUTPUT ;
    USE SIGNAL ;
    PORT
      LAYER M5 ;
        RECT  81.168 30.048 81.192 30.24 ;
    END
  END xb[259]
  PIN xb[25]
    DIRECTION OUTPUT ;
    USE SIGNAL ;
    PORT
      LAYER M5 ;
        RECT  48.912 30.048 48.936 30.24 ;
    END
  END xb[25]
  PIN xb[260]
    DIRECTION OUTPUT ;
    USE SIGNAL ;
    PORT
      LAYER M3 ;
        RECT  81.324 30.096 81.342 30.24 ;
    END
  END xb[260]
  PIN xb[261]
    DIRECTION OUTPUT ;
    USE SIGNAL ;
    PORT
      LAYER M5 ;
        RECT  81.456 30.048 81.48 30.24 ;
    END
  END xb[261]
  PIN xb[262]
    DIRECTION OUTPUT ;
    USE SIGNAL ;
    PORT
      LAYER M3 ;
        RECT  81.576 30.096 81.594 30.24 ;
    END
  END xb[262]
  PIN xb[263]
    DIRECTION OUTPUT ;
    USE SIGNAL ;
    PORT
      LAYER M5 ;
        RECT  81.744 30.048 81.768 30.24 ;
    END
  END xb[263]
  PIN xb[264]
    DIRECTION OUTPUT ;
    USE SIGNAL ;
    PORT
      LAYER M3 ;
        RECT  81.864 30.096 81.882 30.24 ;
    END
  END xb[264]
  PIN xb[265]
    DIRECTION OUTPUT ;
    USE SIGNAL ;
    PORT
      LAYER M5 ;
        RECT  81.984 30.048 82.008 30.24 ;
    END
  END xb[265]
  PIN xb[26]
    DIRECTION OUTPUT ;
    USE SIGNAL ;
    PORT
      LAYER M3 ;
        RECT  49.068 30.096 49.086 30.24 ;
    END
  END xb[26]
  PIN xb[27]
    DIRECTION OUTPUT ;
    USE SIGNAL ;
    PORT
      LAYER M5 ;
        RECT  49.2 30.048 49.224 30.24 ;
    END
  END xb[27]
  PIN xb[28]
    DIRECTION OUTPUT ;
    USE SIGNAL ;
    PORT
      LAYER M3 ;
        RECT  49.32 30.096 49.338 30.24 ;
    END
  END xb[28]
  PIN xb[29]
    DIRECTION OUTPUT ;
    USE SIGNAL ;
    PORT
      LAYER M5 ;
        RECT  49.44 30.048 49.464 30.24 ;
    END
  END xb[29]
  PIN xb[2]
    DIRECTION OUTPUT ;
    USE SIGNAL ;
    PORT
      LAYER M3 ;
        RECT  45.756 30.096 45.774 30.24 ;
    END
  END xb[2]
  PIN xb[30]
    DIRECTION OUTPUT ;
    USE SIGNAL ;
    PORT
      LAYER M3 ;
        RECT  49.608 30.096 49.626 30.24 ;
    END
  END xb[30]
  PIN xb[31]
    DIRECTION OUTPUT ;
    USE SIGNAL ;
    PORT
      LAYER M5 ;
        RECT  49.728 30.048 49.752 30.24 ;
    END
  END xb[31]
  PIN xb[32]
    DIRECTION OUTPUT ;
    USE SIGNAL ;
    PORT
      LAYER M3 ;
        RECT  49.86 30.096 49.878 30.24 ;
    END
  END xb[32]
  PIN xb[33]
    DIRECTION OUTPUT ;
    USE SIGNAL ;
    PORT
      LAYER M5 ;
        RECT  50.016 30.048 50.04 30.24 ;
    END
  END xb[33]
  PIN xb[34]
    DIRECTION OUTPUT ;
    USE SIGNAL ;
    PORT
      LAYER M3 ;
        RECT  50.148 30.096 50.166 30.24 ;
    END
  END xb[34]
  PIN xb[35]
    DIRECTION OUTPUT ;
    USE SIGNAL ;
    PORT
      LAYER M5 ;
        RECT  50.304 30.048 50.328 30.24 ;
    END
  END xb[35]
  PIN xb[36]
    DIRECTION OUTPUT ;
    USE SIGNAL ;
    PORT
      LAYER M3 ;
        RECT  50.436 30.096 50.454 30.24 ;
    END
  END xb[36]
  PIN xb[37]
    DIRECTION OUTPUT ;
    USE SIGNAL ;
    PORT
      LAYER M5 ;
        RECT  50.544 30.048 50.568 30.24 ;
    END
  END xb[37]
  PIN xb[38]
    DIRECTION OUTPUT ;
    USE SIGNAL ;
    PORT
      LAYER M3 ;
        RECT  50.688 30.096 50.706 30.24 ;
    END
  END xb[38]
  PIN xb[39]
    DIRECTION OUTPUT ;
    USE SIGNAL ;
    PORT
      LAYER M5 ;
        RECT  50.832 30.048 50.856 30.24 ;
    END
  END xb[39]
  PIN xb[3]
    DIRECTION OUTPUT ;
    USE SIGNAL ;
    PORT
      LAYER M5 ;
        RECT  45.888 30.048 45.912 30.24 ;
    END
  END xb[3]
  PIN xb[40]
    DIRECTION OUTPUT ;
    USE SIGNAL ;
    PORT
      LAYER M3 ;
        RECT  50.976 30.096 50.994 30.24 ;
    END
  END xb[40]
  PIN xb[41]
    DIRECTION OUTPUT ;
    USE SIGNAL ;
    PORT
      LAYER M5 ;
        RECT  51.12 30.048 51.144 30.24 ;
    END
  END xb[41]
  PIN xb[42]
    DIRECTION OUTPUT ;
    USE SIGNAL ;
    PORT
      LAYER M3 ;
        RECT  51.264 30.096 51.282 30.24 ;
    END
  END xb[42]
  PIN xb[43]
    DIRECTION OUTPUT ;
    USE SIGNAL ;
    PORT
      LAYER M5 ;
        RECT  51.408 30.048 51.432 30.24 ;
    END
  END xb[43]
  PIN xb[44]
    DIRECTION OUTPUT ;
    USE SIGNAL ;
    PORT
      LAYER M3 ;
        RECT  51.516 30.096 51.534 30.24 ;
    END
  END xb[44]
  PIN xb[45]
    DIRECTION OUTPUT ;
    USE SIGNAL ;
    PORT
      LAYER M5 ;
        RECT  51.648 30.048 51.672 30.24 ;
    END
  END xb[45]
  PIN xb[46]
    DIRECTION OUTPUT ;
    USE SIGNAL ;
    PORT
      LAYER M3 ;
        RECT  51.804 30.096 51.822 30.24 ;
    END
  END xb[46]
  PIN xb[47]
    DIRECTION OUTPUT ;
    USE SIGNAL ;
    PORT
      LAYER M5 ;
        RECT  51.936 30.048 51.96 30.24 ;
    END
  END xb[47]
  PIN xb[48]
    DIRECTION OUTPUT ;
    USE SIGNAL ;
    PORT
      LAYER M3 ;
        RECT  52.092 30.096 52.11 30.24 ;
    END
  END xb[48]
  PIN xb[49]
    DIRECTION OUTPUT ;
    USE SIGNAL ;
    PORT
      LAYER M5 ;
        RECT  52.224 30.048 52.248 30.24 ;
    END
  END xb[49]
  PIN xb[4]
    DIRECTION OUTPUT ;
    USE SIGNAL ;
    PORT
      LAYER M3 ;
        RECT  46.008 30.096 46.026 30.24 ;
    END
  END xb[4]
  PIN xb[50]
    DIRECTION OUTPUT ;
    USE SIGNAL ;
    PORT
      LAYER M3 ;
        RECT  52.344 30.096 52.362 30.24 ;
    END
  END xb[50]
  PIN xb[51]
    DIRECTION OUTPUT ;
    USE SIGNAL ;
    PORT
      LAYER M5 ;
        RECT  52.512 30.048 52.536 30.24 ;
    END
  END xb[51]
  PIN xb[52]
    DIRECTION OUTPUT ;
    USE SIGNAL ;
    PORT
      LAYER M3 ;
        RECT  52.632 30.096 52.65 30.24 ;
    END
  END xb[52]
  PIN xb[53]
    DIRECTION OUTPUT ;
    USE SIGNAL ;
    PORT
      LAYER M5 ;
        RECT  52.752 30.048 52.776 30.24 ;
    END
  END xb[53]
  PIN xb[54]
    DIRECTION OUTPUT ;
    USE SIGNAL ;
    PORT
      LAYER M3 ;
        RECT  52.92 30.096 52.938 30.24 ;
    END
  END xb[54]
  PIN xb[55]
    DIRECTION OUTPUT ;
    USE SIGNAL ;
    PORT
      LAYER M5 ;
        RECT  53.04 30.048 53.064 30.24 ;
    END
  END xb[55]
  PIN xb[56]
    DIRECTION OUTPUT ;
    USE SIGNAL ;
    PORT
      LAYER M3 ;
        RECT  53.172 30.096 53.19 30.24 ;
    END
  END xb[56]
  PIN xb[57]
    DIRECTION OUTPUT ;
    USE SIGNAL ;
    PORT
      LAYER M5 ;
        RECT  53.328 30.048 53.352 30.24 ;
    END
  END xb[57]
  PIN xb[58]
    DIRECTION OUTPUT ;
    USE SIGNAL ;
    PORT
      LAYER M3 ;
        RECT  53.46 30.096 53.478 30.24 ;
    END
  END xb[58]
  PIN xb[59]
    DIRECTION OUTPUT ;
    USE SIGNAL ;
    PORT
      LAYER M5 ;
        RECT  53.616 30.048 53.64 30.24 ;
    END
  END xb[59]
  PIN xb[5]
    DIRECTION OUTPUT ;
    USE SIGNAL ;
    PORT
      LAYER M5 ;
        RECT  46.176 30.048 46.2 30.24 ;
    END
  END xb[5]
  PIN xb[60]
    DIRECTION OUTPUT ;
    USE SIGNAL ;
    PORT
      LAYER M3 ;
        RECT  53.748 30.096 53.766 30.24 ;
    END
  END xb[60]
  PIN xb[61]
    DIRECTION OUTPUT ;
    USE SIGNAL ;
    PORT
      LAYER M5 ;
        RECT  53.856 30.048 53.88 30.24 ;
    END
  END xb[61]
  PIN xb[62]
    DIRECTION OUTPUT ;
    USE SIGNAL ;
    PORT
      LAYER M3 ;
        RECT  54 30.096 54.018 30.24 ;
    END
  END xb[62]
  PIN xb[63]
    DIRECTION OUTPUT ;
    USE SIGNAL ;
    PORT
      LAYER M5 ;
        RECT  54.144 30.048 54.168 30.24 ;
    END
  END xb[63]
  PIN xb[64]
    DIRECTION OUTPUT ;
    USE SIGNAL ;
    PORT
      LAYER M3 ;
        RECT  54.288 30.096 54.306 30.24 ;
    END
  END xb[64]
  PIN xb[65]
    DIRECTION OUTPUT ;
    USE SIGNAL ;
    PORT
      LAYER M5 ;
        RECT  54.432 30.048 54.456 30.24 ;
    END
  END xb[65]
  PIN xb[66]
    DIRECTION OUTPUT ;
    USE SIGNAL ;
    PORT
      LAYER M3 ;
        RECT  54.576 30.096 54.594 30.24 ;
    END
  END xb[66]
  PIN xb[67]
    DIRECTION OUTPUT ;
    USE SIGNAL ;
    PORT
      LAYER M5 ;
        RECT  54.72 30.048 54.744 30.24 ;
    END
  END xb[67]
  PIN xb[68]
    DIRECTION OUTPUT ;
    USE SIGNAL ;
    PORT
      LAYER M3 ;
        RECT  54.828 30.096 54.846 30.24 ;
    END
  END xb[68]
  PIN xb[69]
    DIRECTION OUTPUT ;
    USE SIGNAL ;
    PORT
      LAYER M5 ;
        RECT  54.96 30.048 54.984 30.24 ;
    END
  END xb[69]
  PIN xb[6]
    DIRECTION OUTPUT ;
    USE SIGNAL ;
    PORT
      LAYER M3 ;
        RECT  46.296 30.096 46.314 30.24 ;
    END
  END xb[6]
  PIN xb[70]
    DIRECTION OUTPUT ;
    USE SIGNAL ;
    PORT
      LAYER M3 ;
        RECT  55.116 30.096 55.134 30.24 ;
    END
  END xb[70]
  PIN xb[71]
    DIRECTION OUTPUT ;
    USE SIGNAL ;
    PORT
      LAYER M5 ;
        RECT  55.248 30.048 55.272 30.24 ;
    END
  END xb[71]
  PIN xb[72]
    DIRECTION OUTPUT ;
    USE SIGNAL ;
    PORT
      LAYER M3 ;
        RECT  55.404 30.096 55.422 30.24 ;
    END
  END xb[72]
  PIN xb[73]
    DIRECTION OUTPUT ;
    USE SIGNAL ;
    PORT
      LAYER M5 ;
        RECT  55.536 30.048 55.56 30.24 ;
    END
  END xb[73]
  PIN xb[74]
    DIRECTION OUTPUT ;
    USE SIGNAL ;
    PORT
      LAYER M3 ;
        RECT  55.656 30.096 55.674 30.24 ;
    END
  END xb[74]
  PIN xb[75]
    DIRECTION OUTPUT ;
    USE SIGNAL ;
    PORT
      LAYER M5 ;
        RECT  55.824 30.048 55.848 30.24 ;
    END
  END xb[75]
  PIN xb[76]
    DIRECTION OUTPUT ;
    USE SIGNAL ;
    PORT
      LAYER M3 ;
        RECT  55.944 30.096 55.962 30.24 ;
    END
  END xb[76]
  PIN xb[77]
    DIRECTION OUTPUT ;
    USE SIGNAL ;
    PORT
      LAYER M5 ;
        RECT  56.064 30.048 56.088 30.24 ;
    END
  END xb[77]
  PIN xb[78]
    DIRECTION OUTPUT ;
    USE SIGNAL ;
    PORT
      LAYER M3 ;
        RECT  56.232 30.096 56.25 30.24 ;
    END
  END xb[78]
  PIN xb[79]
    DIRECTION OUTPUT ;
    USE SIGNAL ;
    PORT
      LAYER M5 ;
        RECT  56.352 30.048 56.376 30.24 ;
    END
  END xb[79]
  PIN xb[7]
    DIRECTION OUTPUT ;
    USE SIGNAL ;
    PORT
      LAYER M5 ;
        RECT  46.416 30.048 46.44 30.24 ;
    END
  END xb[7]
  PIN xb[80]
    DIRECTION OUTPUT ;
    USE SIGNAL ;
    PORT
      LAYER M3 ;
        RECT  56.484 30.096 56.502 30.24 ;
    END
  END xb[80]
  PIN xb[81]
    DIRECTION OUTPUT ;
    USE SIGNAL ;
    PORT
      LAYER M5 ;
        RECT  56.64 30.048 56.664 30.24 ;
    END
  END xb[81]
  PIN xb[82]
    DIRECTION OUTPUT ;
    USE SIGNAL ;
    PORT
      LAYER M3 ;
        RECT  56.772 30.096 56.79 30.24 ;
    END
  END xb[82]
  PIN xb[83]
    DIRECTION OUTPUT ;
    USE SIGNAL ;
    PORT
      LAYER M5 ;
        RECT  56.928 30.048 56.952 30.24 ;
    END
  END xb[83]
  PIN xb[84]
    DIRECTION OUTPUT ;
    USE SIGNAL ;
    PORT
      LAYER M3 ;
        RECT  57.06 30.096 57.078 30.24 ;
    END
  END xb[84]
  PIN xb[85]
    DIRECTION OUTPUT ;
    USE SIGNAL ;
    PORT
      LAYER M5 ;
        RECT  57.168 30.048 57.192 30.24 ;
    END
  END xb[85]
  PIN xb[86]
    DIRECTION OUTPUT ;
    USE SIGNAL ;
    PORT
      LAYER M3 ;
        RECT  57.312 30.096 57.33 30.24 ;
    END
  END xb[86]
  PIN xb[87]
    DIRECTION OUTPUT ;
    USE SIGNAL ;
    PORT
      LAYER M5 ;
        RECT  57.456 30.048 57.48 30.24 ;
    END
  END xb[87]
  PIN xb[88]
    DIRECTION OUTPUT ;
    USE SIGNAL ;
    PORT
      LAYER M3 ;
        RECT  57.6 30.096 57.618 30.24 ;
    END
  END xb[88]
  PIN xb[89]
    DIRECTION OUTPUT ;
    USE SIGNAL ;
    PORT
      LAYER M5 ;
        RECT  57.744 30.048 57.768 30.24 ;
    END
  END xb[89]
  PIN xb[8]
    DIRECTION OUTPUT ;
    USE SIGNAL ;
    PORT
      LAYER M3 ;
        RECT  46.584 30.096 46.602 30.24 ;
    END
  END xb[8]
  PIN xb[90]
    DIRECTION OUTPUT ;
    USE SIGNAL ;
    PORT
      LAYER M3 ;
        RECT  57.888 30.096 57.906 30.24 ;
    END
  END xb[90]
  PIN xb[91]
    DIRECTION OUTPUT ;
    USE SIGNAL ;
    PORT
      LAYER M5 ;
        RECT  58.032 30.048 58.056 30.24 ;
    END
  END xb[91]
  PIN xb[92]
    DIRECTION OUTPUT ;
    USE SIGNAL ;
    PORT
      LAYER M3 ;
        RECT  58.14 30.096 58.158 30.24 ;
    END
  END xb[92]
  PIN xb[93]
    DIRECTION OUTPUT ;
    USE SIGNAL ;
    PORT
      LAYER M5 ;
        RECT  58.272 30.048 58.296 30.24 ;
    END
  END xb[93]
  PIN xb[94]
    DIRECTION OUTPUT ;
    USE SIGNAL ;
    PORT
      LAYER M3 ;
        RECT  58.428 30.096 58.446 30.24 ;
    END
  END xb[94]
  PIN xb[95]
    DIRECTION OUTPUT ;
    USE SIGNAL ;
    PORT
      LAYER M5 ;
        RECT  58.56 30.048 58.584 30.24 ;
    END
  END xb[95]
  PIN xb[96]
    DIRECTION OUTPUT ;
    USE SIGNAL ;
    PORT
      LAYER M3 ;
        RECT  58.716 30.096 58.734 30.24 ;
    END
  END xb[96]
  PIN xb[97]
    DIRECTION OUTPUT ;
    USE SIGNAL ;
    PORT
      LAYER M5 ;
        RECT  58.848 30.048 58.872 30.24 ;
    END
  END xb[97]
  PIN xb[98]
    DIRECTION OUTPUT ;
    USE SIGNAL ;
    PORT
      LAYER M3 ;
        RECT  58.968 30.096 58.986 30.24 ;
    END
  END xb[98]
  PIN xb[99]
    DIRECTION OUTPUT ;
    USE SIGNAL ;
    PORT
      LAYER M5 ;
        RECT  59.136 30.048 59.16 30.24 ;
    END
  END xb[99]
  PIN xb[9]
    DIRECTION OUTPUT ;
    USE SIGNAL ;
    PORT
      LAYER M5 ;
        RECT  46.704 30.048 46.728 30.24 ;
    END
  END xb[9]
  PIN xbi[0]
    DIRECTION INPUT ;
    USE SIGNAL ;
    PORT
      LAYER M3 ;
        RECT  45.468 0 45.486 0.144 ;
    END
  END xbi[0]
  PIN xbi[100]
    DIRECTION INPUT ;
    USE SIGNAL ;
    PORT
      LAYER M3 ;
        RECT  59.256 0 59.274 0.144 ;
    END
  END xbi[100]
  PIN xbi[101]
    DIRECTION INPUT ;
    USE SIGNAL ;
    PORT
      LAYER M5 ;
        RECT  59.376 0 59.4 0.192 ;
    END
  END xbi[101]
  PIN xbi[102]
    DIRECTION INPUT ;
    USE SIGNAL ;
    PORT
      LAYER M3 ;
        RECT  59.544 0 59.562 0.144 ;
    END
  END xbi[102]
  PIN xbi[103]
    DIRECTION INPUT ;
    USE SIGNAL ;
    PORT
      LAYER M5 ;
        RECT  59.664 0 59.688 0.192 ;
    END
  END xbi[103]
  PIN xbi[104]
    DIRECTION INPUT ;
    USE SIGNAL ;
    PORT
      LAYER M3 ;
        RECT  59.796 0 59.814 0.144 ;
    END
  END xbi[104]
  PIN xbi[105]
    DIRECTION INPUT ;
    USE SIGNAL ;
    PORT
      LAYER M5 ;
        RECT  59.952 0 59.976 0.192 ;
    END
  END xbi[105]
  PIN xbi[106]
    DIRECTION INPUT ;
    USE SIGNAL ;
    PORT
      LAYER M3 ;
        RECT  60.084 0 60.102 0.144 ;
    END
  END xbi[106]
  PIN xbi[107]
    DIRECTION INPUT ;
    USE SIGNAL ;
    PORT
      LAYER M5 ;
        RECT  60.192 0 60.216 0.192 ;
    END
  END xbi[107]
  PIN xbi[108]
    DIRECTION INPUT ;
    USE SIGNAL ;
    PORT
      LAYER M3 ;
        RECT  60.372 0 60.39 0.144 ;
    END
  END xbi[108]
  PIN xbi[109]
    DIRECTION INPUT ;
    USE SIGNAL ;
    PORT
      LAYER M5 ;
        RECT  60.48 0 60.504 0.192 ;
    END
  END xbi[109]
  PIN xbi[10]
    DIRECTION INPUT ;
    USE SIGNAL ;
    PORT
      LAYER M3 ;
        RECT  46.836 0 46.854 0.144 ;
    END
  END xbi[10]
  PIN xbi[110]
    DIRECTION INPUT ;
    USE SIGNAL ;
    PORT
      LAYER M3 ;
        RECT  60.624 0 60.642 0.144 ;
    END
  END xbi[110]
  PIN xbi[111]
    DIRECTION INPUT ;
    USE SIGNAL ;
    PORT
      LAYER M5 ;
        RECT  60.768 0 60.792 0.192 ;
    END
  END xbi[111]
  PIN xbi[112]
    DIRECTION INPUT ;
    USE SIGNAL ;
    PORT
      LAYER M3 ;
        RECT  60.912 0 60.93 0.144 ;
    END
  END xbi[112]
  PIN xbi[113]
    DIRECTION INPUT ;
    USE SIGNAL ;
    PORT
      LAYER M5 ;
        RECT  61.056 0 61.08 0.192 ;
    END
  END xbi[113]
  PIN xbi[114]
    DIRECTION INPUT ;
    USE SIGNAL ;
    PORT
      LAYER M3 ;
        RECT  61.2 0 61.218 0.144 ;
    END
  END xbi[114]
  PIN xbi[115]
    DIRECTION INPUT ;
    USE SIGNAL ;
    PORT
      LAYER M5 ;
        RECT  61.296 0 61.32 0.192 ;
    END
  END xbi[115]
  PIN xbi[116]
    DIRECTION INPUT ;
    USE SIGNAL ;
    PORT
      LAYER M3 ;
        RECT  61.452 0 61.47 0.144 ;
    END
  END xbi[116]
  PIN xbi[117]
    DIRECTION INPUT ;
    USE SIGNAL ;
    PORT
      LAYER M5 ;
        RECT  61.584 0 61.608 0.192 ;
    END
  END xbi[117]
  PIN xbi[118]
    DIRECTION INPUT ;
    USE SIGNAL ;
    PORT
      LAYER M3 ;
        RECT  61.74 0 61.758 0.144 ;
    END
  END xbi[118]
  PIN xbi[119]
    DIRECTION INPUT ;
    USE SIGNAL ;
    PORT
      LAYER M5 ;
        RECT  61.872 0 61.896 0.192 ;
    END
  END xbi[119]
  PIN xbi[11]
    DIRECTION INPUT ;
    USE SIGNAL ;
    PORT
      LAYER M5 ;
        RECT  46.992 0 47.016 0.192 ;
    END
  END xbi[11]
  PIN xbi[120]
    DIRECTION INPUT ;
    USE SIGNAL ;
    PORT
      LAYER M3 ;
        RECT  62.028 0 62.046 0.144 ;
    END
  END xbi[120]
  PIN xbi[121]
    DIRECTION INPUT ;
    USE SIGNAL ;
    PORT
      LAYER M5 ;
        RECT  62.16 0 62.184 0.192 ;
    END
  END xbi[121]
  PIN xbi[122]
    DIRECTION INPUT ;
    USE SIGNAL ;
    PORT
      LAYER M3 ;
        RECT  62.28 0 62.298 0.144 ;
    END
  END xbi[122]
  PIN xbi[123]
    DIRECTION INPUT ;
    USE SIGNAL ;
    PORT
      LAYER M5 ;
        RECT  62.4 0 62.424 0.192 ;
    END
  END xbi[123]
  PIN xbi[124]
    DIRECTION INPUT ;
    USE SIGNAL ;
    PORT
      LAYER M3 ;
        RECT  62.568 0 62.586 0.144 ;
    END
  END xbi[124]
  PIN xbi[125]
    DIRECTION INPUT ;
    USE SIGNAL ;
    PORT
      LAYER M5 ;
        RECT  62.688 0 62.712 0.192 ;
    END
  END xbi[125]
  PIN xbi[126]
    DIRECTION INPUT ;
    USE SIGNAL ;
    PORT
      LAYER M3 ;
        RECT  62.82 0 62.838 0.144 ;
    END
  END xbi[126]
  PIN xbi[127]
    DIRECTION INPUT ;
    USE SIGNAL ;
    PORT
      LAYER M5 ;
        RECT  62.976 0 63 0.192 ;
    END
  END xbi[127]
  PIN xbi[128]
    DIRECTION INPUT ;
    USE SIGNAL ;
    PORT
      LAYER M3 ;
        RECT  63.108 0 63.126 0.144 ;
    END
  END xbi[128]
  PIN xbi[129]
    DIRECTION INPUT ;
    USE SIGNAL ;
    PORT
      LAYER M5 ;
        RECT  63.264 0 63.288 0.192 ;
    END
  END xbi[129]
  PIN xbi[12]
    DIRECTION INPUT ;
    USE SIGNAL ;
    PORT
      LAYER M3 ;
        RECT  47.124 0 47.142 0.144 ;
    END
  END xbi[12]
  PIN xbi[130]
    DIRECTION INPUT ;
    USE SIGNAL ;
    PORT
      LAYER M3 ;
        RECT  63.396 0 63.414 0.144 ;
    END
  END xbi[130]
  PIN xbi[131]
    DIRECTION INPUT ;
    USE SIGNAL ;
    PORT
      LAYER M5 ;
        RECT  63.504 0 63.528 0.192 ;
    END
  END xbi[131]
  PIN xbi[132]
    DIRECTION INPUT ;
    USE SIGNAL ;
    PORT
      LAYER M3 ;
        RECT  63.648 0 63.666 0.144 ;
    END
  END xbi[132]
  PIN xbi[133]
    DIRECTION INPUT ;
    USE SIGNAL ;
    PORT
      LAYER M5 ;
        RECT  63.792 0 63.816 0.192 ;
    END
  END xbi[133]
  PIN xbi[134]
    DIRECTION INPUT ;
    USE SIGNAL ;
    PORT
      LAYER M3 ;
        RECT  63.936 0 63.954 0.144 ;
    END
  END xbi[134]
  PIN xbi[135]
    DIRECTION INPUT ;
    USE SIGNAL ;
    PORT
      LAYER M5 ;
        RECT  64.08 0 64.104 0.192 ;
    END
  END xbi[135]
  PIN xbi[136]
    DIRECTION INPUT ;
    USE SIGNAL ;
    PORT
      LAYER M3 ;
        RECT  64.224 0 64.242 0.144 ;
    END
  END xbi[136]
  PIN xbi[137]
    DIRECTION INPUT ;
    USE SIGNAL ;
    PORT
      LAYER M5 ;
        RECT  64.368 0 64.392 0.192 ;
    END
  END xbi[137]
  PIN xbi[138]
    DIRECTION INPUT ;
    USE SIGNAL ;
    PORT
      LAYER M3 ;
        RECT  64.476 0 64.494 0.144 ;
    END
  END xbi[138]
  PIN xbi[139]
    DIRECTION INPUT ;
    USE SIGNAL ;
    PORT
      LAYER M5 ;
        RECT  64.608 0 64.632 0.192 ;
    END
  END xbi[139]
  PIN xbi[13]
    DIRECTION INPUT ;
    USE SIGNAL ;
    PORT
      LAYER M5 ;
        RECT  47.232 0 47.256 0.192 ;
    END
  END xbi[13]
  PIN xbi[140]
    DIRECTION INPUT ;
    USE SIGNAL ;
    PORT
      LAYER M3 ;
        RECT  64.764 0 64.782 0.144 ;
    END
  END xbi[140]
  PIN xbi[141]
    DIRECTION INPUT ;
    USE SIGNAL ;
    PORT
      LAYER M5 ;
        RECT  64.896 0 64.92 0.192 ;
    END
  END xbi[141]
  PIN xbi[142]
    DIRECTION INPUT ;
    USE SIGNAL ;
    PORT
      LAYER M3 ;
        RECT  65.052 0 65.07 0.144 ;
    END
  END xbi[142]
  PIN xbi[143]
    DIRECTION INPUT ;
    USE SIGNAL ;
    PORT
      LAYER M5 ;
        RECT  65.184 0 65.208 0.192 ;
    END
  END xbi[143]
  PIN xbi[144]
    DIRECTION INPUT ;
    USE SIGNAL ;
    PORT
      LAYER M3 ;
        RECT  65.304 0 65.322 0.144 ;
    END
  END xbi[144]
  PIN xbi[145]
    DIRECTION INPUT ;
    USE SIGNAL ;
    PORT
      LAYER M5 ;
        RECT  65.472 0 65.496 0.192 ;
    END
  END xbi[145]
  PIN xbi[146]
    DIRECTION INPUT ;
    USE SIGNAL ;
    PORT
      LAYER M3 ;
        RECT  65.592 0 65.61 0.144 ;
    END
  END xbi[146]
  PIN xbi[147]
    DIRECTION INPUT ;
    USE SIGNAL ;
    PORT
      LAYER M5 ;
        RECT  65.712 0 65.736 0.192 ;
    END
  END xbi[147]
  PIN xbi[148]
    DIRECTION INPUT ;
    USE SIGNAL ;
    PORT
      LAYER M3 ;
        RECT  65.88 0 65.898 0.144 ;
    END
  END xbi[148]
  PIN xbi[149]
    DIRECTION INPUT ;
    USE SIGNAL ;
    PORT
      LAYER M5 ;
        RECT  66 0 66.024 0.192 ;
    END
  END xbi[149]
  PIN xbi[14]
    DIRECTION INPUT ;
    USE SIGNAL ;
    PORT
      LAYER M3 ;
        RECT  47.412 0 47.43 0.144 ;
    END
  END xbi[14]
  PIN xbi[150]
    DIRECTION INPUT ;
    USE SIGNAL ;
    PORT
      LAYER M3 ;
        RECT  66.132 0 66.15 0.144 ;
    END
  END xbi[150]
  PIN xbi[151]
    DIRECTION INPUT ;
    USE SIGNAL ;
    PORT
      LAYER M5 ;
        RECT  66.288 0 66.312 0.192 ;
    END
  END xbi[151]
  PIN xbi[152]
    DIRECTION INPUT ;
    USE SIGNAL ;
    PORT
      LAYER M3 ;
        RECT  66.42 0 66.438 0.144 ;
    END
  END xbi[152]
  PIN xbi[153]
    DIRECTION INPUT ;
    USE SIGNAL ;
    PORT
      LAYER M5 ;
        RECT  66.576 0 66.6 0.192 ;
    END
  END xbi[153]
  PIN xbi[154]
    DIRECTION INPUT ;
    USE SIGNAL ;
    PORT
      LAYER M3 ;
        RECT  66.708 0 66.726 0.144 ;
    END
  END xbi[154]
  PIN xbi[155]
    DIRECTION INPUT ;
    USE SIGNAL ;
    PORT
      LAYER M5 ;
        RECT  66.816 0 66.84 0.192 ;
    END
  END xbi[155]
  PIN xbi[156]
    DIRECTION INPUT ;
    USE SIGNAL ;
    PORT
      LAYER M3 ;
        RECT  66.96 0 66.978 0.144 ;
    END
  END xbi[156]
  PIN xbi[157]
    DIRECTION INPUT ;
    USE SIGNAL ;
    PORT
      LAYER M5 ;
        RECT  67.104 0 67.128 0.192 ;
    END
  END xbi[157]
  PIN xbi[158]
    DIRECTION INPUT ;
    USE SIGNAL ;
    PORT
      LAYER M3 ;
        RECT  67.248 0 67.266 0.144 ;
    END
  END xbi[158]
  PIN xbi[159]
    DIRECTION INPUT ;
    USE SIGNAL ;
    PORT
      LAYER M5 ;
        RECT  67.392 0 67.416 0.192 ;
    END
  END xbi[159]
  PIN xbi[15]
    DIRECTION INPUT ;
    USE SIGNAL ;
    PORT
      LAYER M5 ;
        RECT  47.52 0 47.544 0.192 ;
    END
  END xbi[15]
  PIN xbi[160]
    DIRECTION INPUT ;
    USE SIGNAL ;
    PORT
      LAYER M3 ;
        RECT  67.536 0 67.554 0.144 ;
    END
  END xbi[160]
  PIN xbi[161]
    DIRECTION INPUT ;
    USE SIGNAL ;
    PORT
      LAYER M5 ;
        RECT  67.68 0 67.704 0.192 ;
    END
  END xbi[161]
  PIN xbi[162]
    DIRECTION INPUT ;
    USE SIGNAL ;
    PORT
      LAYER M3 ;
        RECT  67.788 0 67.806 0.144 ;
    END
  END xbi[162]
  PIN xbi[163]
    DIRECTION INPUT ;
    USE SIGNAL ;
    PORT
      LAYER M5 ;
        RECT  67.92 0 67.944 0.192 ;
    END
  END xbi[163]
  PIN xbi[164]
    DIRECTION INPUT ;
    USE SIGNAL ;
    PORT
      LAYER M3 ;
        RECT  68.076 0 68.094 0.144 ;
    END
  END xbi[164]
  PIN xbi[165]
    DIRECTION INPUT ;
    USE SIGNAL ;
    PORT
      LAYER M5 ;
        RECT  68.208 0 68.232 0.192 ;
    END
  END xbi[165]
  PIN xbi[166]
    DIRECTION INPUT ;
    USE SIGNAL ;
    PORT
      LAYER M3 ;
        RECT  68.364 0 68.382 0.144 ;
    END
  END xbi[166]
  PIN xbi[167]
    DIRECTION INPUT ;
    USE SIGNAL ;
    PORT
      LAYER M5 ;
        RECT  68.496 0 68.52 0.192 ;
    END
  END xbi[167]
  PIN xbi[168]
    DIRECTION INPUT ;
    USE SIGNAL ;
    PORT
      LAYER M3 ;
        RECT  68.616 0 68.634 0.144 ;
    END
  END xbi[168]
  PIN xbi[169]
    DIRECTION INPUT ;
    USE SIGNAL ;
    PORT
      LAYER M5 ;
        RECT  68.784 0 68.808 0.192 ;
    END
  END xbi[169]
  PIN xbi[16]
    DIRECTION INPUT ;
    USE SIGNAL ;
    PORT
      LAYER M3 ;
        RECT  47.664 0 47.682 0.144 ;
    END
  END xbi[16]
  PIN xbi[170]
    DIRECTION INPUT ;
    USE SIGNAL ;
    PORT
      LAYER M3 ;
        RECT  68.904 0 68.922 0.144 ;
    END
  END xbi[170]
  PIN xbi[171]
    DIRECTION INPUT ;
    USE SIGNAL ;
    PORT
      LAYER M5 ;
        RECT  69.024 0 69.048 0.192 ;
    END
  END xbi[171]
  PIN xbi[172]
    DIRECTION INPUT ;
    USE SIGNAL ;
    PORT
      LAYER M3 ;
        RECT  69.192 0 69.21 0.144 ;
    END
  END xbi[172]
  PIN xbi[173]
    DIRECTION INPUT ;
    USE SIGNAL ;
    PORT
      LAYER M5 ;
        RECT  69.312 0 69.336 0.192 ;
    END
  END xbi[173]
  PIN xbi[174]
    DIRECTION INPUT ;
    USE SIGNAL ;
    PORT
      LAYER M3 ;
        RECT  69.444 0 69.462 0.144 ;
    END
  END xbi[174]
  PIN xbi[175]
    DIRECTION INPUT ;
    USE SIGNAL ;
    PORT
      LAYER M5 ;
        RECT  69.6 0 69.624 0.192 ;
    END
  END xbi[175]
  PIN xbi[176]
    DIRECTION INPUT ;
    USE SIGNAL ;
    PORT
      LAYER M3 ;
        RECT  69.732 0 69.75 0.144 ;
    END
  END xbi[176]
  PIN xbi[177]
    DIRECTION INPUT ;
    USE SIGNAL ;
    PORT
      LAYER M5 ;
        RECT  69.888 0 69.912 0.192 ;
    END
  END xbi[177]
  PIN xbi[178]
    DIRECTION INPUT ;
    USE SIGNAL ;
    PORT
      LAYER M3 ;
        RECT  70.02 0 70.038 0.144 ;
    END
  END xbi[178]
  PIN xbi[179]
    DIRECTION INPUT ;
    USE SIGNAL ;
    PORT
      LAYER M5 ;
        RECT  70.128 0 70.152 0.192 ;
    END
  END xbi[179]
  PIN xbi[17]
    DIRECTION INPUT ;
    USE SIGNAL ;
    PORT
      LAYER M5 ;
        RECT  47.808 0 47.832 0.192 ;
    END
  END xbi[17]
  PIN xbi[180]
    DIRECTION INPUT ;
    USE SIGNAL ;
    PORT
      LAYER M3 ;
        RECT  70.272 0 70.29 0.144 ;
    END
  END xbi[180]
  PIN xbi[181]
    DIRECTION INPUT ;
    USE SIGNAL ;
    PORT
      LAYER M5 ;
        RECT  70.416 0 70.44 0.192 ;
    END
  END xbi[181]
  PIN xbi[182]
    DIRECTION INPUT ;
    USE SIGNAL ;
    PORT
      LAYER M3 ;
        RECT  70.56 0 70.578 0.144 ;
    END
  END xbi[182]
  PIN xbi[183]
    DIRECTION INPUT ;
    USE SIGNAL ;
    PORT
      LAYER M5 ;
        RECT  70.704 0 70.728 0.192 ;
    END
  END xbi[183]
  PIN xbi[184]
    DIRECTION INPUT ;
    USE SIGNAL ;
    PORT
      LAYER M3 ;
        RECT  70.848 0 70.866 0.144 ;
    END
  END xbi[184]
  PIN xbi[185]
    DIRECTION INPUT ;
    USE SIGNAL ;
    PORT
      LAYER M5 ;
        RECT  70.992 0 71.016 0.192 ;
    END
  END xbi[185]
  PIN xbi[186]
    DIRECTION INPUT ;
    USE SIGNAL ;
    PORT
      LAYER M3 ;
        RECT  71.1 0 71.118 0.144 ;
    END
  END xbi[186]
  PIN xbi[187]
    DIRECTION INPUT ;
    USE SIGNAL ;
    PORT
      LAYER M5 ;
        RECT  71.232 0 71.256 0.192 ;
    END
  END xbi[187]
  PIN xbi[188]
    DIRECTION INPUT ;
    USE SIGNAL ;
    PORT
      LAYER M3 ;
        RECT  71.388 0 71.406 0.144 ;
    END
  END xbi[188]
  PIN xbi[189]
    DIRECTION INPUT ;
    USE SIGNAL ;
    PORT
      LAYER M5 ;
        RECT  71.52 0 71.544 0.192 ;
    END
  END xbi[189]
  PIN xbi[18]
    DIRECTION INPUT ;
    USE SIGNAL ;
    PORT
      LAYER M3 ;
        RECT  47.952 0 47.97 0.144 ;
    END
  END xbi[18]
  PIN xbi[190]
    DIRECTION INPUT ;
    USE SIGNAL ;
    PORT
      LAYER M3 ;
        RECT  71.676 0 71.694 0.144 ;
    END
  END xbi[190]
  PIN xbi[191]
    DIRECTION INPUT ;
    USE SIGNAL ;
    PORT
      LAYER M5 ;
        RECT  71.808 0 71.832 0.192 ;
    END
  END xbi[191]
  PIN xbi[192]
    DIRECTION INPUT ;
    USE SIGNAL ;
    PORT
      LAYER M3 ;
        RECT  71.928 0 71.946 0.144 ;
    END
  END xbi[192]
  PIN xbi[193]
    DIRECTION INPUT ;
    USE SIGNAL ;
    PORT
      LAYER M5 ;
        RECT  72.096 0 72.12 0.192 ;
    END
  END xbi[193]
  PIN xbi[194]
    DIRECTION INPUT ;
    USE SIGNAL ;
    PORT
      LAYER M3 ;
        RECT  72.216 0 72.234 0.144 ;
    END
  END xbi[194]
  PIN xbi[195]
    DIRECTION INPUT ;
    USE SIGNAL ;
    PORT
      LAYER M5 ;
        RECT  72.336 0 72.36 0.192 ;
    END
  END xbi[195]
  PIN xbi[196]
    DIRECTION INPUT ;
    USE SIGNAL ;
    PORT
      LAYER M3 ;
        RECT  72.504 0 72.522 0.144 ;
    END
  END xbi[196]
  PIN xbi[197]
    DIRECTION INPUT ;
    USE SIGNAL ;
    PORT
      LAYER M5 ;
        RECT  72.624 0 72.648 0.192 ;
    END
  END xbi[197]
  PIN xbi[198]
    DIRECTION INPUT ;
    USE SIGNAL ;
    PORT
      LAYER M3 ;
        RECT  72.756 0 72.774 0.144 ;
    END
  END xbi[198]
  PIN xbi[199]
    DIRECTION INPUT ;
    USE SIGNAL ;
    PORT
      LAYER M5 ;
        RECT  72.912 0 72.936 0.192 ;
    END
  END xbi[199]
  PIN xbi[19]
    DIRECTION INPUT ;
    USE SIGNAL ;
    PORT
      LAYER M5 ;
        RECT  48.096 0 48.12 0.192 ;
    END
  END xbi[19]
  PIN xbi[1]
    DIRECTION INPUT ;
    USE SIGNAL ;
    PORT
      LAYER M5 ;
        RECT  45.6 0 45.624 0.192 ;
    END
  END xbi[1]
  PIN xbi[200]
    DIRECTION INPUT ;
    USE SIGNAL ;
    PORT
      LAYER M3 ;
        RECT  73.044 0 73.062 0.144 ;
    END
  END xbi[200]
  PIN xbi[201]
    DIRECTION INPUT ;
    USE SIGNAL ;
    PORT
      LAYER M5 ;
        RECT  73.152 0 73.176 0.192 ;
    END
  END xbi[201]
  PIN xbi[202]
    DIRECTION INPUT ;
    USE SIGNAL ;
    PORT
      LAYER M3 ;
        RECT  73.332 0 73.35 0.144 ;
    END
  END xbi[202]
  PIN xbi[203]
    DIRECTION INPUT ;
    USE SIGNAL ;
    PORT
      LAYER M5 ;
        RECT  73.44 0 73.464 0.192 ;
    END
  END xbi[203]
  PIN xbi[204]
    DIRECTION INPUT ;
    USE SIGNAL ;
    PORT
      LAYER M3 ;
        RECT  73.584 0 73.602 0.144 ;
    END
  END xbi[204]
  PIN xbi[205]
    DIRECTION INPUT ;
    USE SIGNAL ;
    PORT
      LAYER M5 ;
        RECT  73.728 0 73.752 0.192 ;
    END
  END xbi[205]
  PIN xbi[206]
    DIRECTION INPUT ;
    USE SIGNAL ;
    PORT
      LAYER M3 ;
        RECT  73.872 0 73.89 0.144 ;
    END
  END xbi[206]
  PIN xbi[207]
    DIRECTION INPUT ;
    USE SIGNAL ;
    PORT
      LAYER M5 ;
        RECT  74.016 0 74.04 0.192 ;
    END
  END xbi[207]
  PIN xbi[208]
    DIRECTION INPUT ;
    USE SIGNAL ;
    PORT
      LAYER M3 ;
        RECT  74.16 0 74.178 0.144 ;
    END
  END xbi[208]
  PIN xbi[209]
    DIRECTION INPUT ;
    USE SIGNAL ;
    PORT
      LAYER M5 ;
        RECT  74.256 0 74.28 0.192 ;
    END
  END xbi[209]
  PIN xbi[20]
    DIRECTION INPUT ;
    USE SIGNAL ;
    PORT
      LAYER M3 ;
        RECT  48.24 0 48.258 0.144 ;
    END
  END xbi[20]
  PIN xbi[210]
    DIRECTION INPUT ;
    USE SIGNAL ;
    PORT
      LAYER M3 ;
        RECT  74.412 0 74.43 0.144 ;
    END
  END xbi[210]
  PIN xbi[211]
    DIRECTION INPUT ;
    USE SIGNAL ;
    PORT
      LAYER M5 ;
        RECT  74.544 0 74.568 0.192 ;
    END
  END xbi[211]
  PIN xbi[212]
    DIRECTION INPUT ;
    USE SIGNAL ;
    PORT
      LAYER M3 ;
        RECT  74.7 0 74.718 0.144 ;
    END
  END xbi[212]
  PIN xbi[213]
    DIRECTION INPUT ;
    USE SIGNAL ;
    PORT
      LAYER M5 ;
        RECT  74.832 0 74.856 0.192 ;
    END
  END xbi[213]
  PIN xbi[214]
    DIRECTION INPUT ;
    USE SIGNAL ;
    PORT
      LAYER M3 ;
        RECT  74.988 0 75.006 0.144 ;
    END
  END xbi[214]
  PIN xbi[215]
    DIRECTION INPUT ;
    USE SIGNAL ;
    PORT
      LAYER M5 ;
        RECT  75.12 0 75.144 0.192 ;
    END
  END xbi[215]
  PIN xbi[216]
    DIRECTION INPUT ;
    USE SIGNAL ;
    PORT
      LAYER M3 ;
        RECT  75.24 0 75.258 0.144 ;
    END
  END xbi[216]
  PIN xbi[217]
    DIRECTION INPUT ;
    USE SIGNAL ;
    PORT
      LAYER M5 ;
        RECT  75.36 0 75.384 0.192 ;
    END
  END xbi[217]
  PIN xbi[218]
    DIRECTION INPUT ;
    USE SIGNAL ;
    PORT
      LAYER M3 ;
        RECT  75.528 0 75.546 0.144 ;
    END
  END xbi[218]
  PIN xbi[219]
    DIRECTION INPUT ;
    USE SIGNAL ;
    PORT
      LAYER M5 ;
        RECT  75.648 0 75.672 0.192 ;
    END
  END xbi[219]
  PIN xbi[21]
    DIRECTION INPUT ;
    USE SIGNAL ;
    PORT
      LAYER M5 ;
        RECT  48.336 0 48.36 0.192 ;
    END
  END xbi[21]
  PIN xbi[220]
    DIRECTION INPUT ;
    USE SIGNAL ;
    PORT
      LAYER M3 ;
        RECT  75.78 0 75.798 0.144 ;
    END
  END xbi[220]
  PIN xbi[221]
    DIRECTION INPUT ;
    USE SIGNAL ;
    PORT
      LAYER M5 ;
        RECT  75.936 0 75.96 0.192 ;
    END
  END xbi[221]
  PIN xbi[222]
    DIRECTION INPUT ;
    USE SIGNAL ;
    PORT
      LAYER M3 ;
        RECT  76.068 0 76.086 0.144 ;
    END
  END xbi[222]
  PIN xbi[223]
    DIRECTION INPUT ;
    USE SIGNAL ;
    PORT
      LAYER M5 ;
        RECT  76.224 0 76.248 0.192 ;
    END
  END xbi[223]
  PIN xbi[224]
    DIRECTION INPUT ;
    USE SIGNAL ;
    PORT
      LAYER M3 ;
        RECT  76.356 0 76.374 0.144 ;
    END
  END xbi[224]
  PIN xbi[225]
    DIRECTION INPUT ;
    USE SIGNAL ;
    PORT
      LAYER M5 ;
        RECT  76.464 0 76.488 0.192 ;
    END
  END xbi[225]
  PIN xbi[226]
    DIRECTION INPUT ;
    USE SIGNAL ;
    PORT
      LAYER M3 ;
        RECT  76.608 0 76.626 0.144 ;
    END
  END xbi[226]
  PIN xbi[227]
    DIRECTION INPUT ;
    USE SIGNAL ;
    PORT
      LAYER M5 ;
        RECT  76.752 0 76.776 0.192 ;
    END
  END xbi[227]
  PIN xbi[228]
    DIRECTION INPUT ;
    USE SIGNAL ;
    PORT
      LAYER M3 ;
        RECT  76.896 0 76.914 0.144 ;
    END
  END xbi[228]
  PIN xbi[229]
    DIRECTION INPUT ;
    USE SIGNAL ;
    PORT
      LAYER M5 ;
        RECT  77.04 0 77.064 0.192 ;
    END
  END xbi[229]
  PIN xbi[22]
    DIRECTION INPUT ;
    USE SIGNAL ;
    PORT
      LAYER M3 ;
        RECT  48.492 0 48.51 0.144 ;
    END
  END xbi[22]
  PIN xbi[230]
    DIRECTION INPUT ;
    USE SIGNAL ;
    PORT
      LAYER M3 ;
        RECT  77.184 0 77.202 0.144 ;
    END
  END xbi[230]
  PIN xbi[231]
    DIRECTION INPUT ;
    USE SIGNAL ;
    PORT
      LAYER M5 ;
        RECT  77.328 0 77.352 0.192 ;
    END
  END xbi[231]
  PIN xbi[232]
    DIRECTION INPUT ;
    USE SIGNAL ;
    PORT
      LAYER M3 ;
        RECT  77.436 0 77.454 0.144 ;
    END
  END xbi[232]
  PIN xbi[233]
    DIRECTION INPUT ;
    USE SIGNAL ;
    PORT
      LAYER M5 ;
        RECT  77.568 0 77.592 0.192 ;
    END
  END xbi[233]
  PIN xbi[234]
    DIRECTION INPUT ;
    USE SIGNAL ;
    PORT
      LAYER M3 ;
        RECT  77.724 0 77.742 0.144 ;
    END
  END xbi[234]
  PIN xbi[235]
    DIRECTION INPUT ;
    USE SIGNAL ;
    PORT
      LAYER M5 ;
        RECT  77.856 0 77.88 0.192 ;
    END
  END xbi[235]
  PIN xbi[236]
    DIRECTION INPUT ;
    USE SIGNAL ;
    PORT
      LAYER M3 ;
        RECT  78.012 0 78.03 0.144 ;
    END
  END xbi[236]
  PIN xbi[237]
    DIRECTION INPUT ;
    USE SIGNAL ;
    PORT
      LAYER M5 ;
        RECT  78.144 0 78.168 0.192 ;
    END
  END xbi[237]
  PIN xbi[238]
    DIRECTION INPUT ;
    USE SIGNAL ;
    PORT
      LAYER M3 ;
        RECT  78.264 0 78.282 0.144 ;
    END
  END xbi[238]
  PIN xbi[239]
    DIRECTION INPUT ;
    USE SIGNAL ;
    PORT
      LAYER M5 ;
        RECT  78.432 0 78.456 0.192 ;
    END
  END xbi[239]
  PIN xbi[23]
    DIRECTION INPUT ;
    USE SIGNAL ;
    PORT
      LAYER M5 ;
        RECT  48.624 0 48.648 0.192 ;
    END
  END xbi[23]
  PIN xbi[240]
    DIRECTION INPUT ;
    USE SIGNAL ;
    PORT
      LAYER M3 ;
        RECT  78.552 0 78.57 0.144 ;
    END
  END xbi[240]
  PIN xbi[241]
    DIRECTION INPUT ;
    USE SIGNAL ;
    PORT
      LAYER M5 ;
        RECT  78.672 0 78.696 0.192 ;
    END
  END xbi[241]
  PIN xbi[242]
    DIRECTION INPUT ;
    USE SIGNAL ;
    PORT
      LAYER M3 ;
        RECT  78.84 0 78.858 0.144 ;
    END
  END xbi[242]
  PIN xbi[243]
    DIRECTION INPUT ;
    USE SIGNAL ;
    PORT
      LAYER M5 ;
        RECT  78.96 0 78.984 0.192 ;
    END
  END xbi[243]
  PIN xbi[244]
    DIRECTION INPUT ;
    USE SIGNAL ;
    PORT
      LAYER M3 ;
        RECT  79.092 0 79.11 0.144 ;
    END
  END xbi[244]
  PIN xbi[245]
    DIRECTION INPUT ;
    USE SIGNAL ;
    PORT
      LAYER M5 ;
        RECT  79.248 0 79.272 0.192 ;
    END
  END xbi[245]
  PIN xbi[246]
    DIRECTION INPUT ;
    USE SIGNAL ;
    PORT
      LAYER M3 ;
        RECT  79.38 0 79.398 0.144 ;
    END
  END xbi[246]
  PIN xbi[247]
    DIRECTION INPUT ;
    USE SIGNAL ;
    PORT
      LAYER M5 ;
        RECT  79.536 0 79.56 0.192 ;
    END
  END xbi[247]
  PIN xbi[248]
    DIRECTION INPUT ;
    USE SIGNAL ;
    PORT
      LAYER M3 ;
        RECT  79.668 0 79.686 0.144 ;
    END
  END xbi[248]
  PIN xbi[249]
    DIRECTION INPUT ;
    USE SIGNAL ;
    PORT
      LAYER M5 ;
        RECT  79.776 0 79.8 0.192 ;
    END
  END xbi[249]
  PIN xbi[24]
    DIRECTION INPUT ;
    USE SIGNAL ;
    PORT
      LAYER M3 ;
        RECT  48.78 0 48.798 0.144 ;
    END
  END xbi[24]
  PIN xbi[250]
    DIRECTION INPUT ;
    USE SIGNAL ;
    PORT
      LAYER M3 ;
        RECT  79.92 0 79.938 0.144 ;
    END
  END xbi[250]
  PIN xbi[251]
    DIRECTION INPUT ;
    USE SIGNAL ;
    PORT
      LAYER M5 ;
        RECT  80.064 0 80.088 0.192 ;
    END
  END xbi[251]
  PIN xbi[252]
    DIRECTION INPUT ;
    USE SIGNAL ;
    PORT
      LAYER M3 ;
        RECT  80.208 0 80.226 0.144 ;
    END
  END xbi[252]
  PIN xbi[253]
    DIRECTION INPUT ;
    USE SIGNAL ;
    PORT
      LAYER M5 ;
        RECT  80.352 0 80.376 0.192 ;
    END
  END xbi[253]
  PIN xbi[254]
    DIRECTION INPUT ;
    USE SIGNAL ;
    PORT
      LAYER M3 ;
        RECT  80.496 0 80.514 0.144 ;
    END
  END xbi[254]
  PIN xbi[255]
    DIRECTION INPUT ;
    USE SIGNAL ;
    PORT
      LAYER M5 ;
        RECT  80.64 0 80.664 0.192 ;
    END
  END xbi[255]
  PIN xbi[256]
    DIRECTION INPUT ;
    USE SIGNAL ;
    PORT
      LAYER M3 ;
        RECT  80.748 0 80.766 0.144 ;
    END
  END xbi[256]
  PIN xbi[257]
    DIRECTION INPUT ;
    USE SIGNAL ;
    PORT
      LAYER M5 ;
        RECT  80.88 0 80.904 0.192 ;
    END
  END xbi[257]
  PIN xbi[258]
    DIRECTION INPUT ;
    USE SIGNAL ;
    PORT
      LAYER M3 ;
        RECT  81.036 0 81.054 0.144 ;
    END
  END xbi[258]
  PIN xbi[259]
    DIRECTION INPUT ;
    USE SIGNAL ;
    PORT
      LAYER M5 ;
        RECT  81.168 0 81.192 0.192 ;
    END
  END xbi[259]
  PIN xbi[25]
    DIRECTION INPUT ;
    USE SIGNAL ;
    PORT
      LAYER M5 ;
        RECT  48.912 0 48.936 0.192 ;
    END
  END xbi[25]
  PIN xbi[260]
    DIRECTION INPUT ;
    USE SIGNAL ;
    PORT
      LAYER M3 ;
        RECT  81.324 0 81.342 0.144 ;
    END
  END xbi[260]
  PIN xbi[261]
    DIRECTION INPUT ;
    USE SIGNAL ;
    PORT
      LAYER M5 ;
        RECT  81.456 0 81.48 0.192 ;
    END
  END xbi[261]
  PIN xbi[262]
    DIRECTION INPUT ;
    USE SIGNAL ;
    PORT
      LAYER M3 ;
        RECT  81.576 0 81.594 0.144 ;
    END
  END xbi[262]
  PIN xbi[263]
    DIRECTION INPUT ;
    USE SIGNAL ;
    PORT
      LAYER M5 ;
        RECT  81.744 0 81.768 0.192 ;
    END
  END xbi[263]
  PIN xbi[264]
    DIRECTION INPUT ;
    USE SIGNAL ;
    PORT
      LAYER M3 ;
        RECT  81.864 0 81.882 0.144 ;
    END
  END xbi[264]
  PIN xbi[265]
    DIRECTION INPUT ;
    USE SIGNAL ;
    PORT
      LAYER M5 ;
        RECT  81.984 0 82.008 0.192 ;
    END
  END xbi[265]
  PIN xbi[26]
    DIRECTION INPUT ;
    USE SIGNAL ;
    PORT
      LAYER M3 ;
        RECT  49.068 0 49.086 0.144 ;
    END
  END xbi[26]
  PIN xbi[27]
    DIRECTION INPUT ;
    USE SIGNAL ;
    PORT
      LAYER M5 ;
        RECT  49.2 0 49.224 0.192 ;
    END
  END xbi[27]
  PIN xbi[28]
    DIRECTION INPUT ;
    USE SIGNAL ;
    PORT
      LAYER M3 ;
        RECT  49.32 0 49.338 0.144 ;
    END
  END xbi[28]
  PIN xbi[29]
    DIRECTION INPUT ;
    USE SIGNAL ;
    PORT
      LAYER M5 ;
        RECT  49.44 0 49.464 0.192 ;
    END
  END xbi[29]
  PIN xbi[2]
    DIRECTION INPUT ;
    USE SIGNAL ;
    PORT
      LAYER M3 ;
        RECT  45.756 0 45.774 0.144 ;
    END
  END xbi[2]
  PIN xbi[30]
    DIRECTION INPUT ;
    USE SIGNAL ;
    PORT
      LAYER M3 ;
        RECT  49.608 0 49.626 0.144 ;
    END
  END xbi[30]
  PIN xbi[31]
    DIRECTION INPUT ;
    USE SIGNAL ;
    PORT
      LAYER M5 ;
        RECT  49.728 0 49.752 0.192 ;
    END
  END xbi[31]
  PIN xbi[32]
    DIRECTION INPUT ;
    USE SIGNAL ;
    PORT
      LAYER M3 ;
        RECT  49.86 0 49.878 0.144 ;
    END
  END xbi[32]
  PIN xbi[33]
    DIRECTION INPUT ;
    USE SIGNAL ;
    PORT
      LAYER M5 ;
        RECT  50.016 0 50.04 0.192 ;
    END
  END xbi[33]
  PIN xbi[34]
    DIRECTION INPUT ;
    USE SIGNAL ;
    PORT
      LAYER M3 ;
        RECT  50.148 0 50.166 0.144 ;
    END
  END xbi[34]
  PIN xbi[35]
    DIRECTION INPUT ;
    USE SIGNAL ;
    PORT
      LAYER M5 ;
        RECT  50.304 0 50.328 0.192 ;
    END
  END xbi[35]
  PIN xbi[36]
    DIRECTION INPUT ;
    USE SIGNAL ;
    PORT
      LAYER M3 ;
        RECT  50.436 0 50.454 0.144 ;
    END
  END xbi[36]
  PIN xbi[37]
    DIRECTION INPUT ;
    USE SIGNAL ;
    PORT
      LAYER M5 ;
        RECT  50.544 0 50.568 0.192 ;
    END
  END xbi[37]
  PIN xbi[38]
    DIRECTION INPUT ;
    USE SIGNAL ;
    PORT
      LAYER M3 ;
        RECT  50.688 0 50.706 0.144 ;
    END
  END xbi[38]
  PIN xbi[39]
    DIRECTION INPUT ;
    USE SIGNAL ;
    PORT
      LAYER M5 ;
        RECT  50.832 0 50.856 0.192 ;
    END
  END xbi[39]
  PIN xbi[3]
    DIRECTION INPUT ;
    USE SIGNAL ;
    PORT
      LAYER M5 ;
        RECT  45.888 0 45.912 0.192 ;
    END
  END xbi[3]
  PIN xbi[40]
    DIRECTION INPUT ;
    USE SIGNAL ;
    PORT
      LAYER M3 ;
        RECT  50.976 0 50.994 0.144 ;
    END
  END xbi[40]
  PIN xbi[41]
    DIRECTION INPUT ;
    USE SIGNAL ;
    PORT
      LAYER M5 ;
        RECT  51.12 0 51.144 0.192 ;
    END
  END xbi[41]
  PIN xbi[42]
    DIRECTION INPUT ;
    USE SIGNAL ;
    PORT
      LAYER M3 ;
        RECT  51.264 0 51.282 0.144 ;
    END
  END xbi[42]
  PIN xbi[43]
    DIRECTION INPUT ;
    USE SIGNAL ;
    PORT
      LAYER M5 ;
        RECT  51.408 0 51.432 0.192 ;
    END
  END xbi[43]
  PIN xbi[44]
    DIRECTION INPUT ;
    USE SIGNAL ;
    PORT
      LAYER M3 ;
        RECT  51.516 0 51.534 0.144 ;
    END
  END xbi[44]
  PIN xbi[45]
    DIRECTION INPUT ;
    USE SIGNAL ;
    PORT
      LAYER M5 ;
        RECT  51.648 0 51.672 0.192 ;
    END
  END xbi[45]
  PIN xbi[46]
    DIRECTION INPUT ;
    USE SIGNAL ;
    PORT
      LAYER M3 ;
        RECT  51.804 0 51.822 0.144 ;
    END
  END xbi[46]
  PIN xbi[47]
    DIRECTION INPUT ;
    USE SIGNAL ;
    PORT
      LAYER M5 ;
        RECT  51.936 0 51.96 0.192 ;
    END
  END xbi[47]
  PIN xbi[48]
    DIRECTION INPUT ;
    USE SIGNAL ;
    PORT
      LAYER M3 ;
        RECT  52.092 0 52.11 0.144 ;
    END
  END xbi[48]
  PIN xbi[49]
    DIRECTION INPUT ;
    USE SIGNAL ;
    PORT
      LAYER M5 ;
        RECT  52.224 0 52.248 0.192 ;
    END
  END xbi[49]
  PIN xbi[4]
    DIRECTION INPUT ;
    USE SIGNAL ;
    PORT
      LAYER M3 ;
        RECT  46.008 0 46.026 0.144 ;
    END
  END xbi[4]
  PIN xbi[50]
    DIRECTION INPUT ;
    USE SIGNAL ;
    PORT
      LAYER M3 ;
        RECT  52.344 0 52.362 0.144 ;
    END
  END xbi[50]
  PIN xbi[51]
    DIRECTION INPUT ;
    USE SIGNAL ;
    PORT
      LAYER M5 ;
        RECT  52.512 0 52.536 0.192 ;
    END
  END xbi[51]
  PIN xbi[52]
    DIRECTION INPUT ;
    USE SIGNAL ;
    PORT
      LAYER M3 ;
        RECT  52.632 0 52.65 0.144 ;
    END
  END xbi[52]
  PIN xbi[53]
    DIRECTION INPUT ;
    USE SIGNAL ;
    PORT
      LAYER M5 ;
        RECT  52.752 0 52.776 0.192 ;
    END
  END xbi[53]
  PIN xbi[54]
    DIRECTION INPUT ;
    USE SIGNAL ;
    PORT
      LAYER M3 ;
        RECT  52.92 0 52.938 0.144 ;
    END
  END xbi[54]
  PIN xbi[55]
    DIRECTION INPUT ;
    USE SIGNAL ;
    PORT
      LAYER M5 ;
        RECT  53.04 0 53.064 0.192 ;
    END
  END xbi[55]
  PIN xbi[56]
    DIRECTION INPUT ;
    USE SIGNAL ;
    PORT
      LAYER M3 ;
        RECT  53.172 0 53.19 0.144 ;
    END
  END xbi[56]
  PIN xbi[57]
    DIRECTION INPUT ;
    USE SIGNAL ;
    PORT
      LAYER M5 ;
        RECT  53.328 0 53.352 0.192 ;
    END
  END xbi[57]
  PIN xbi[58]
    DIRECTION INPUT ;
    USE SIGNAL ;
    PORT
      LAYER M3 ;
        RECT  53.46 0 53.478 0.144 ;
    END
  END xbi[58]
  PIN xbi[59]
    DIRECTION INPUT ;
    USE SIGNAL ;
    PORT
      LAYER M5 ;
        RECT  53.616 0 53.64 0.192 ;
    END
  END xbi[59]
  PIN xbi[5]
    DIRECTION INPUT ;
    USE SIGNAL ;
    PORT
      LAYER M5 ;
        RECT  46.176 0 46.2 0.192 ;
    END
  END xbi[5]
  PIN xbi[60]
    DIRECTION INPUT ;
    USE SIGNAL ;
    PORT
      LAYER M3 ;
        RECT  53.748 0 53.766 0.144 ;
    END
  END xbi[60]
  PIN xbi[61]
    DIRECTION INPUT ;
    USE SIGNAL ;
    PORT
      LAYER M5 ;
        RECT  53.856 0 53.88 0.192 ;
    END
  END xbi[61]
  PIN xbi[62]
    DIRECTION INPUT ;
    USE SIGNAL ;
    PORT
      LAYER M3 ;
        RECT  54 0 54.018 0.144 ;
    END
  END xbi[62]
  PIN xbi[63]
    DIRECTION INPUT ;
    USE SIGNAL ;
    PORT
      LAYER M5 ;
        RECT  54.144 0 54.168 0.192 ;
    END
  END xbi[63]
  PIN xbi[64]
    DIRECTION INPUT ;
    USE SIGNAL ;
    PORT
      LAYER M3 ;
        RECT  54.288 0 54.306 0.144 ;
    END
  END xbi[64]
  PIN xbi[65]
    DIRECTION INPUT ;
    USE SIGNAL ;
    PORT
      LAYER M5 ;
        RECT  54.432 0 54.456 0.192 ;
    END
  END xbi[65]
  PIN xbi[66]
    DIRECTION INPUT ;
    USE SIGNAL ;
    PORT
      LAYER M3 ;
        RECT  54.576 0 54.594 0.144 ;
    END
  END xbi[66]
  PIN xbi[67]
    DIRECTION INPUT ;
    USE SIGNAL ;
    PORT
      LAYER M5 ;
        RECT  54.72 0 54.744 0.192 ;
    END
  END xbi[67]
  PIN xbi[68]
    DIRECTION INPUT ;
    USE SIGNAL ;
    PORT
      LAYER M3 ;
        RECT  54.828 0 54.846 0.144 ;
    END
  END xbi[68]
  PIN xbi[69]
    DIRECTION INPUT ;
    USE SIGNAL ;
    PORT
      LAYER M5 ;
        RECT  54.96 0 54.984 0.192 ;
    END
  END xbi[69]
  PIN xbi[6]
    DIRECTION INPUT ;
    USE SIGNAL ;
    PORT
      LAYER M3 ;
        RECT  46.296 0 46.314 0.144 ;
    END
  END xbi[6]
  PIN xbi[70]
    DIRECTION INPUT ;
    USE SIGNAL ;
    PORT
      LAYER M3 ;
        RECT  55.116 0 55.134 0.144 ;
    END
  END xbi[70]
  PIN xbi[71]
    DIRECTION INPUT ;
    USE SIGNAL ;
    PORT
      LAYER M5 ;
        RECT  55.248 0 55.272 0.192 ;
    END
  END xbi[71]
  PIN xbi[72]
    DIRECTION INPUT ;
    USE SIGNAL ;
    PORT
      LAYER M3 ;
        RECT  55.404 0 55.422 0.144 ;
    END
  END xbi[72]
  PIN xbi[73]
    DIRECTION INPUT ;
    USE SIGNAL ;
    PORT
      LAYER M5 ;
        RECT  55.536 0 55.56 0.192 ;
    END
  END xbi[73]
  PIN xbi[74]
    DIRECTION INPUT ;
    USE SIGNAL ;
    PORT
      LAYER M3 ;
        RECT  55.656 0 55.674 0.144 ;
    END
  END xbi[74]
  PIN xbi[75]
    DIRECTION INPUT ;
    USE SIGNAL ;
    PORT
      LAYER M5 ;
        RECT  55.824 0 55.848 0.192 ;
    END
  END xbi[75]
  PIN xbi[76]
    DIRECTION INPUT ;
    USE SIGNAL ;
    PORT
      LAYER M3 ;
        RECT  55.944 0 55.962 0.144 ;
    END
  END xbi[76]
  PIN xbi[77]
    DIRECTION INPUT ;
    USE SIGNAL ;
    PORT
      LAYER M5 ;
        RECT  56.064 0 56.088 0.192 ;
    END
  END xbi[77]
  PIN xbi[78]
    DIRECTION INPUT ;
    USE SIGNAL ;
    PORT
      LAYER M3 ;
        RECT  56.232 0 56.25 0.144 ;
    END
  END xbi[78]
  PIN xbi[79]
    DIRECTION INPUT ;
    USE SIGNAL ;
    PORT
      LAYER M5 ;
        RECT  56.352 0 56.376 0.192 ;
    END
  END xbi[79]
  PIN xbi[7]
    DIRECTION INPUT ;
    USE SIGNAL ;
    PORT
      LAYER M5 ;
        RECT  46.416 0 46.44 0.192 ;
    END
  END xbi[7]
  PIN xbi[80]
    DIRECTION INPUT ;
    USE SIGNAL ;
    PORT
      LAYER M3 ;
        RECT  56.484 0 56.502 0.144 ;
    END
  END xbi[80]
  PIN xbi[81]
    DIRECTION INPUT ;
    USE SIGNAL ;
    PORT
      LAYER M5 ;
        RECT  56.64 0 56.664 0.192 ;
    END
  END xbi[81]
  PIN xbi[82]
    DIRECTION INPUT ;
    USE SIGNAL ;
    PORT
      LAYER M3 ;
        RECT  56.772 0 56.79 0.144 ;
    END
  END xbi[82]
  PIN xbi[83]
    DIRECTION INPUT ;
    USE SIGNAL ;
    PORT
      LAYER M5 ;
        RECT  56.928 0 56.952 0.192 ;
    END
  END xbi[83]
  PIN xbi[84]
    DIRECTION INPUT ;
    USE SIGNAL ;
    PORT
      LAYER M3 ;
        RECT  57.06 0 57.078 0.144 ;
    END
  END xbi[84]
  PIN xbi[85]
    DIRECTION INPUT ;
    USE SIGNAL ;
    PORT
      LAYER M5 ;
        RECT  57.168 0 57.192 0.192 ;
    END
  END xbi[85]
  PIN xbi[86]
    DIRECTION INPUT ;
    USE SIGNAL ;
    PORT
      LAYER M3 ;
        RECT  57.312 0 57.33 0.144 ;
    END
  END xbi[86]
  PIN xbi[87]
    DIRECTION INPUT ;
    USE SIGNAL ;
    PORT
      LAYER M5 ;
        RECT  57.456 0 57.48 0.192 ;
    END
  END xbi[87]
  PIN xbi[88]
    DIRECTION INPUT ;
    USE SIGNAL ;
    PORT
      LAYER M3 ;
        RECT  57.6 0 57.618 0.144 ;
    END
  END xbi[88]
  PIN xbi[89]
    DIRECTION INPUT ;
    USE SIGNAL ;
    PORT
      LAYER M5 ;
        RECT  57.744 0 57.768 0.192 ;
    END
  END xbi[89]
  PIN xbi[8]
    DIRECTION INPUT ;
    USE SIGNAL ;
    PORT
      LAYER M3 ;
        RECT  46.584 0 46.602 0.144 ;
    END
  END xbi[8]
  PIN xbi[90]
    DIRECTION INPUT ;
    USE SIGNAL ;
    PORT
      LAYER M3 ;
        RECT  57.888 0 57.906 0.144 ;
    END
  END xbi[90]
  PIN xbi[91]
    DIRECTION INPUT ;
    USE SIGNAL ;
    PORT
      LAYER M5 ;
        RECT  58.032 0 58.056 0.192 ;
    END
  END xbi[91]
  PIN xbi[92]
    DIRECTION INPUT ;
    USE SIGNAL ;
    PORT
      LAYER M3 ;
        RECT  58.14 0 58.158 0.144 ;
    END
  END xbi[92]
  PIN xbi[93]
    DIRECTION INPUT ;
    USE SIGNAL ;
    PORT
      LAYER M5 ;
        RECT  58.272 0 58.296 0.192 ;
    END
  END xbi[93]
  PIN xbi[94]
    DIRECTION INPUT ;
    USE SIGNAL ;
    PORT
      LAYER M3 ;
        RECT  58.428 0 58.446 0.144 ;
    END
  END xbi[94]
  PIN xbi[95]
    DIRECTION INPUT ;
    USE SIGNAL ;
    PORT
      LAYER M5 ;
        RECT  58.56 0 58.584 0.192 ;
    END
  END xbi[95]
  PIN xbi[96]
    DIRECTION INPUT ;
    USE SIGNAL ;
    PORT
      LAYER M3 ;
        RECT  58.716 0 58.734 0.144 ;
    END
  END xbi[96]
  PIN xbi[97]
    DIRECTION INPUT ;
    USE SIGNAL ;
    PORT
      LAYER M5 ;
        RECT  58.848 0 58.872 0.192 ;
    END
  END xbi[97]
  PIN xbi[98]
    DIRECTION INPUT ;
    USE SIGNAL ;
    PORT
      LAYER M3 ;
        RECT  58.968 0 58.986 0.144 ;
    END
  END xbi[98]
  PIN xbi[99]
    DIRECTION INPUT ;
    USE SIGNAL ;
    PORT
      LAYER M5 ;
        RECT  59.136 0 59.16 0.192 ;
    END
  END xbi[99]
  PIN xbi[9]
    DIRECTION INPUT ;
    USE SIGNAL ;
    PORT
      LAYER M5 ;
        RECT  46.704 0 46.728 0.192 ;
    END
  END xbi[9]
  PIN VDD
    DIRECTION INOUT ;
    USE POWER ;
    PORT
      LAYER M5 ;
        RECT  80.892 2.151 81.012 28.089 ;
        RECT  78.192 2.151 78.312 28.089 ;
        RECT  75.492 2.151 75.612 28.089 ;
        RECT  72.792 2.151 72.912 28.089 ;
        RECT  70.092 2.151 70.212 28.089 ;
        RECT  67.392 2.151 67.512 28.089 ;
        RECT  64.692 2.151 64.812 28.089 ;
        RECT  61.992 2.151 62.112 28.089 ;
        RECT  59.292 2.151 59.412 28.089 ;
        RECT  56.592 2.151 56.712 28.089 ;
        RECT  53.892 2.151 54.012 28.089 ;
        RECT  51.192 2.151 51.312 28.089 ;
        RECT  48.492 2.151 48.612 28.089 ;
        RECT  45.792 2.151 45.912 28.089 ;
        RECT  43.092 2.151 43.212 28.089 ;
        RECT  40.392 2.151 40.512 28.089 ;
        RECT  37.692 2.151 37.812 28.089 ;
        RECT  34.992 2.151 35.112 28.089 ;
        RECT  32.292 2.151 32.412 28.089 ;
        RECT  29.592 2.151 29.712 28.089 ;
        RECT  26.892 2.151 27.012 28.089 ;
        RECT  24.192 2.151 24.312 28.089 ;
        RECT  21.492 2.151 21.612 28.089 ;
        RECT  18.792 2.151 18.912 28.089 ;
        RECT  16.092 2.151 16.212 28.089 ;
        RECT  13.392 2.151 13.512 28.089 ;
        RECT  10.692 2.151 10.812 28.089 ;
        RECT  7.992 2.151 8.112 28.089 ;
        RECT  5.292 2.151 5.412 28.089 ;
        RECT  2.592 2.151 2.712 28.089 ;
    END
  END VDD
  PIN VSS
    DIRECTION INOUT ;
    USE GROUND ;
    PORT
      LAYER M5 ;
        RECT  80.7 2.137 80.82 28.103 ;
        RECT  78 2.137 78.12 28.103 ;
        RECT  75.3 2.137 75.42 28.103 ;
        RECT  72.6 2.137 72.72 28.103 ;
        RECT  69.9 2.137 70.02 28.103 ;
        RECT  67.2 2.137 67.32 28.103 ;
        RECT  64.5 2.137 64.62 28.103 ;
        RECT  61.8 2.137 61.92 28.103 ;
        RECT  59.1 2.137 59.22 28.103 ;
        RECT  56.4 2.137 56.52 28.103 ;
        RECT  53.7 2.137 53.82 28.103 ;
        RECT  51 2.137 51.12 28.103 ;
        RECT  48.3 2.137 48.42 28.103 ;
        RECT  45.6 2.137 45.72 28.103 ;
        RECT  42.9 2.137 43.02 28.103 ;
        RECT  40.2 2.137 40.32 28.103 ;
        RECT  37.5 2.137 37.62 28.103 ;
        RECT  34.8 2.137 34.92 28.103 ;
        RECT  32.1 2.137 32.22 28.103 ;
        RECT  29.4 2.137 29.52 28.103 ;
        RECT  26.7 2.137 26.82 28.103 ;
        RECT  24 2.137 24.12 28.103 ;
        RECT  21.3 2.137 21.42 28.103 ;
        RECT  18.6 2.137 18.72 28.103 ;
        RECT  15.9 2.137 16.02 28.103 ;
        RECT  13.2 2.137 13.32 28.103 ;
        RECT  10.5 2.137 10.62 28.103 ;
        RECT  7.8 2.137 7.92 28.103 ;
        RECT  5.1 2.137 5.22 28.103 ;
        RECT  2.4 2.137 2.52 28.103 ;
    END
  END VSS
  # OT_OBS_CLOSED layer=M5 d_um=1.536 added=91
  OBS
    LAYER RVTN ;
     RECT  2.16 2.16 82.08 2.295 ;
     RECT  2.16 2.565 82.08 2.835 ;
     RECT  2.16 3.105 82.08 3.375 ;
     RECT  2.16 3.645 82.08 3.915 ;
     RECT  2.16 4.185 82.08 4.455 ;
     RECT  2.16 4.725 82.08 4.995 ;
     RECT  2.16 5.265 82.08 5.535 ;
     RECT  2.16 5.805 82.08 6.075 ;
     RECT  2.16 6.345 82.08 6.615 ;
     RECT  2.16 6.885 82.08 7.155 ;
     RECT  2.16 7.425 82.08 7.695 ;
     RECT  2.16 7.965 82.08 8.235 ;
     RECT  2.16 8.505 82.08 8.775 ;
     RECT  2.16 9.045 82.08 9.315 ;
     RECT  2.16 9.585 82.08 9.855 ;
     RECT  2.16 10.125 82.08 10.395 ;
     RECT  2.16 10.665 82.08 10.935 ;
     RECT  2.16 11.205 82.08 11.475 ;
     RECT  2.16 11.745 82.08 12.015 ;
     RECT  2.16 12.285 82.08 12.555 ;
     RECT  2.16 12.825 82.08 13.095 ;
     RECT  2.16 13.365 82.08 13.635 ;
     RECT  2.16 13.905 82.08 14.175 ;
     RECT  2.16 14.445 82.08 14.715 ;
     RECT  2.16 14.985 82.08 15.255 ;
     RECT  2.16 15.525 82.08 15.795 ;
     RECT  2.16 16.065 82.08 16.335 ;
     RECT  2.16 16.605 82.08 16.875 ;
     RECT  2.16 17.145 82.08 17.415 ;
     RECT  2.16 17.685 82.08 17.955 ;
     RECT  2.16 18.225 82.08 18.495 ;
     RECT  2.16 18.765 82.08 19.035 ;
     RECT  2.16 19.305 82.08 19.575 ;
     RECT  2.16 19.845 82.08 20.115 ;
     RECT  2.16 20.385 82.08 20.655 ;
     RECT  2.16 20.925 82.08 21.195 ;
     RECT  2.16 21.465 82.08 21.735 ;
     RECT  2.16 22.005 82.08 22.275 ;
     RECT  2.16 22.545 82.08 22.815 ;
     RECT  2.16 23.085 82.08 23.355 ;
     RECT  2.16 23.625 82.08 23.895 ;
     RECT  2.16 24.165 82.08 24.435 ;
     RECT  2.16 24.705 82.08 24.975 ;
     RECT  2.16 25.245 82.08 25.515 ;
     RECT  2.16 25.785 82.08 26.055 ;
     RECT  2.16 26.325 82.08 26.595 ;
     RECT  2.16 26.865 82.08 27.135 ;
     RECT  2.16 27.405 82.08 27.675 ;
     RECT  2.16 27.945 82.08 28.08 ;
    LAYER RVTP ;
     RECT  2.16 2.295 82.08 2.565 ;
     RECT  2.16 2.835 82.08 3.105 ;
     RECT  2.16 3.375 82.08 3.645 ;
     RECT  2.16 3.915 82.08 4.185 ;
     RECT  2.16 4.455 82.08 4.725 ;
     RECT  2.16 4.995 82.08 5.265 ;
     RECT  2.16 5.535 82.08 5.805 ;
     RECT  2.16 6.075 82.08 6.345 ;
     RECT  2.16 6.615 82.08 6.885 ;
     RECT  2.16 7.155 82.08 7.425 ;
     RECT  2.16 7.695 82.08 7.965 ;
     RECT  2.16 8.235 82.08 8.505 ;
     RECT  2.16 8.775 82.08 9.045 ;
     RECT  2.16 9.315 82.08 9.585 ;
     RECT  2.16 9.855 82.08 10.125 ;
     RECT  2.16 10.395 82.08 10.665 ;
     RECT  2.16 10.935 82.08 11.205 ;
     RECT  2.16 11.475 82.08 11.745 ;
     RECT  2.16 12.015 82.08 12.285 ;
     RECT  2.16 12.555 82.08 12.825 ;
     RECT  2.16 13.095 82.08 13.365 ;
     RECT  2.16 13.635 82.08 13.905 ;
     RECT  2.16 14.175 82.08 14.445 ;
     RECT  2.16 14.715 82.08 14.985 ;
     RECT  2.16 15.255 82.08 15.525 ;
     RECT  2.16 15.795 82.08 16.065 ;
     RECT  2.16 16.335 82.08 16.605 ;
     RECT  2.16 16.875 82.08 17.145 ;
     RECT  2.16 17.415 82.08 17.685 ;
     RECT  2.16 17.955 82.08 18.225 ;
     RECT  2.16 18.495 82.08 18.765 ;
     RECT  2.16 19.035 82.08 19.305 ;
     RECT  2.16 19.575 82.08 19.845 ;
     RECT  2.16 20.115 82.08 20.385 ;
     RECT  2.16 20.655 82.08 20.925 ;
     RECT  2.16 21.195 82.08 21.465 ;
     RECT  2.16 21.735 82.08 22.005 ;
     RECT  2.16 22.275 82.08 22.545 ;
     RECT  2.16 22.815 82.08 23.085 ;
     RECT  2.16 23.355 82.08 23.625 ;
     RECT  2.16 23.895 82.08 24.165 ;
     RECT  2.16 24.435 82.08 24.705 ;
     RECT  2.16 24.975 82.08 25.245 ;
     RECT  2.16 25.515 82.08 25.785 ;
     RECT  2.16 26.055 82.08 26.325 ;
     RECT  2.16 26.595 82.08 26.865 ;
     RECT  2.16 27.135 82.08 27.405 ;
     RECT  2.16 27.675 82.08 27.945 ;
    LAYER M1 ;
     RECT  2.16 2.151 82.08 28.089 ;
    LAYER M2 ;
     RECT  2.16 2.151 2.371 28.089 ;
     RECT  2.371 2.151 2.543 28.17 ;
     RECT  2.543 2.151 4.027 28.089 ;
     RECT  4.603 30.15 4.639 30.168 ;
     RECT  4.639 30.078 4.739 30.168 ;
     RECT  5.215 0.144 5.459 0.162 ;
     RECT  4.027 2.106 5.531 28.089 ;
     RECT  6.547 29.034 7.331 29.052 ;
     RECT  6.871 0.144 7.727 0.162 ;
     RECT  8.203 29.034 8.555 29.052 ;
     RECT  9.283 0.216 9.355 0.234 ;
     RECT  9.355 0.144 9.635 0.234 ;
     RECT  9.355 29.034 9.859 29.052 ;
     RECT  9.859 28.962 9.923 29.052 ;
     RECT  9.923 28.962 10.211 28.98 ;
     RECT  5.531 2.151 10.975 28.089 ;
     RECT  10.975 2.151 11.147 28.548 ;
     RECT  9.635 0.144 11.363 0.162 ;
     RECT  11.263 29.034 11.363 29.052 ;
     RECT  12.919 29.736 13.091 29.754 ;
     RECT  13.207 29.034 13.847 29.052 ;
     RECT  12.379 0.144 13.955 0.162 ;
     RECT  13.963 0.216 14.063 0.234 ;
     RECT  14.863 0.144 15.403 0.162 ;
     RECT  11.147 2.151 15.691 28.089 ;
     RECT  15.403 0.144 15.719 0.324 ;
     RECT  15.691 2.151 15.943 28.134 ;
     RECT  15.719 0.144 15.971 0.279 ;
     RECT  15.943 2.151 16.079 28.17 ;
     RECT  15.971 0.144 16.619 0.162 ;
     RECT  16.771 29.034 17.051 29.052 ;
     RECT  16.079 2.151 17.059 28.089 ;
     RECT  17.059 2.151 17.555 28.134 ;
     RECT  18.427 29.034 18.815 29.052 ;
     RECT  19.687 29.034 19.759 29.052 ;
     RECT  17.743 0.144 19.823 0.162 ;
     RECT  19.759 28.962 19.859 29.052 ;
     RECT  20.911 0.144 21.047 0.162 ;
     RECT  19.859 29.034 21.083 29.052 ;
     RECT  21.091 1.152 21.515 1.17 ;
     RECT  17.555 2.151 21.739 28.089 ;
     RECT  21.739 2.151 22.091 28.134 ;
     RECT  22.027 0.144 23.035 0.162 ;
     RECT  22.091 2.151 23.143 28.089 ;
     RECT  23.035 0.144 23.171 0.198 ;
     RECT  23.143 2.151 23.243 28.134 ;
     RECT  22.315 29.034 23.683 29.052 ;
     RECT  23.683 29.034 23.783 29.754 ;
     RECT  24.223 1.152 24.467 1.17 ;
     RECT  23.783 29.034 24.467 29.052 ;
     RECT  23.171 0.144 24.511 0.162 ;
     RECT  24.511 0.144 24.647 0.234 ;
     RECT  24.647 0.144 25.043 0.162 ;
     RECT  26.023 28.836 26.123 29.052 ;
     RECT  26.123 28.836 26.195 28.944 ;
     RECT  23.243 2.151 26.707 28.089 ;
     RECT  26.707 2.151 27.239 28.17 ;
     RECT  26.563 0.144 28.175 0.162 ;
     RECT  27.679 29.034 28.967 29.052 ;
     RECT  27.239 2.151 29.479 28.089 ;
     RECT  28.903 0.144 29.731 0.162 ;
     RECT  29.479 2.151 29.975 28.17 ;
     RECT  29.731 0.144 30.047 0.324 ;
     RECT  30.047 0.144 30.119 0.162 ;
     RECT  30.019 29.646 30.479 29.664 ;
     RECT  30.559 29.736 30.695 29.754 ;
     RECT  29.975 2.151 32.215 28.089 ;
     RECT  32.215 2.151 32.459 28.17 ;
     RECT  32.459 2.151 33.331 28.089 ;
     RECT  33.331 2.151 33.467 28.548 ;
     RECT  33.467 2.151 34.699 28.089 ;
     RECT  34.699 1.728 35.159 28.089 ;
     RECT  30.847 0.144 35.203 0.162 ;
     RECT  35.203 0.144 35.843 0.234 ;
     RECT  35.843 0.144 36.995 0.162 ;
     RECT  34.627 29.034 37.031 29.052 ;
     RECT  35.159 2.151 37.399 28.089 ;
     RECT  37.399 2.151 37.499 28.278 ;
     RECT  37.499 2.151 38.011 28.089 ;
     RECT  38.011 1.728 38.255 28.089 ;
     RECT  38.255 2.151 39.163 28.089 ;
     RECT  39.163 2.106 39.667 28.089 ;
     RECT  37.723 0.144 40.055 0.162 ;
     RECT  39.667 1.152 40.207 1.242 ;
     RECT  39.667 2.106 40.207 28.134 ;
     RECT  40.207 1.152 40.451 28.17 ;
     RECT  40.451 1.152 40.595 28.089 ;
     RECT  40.595 1.728 40.775 28.089 ;
     RECT  40.783 29.196 40.955 29.214 ;
     RECT  41.035 0.144 42.071 0.162 ;
     RECT  41.035 29.034 42.143 29.052 ;
     RECT  40.775 2.151 42.979 28.089 ;
     RECT  42.979 0.306 43.195 0.324 ;
     RECT  42.979 2.151 43.267 28.17 ;
     RECT  43.195 0.144 43.295 0.324 ;
     RECT  43.267 2.151 43.583 28.242 ;
     RECT  43.295 0.144 44.447 0.162 ;
     RECT  43.583 2.151 44.635 28.089 ;
     RECT  44.635 1.728 45.167 28.089 ;
     RECT  45.167 1.8 45.203 28.089 ;
     RECT  45.175 0.144 45.751 0.162 ;
     RECT  44.635 29.034 45.751 29.052 ;
     RECT  45.751 0.144 46.031 0.324 ;
     RECT  45.751 28.881 46.067 29.052 ;
     RECT  46.067 28.926 46.175 29.052 ;
     RECT  46.579 29.196 47.255 29.214 ;
     RECT  45.203 2.151 47.299 28.089 ;
     RECT  47.299 2.151 47.687 28.134 ;
     RECT  47.687 2.151 48.235 28.089 ;
     RECT  48.235 1.728 48.695 28.089 ;
     RECT  48.487 29.034 48.775 29.052 ;
     RECT  48.775 28.962 49.559 29.052 ;
     RECT  46.031 0.144 49.703 0.162 ;
     RECT  48.695 2.151 49.999 28.089 ;
     RECT  49.999 2.151 50.711 28.134 ;
     RECT  49.559 29.034 50.999 29.052 ;
     RECT  50.711 2.151 51.799 28.089 ;
     RECT  50.899 0.144 51.827 0.162 ;
     RECT  51.799 2.151 51.971 28.134 ;
     RECT  52.627 29.034 52.763 29.052 ;
     RECT  51.971 2.151 53.167 28.089 ;
     RECT  53.167 2.151 53.375 28.548 ;
     RECT  53.671 29.034 53.771 29.052 ;
     RECT  53.375 2.151 53.995 28.089 ;
     RECT  53.995 1.728 54.167 28.089 ;
     RECT  52.627 0.144 54.995 0.162 ;
     RECT  54.167 2.151 55.111 28.089 ;
     RECT  55.111 1.728 55.607 28.089 ;
     RECT  55.111 29.034 56.767 29.052 ;
     RECT  56.767 28.998 56.939 29.052 ;
     RECT  56.939 29.034 56.975 29.052 ;
     RECT  55.607 2.151 57.055 28.089 ;
     RECT  57.055 2.106 57.307 28.089 ;
     RECT  55.939 0.144 57.407 0.162 ;
     RECT  57.307 2.106 57.515 28.134 ;
     RECT  57.515 2.106 57.551 28.089 ;
     RECT  57.551 2.151 59.539 28.089 ;
     RECT  59.539 2.151 59.855 28.629 ;
     RECT  60.079 29.736 60.359 29.754 ;
     RECT  59.855 2.151 60.619 28.134 ;
     RECT  60.619 2.151 60.827 28.629 ;
     RECT  60.827 2.151 60.935 28.134 ;
     RECT  62.563 29.034 62.663 29.052 ;
     RECT  60.619 0.144 63.239 0.162 ;
     RECT  63.643 29.034 63.743 29.052 ;
     RECT  60.935 2.151 64.759 28.089 ;
     RECT  64.759 1.728 65.147 28.089 ;
     RECT  65.147 2.151 65.299 28.089 ;
     RECT  65.299 2.151 65.471 28.548 ;
     RECT  64.219 0.144 65.875 0.162 ;
     RECT  65.875 0.144 65.975 0.234 ;
     RECT  65.975 0.144 66.263 0.162 ;
     RECT  65.471 2.151 66.523 28.089 ;
     RECT  66.523 2.106 67.199 28.089 ;
     RECT  67.199 2.151 67.243 28.089 ;
     RECT  67.243 2.151 67.783 28.17 ;
     RECT  67.783 2.151 68.287 28.476 ;
     RECT  68.287 2.151 68.387 29.052 ;
     RECT  68.387 29.034 68.711 29.052 ;
     RECT  68.387 2.151 70.015 28.089 ;
     RECT  70.015 2.151 70.367 28.17 ;
     RECT  69.655 29.034 70.547 29.052 ;
     RECT  67.063 0.144 70.583 0.162 ;
     RECT  71.275 29.034 71.411 29.052 ;
     RECT  71.599 0.144 71.699 0.162 ;
     RECT  70.367 2.151 71.887 28.089 ;
     RECT  71.887 2.151 72.239 28.134 ;
     RECT  72.239 2.151 72.751 28.089 ;
     RECT  72.751 1.728 73.103 28.089 ;
     RECT  72.751 29.034 74.003 29.052 ;
     RECT  73.039 0.144 74.155 0.162 ;
     RECT  74.155 0.144 74.435 0.324 ;
     RECT  74.435 0.144 75.011 0.162 ;
     RECT  73.103 2.151 75.703 28.089 ;
     RECT  75.523 28.962 75.703 28.98 ;
     RECT  75.703 2.151 75.775 29.052 ;
     RECT  75.775 1.728 75.803 29.052 ;
     RECT  75.803 1.728 75.875 28.476 ;
     RECT  75.875 2.151 76.127 28.476 ;
     RECT  76.243 0.144 76.379 0.162 ;
     RECT  76.603 29.034 76.883 29.052 ;
     RECT  76.127 2.151 78.007 28.089 ;
     RECT  78.007 2.07 78.259 28.17 ;
     RECT  78.259 2.07 78.403 28.242 ;
     RECT  78.403 2.07 78.539 28.278 ;
     RECT  78.539 2.151 78.575 28.278 ;
     RECT  78.575 2.151 78.611 28.242 ;
     RECT  77.179 0.144 78.863 0.162 ;
     RECT  79.087 29.034 79.187 29.052 ;
     RECT  78.611 2.151 79.519 28.089 ;
     RECT  79.519 2.106 79.799 28.089 ;
     RECT  79.799 2.151 80.203 28.089 ;
     RECT  79.591 0.144 80.419 0.162 ;
     RECT  80.419 0.144 80.491 0.234 ;
     RECT  80.491 0.144 80.591 0.324 ;
     RECT  80.203 2.151 80.671 28.134 ;
     RECT  80.591 0.216 80.771 0.324 ;
     RECT  80.771 0.306 81.059 0.324 ;
     RECT  80.671 2.151 81.319 28.17 ;
     RECT  81.319 1.728 81.455 28.629 ;
     RECT  81.455 1.728 81.527 28.089 ;
     RECT  81.571 0.144 81.743 0.162 ;
     RECT  81.527 2.151 82.08 28.089 ;
     RECT  82.08 22.05 82.103 23.454 ;
     RECT  82.08 26.838 82.103 27.774 ;
     RECT  82.103 22.05 82.139 23.184 ;
     RECT  82.103 27.648 82.139 27.774 ;
     RECT  82.103 26.838 82.175 26.856 ;
     RECT  82.139 22.05 82.211 22.806 ;
     RECT  82.139 27.72 82.211 27.774 ;
     RECT  82.08 24.246 82.247 25.236 ;
     RECT  82.211 22.05 82.283 22.068 ;
     RECT  82.211 27.756 82.283 27.774 ;
     RECT  82.08 20.196 82.319 21.186 ;
     RECT  82.247 24.246 82.319 24.426 ;
     RECT  82.319 20.196 82.355 20.484 ;
     RECT  82.247 25.218 82.355 25.236 ;
     RECT  82.355 20.466 82.391 20.484 ;
     RECT  82.319 24.408 82.391 24.426 ;
    LAYER M3 ;
     RECT  4.41 0.108 4.644 0.144 ;
     RECT  4.662 0.108 4.932 0.144 ;
     RECT  4.95 0.108 5.22 0.144 ;
     RECT  5.238 0.108 5.472 0.144 ;
     RECT  5.49 0.108 5.76 0.144 ;
     RECT  5.778 0.108 6.048 0.144 ;
     RECT  6.066 0.108 6.3 0.144 ;
     RECT  6.318 0.108 6.588 0.144 ;
     RECT  6.606 0.108 6.876 0.144 ;
     RECT  6.894 0.108 7.128 0.144 ;
     RECT  7.146 0.108 7.416 0.144 ;
     RECT  7.434 0.108 7.704 0.144 ;
     RECT  7.722 0.108 7.956 0.144 ;
     RECT  7.974 0.108 8.244 0.144 ;
     RECT  8.262 0.108 8.532 0.144 ;
     RECT  8.55 0.108 8.784 0.144 ;
     RECT  8.802 0.108 9.072 0.144 ;
     RECT  9.09 0.108 9.36 0.144 ;
     RECT  9.378 0.108 9.612 0.144 ;
     RECT  9.63 0.108 9.9 0.144 ;
     RECT  9.918 0.108 10.188 0.144 ;
     RECT  10.206 0.108 10.44 0.144 ;
     RECT  10.458 0.108 10.728 0.144 ;
     RECT  10.746 0.108 10.98 0.144 ;
     RECT  10.998 0.108 11.268 0.144 ;
     RECT  11.286 0.108 11.556 0.144 ;
     RECT  11.574 0.108 11.808 0.144 ;
     RECT  11.826 0.108 12.096 0.144 ;
     RECT  12.114 0.108 12.384 0.144 ;
     RECT  12.402 0.108 12.636 0.144 ;
     RECT  12.654 0.108 12.924 0.144 ;
     RECT  12.942 0.108 13.212 0.144 ;
     RECT  13.23 0.108 13.464 0.144 ;
     RECT  13.482 0.108 13.752 0.144 ;
     RECT  13.77 0.108 14.04 0.144 ;
     RECT  14.058 0.108 14.292 0.144 ;
     RECT  14.31 0.108 14.58 0.144 ;
     RECT  14.598 0.108 14.868 0.144 ;
     RECT  14.886 0.108 15.12 0.144 ;
     RECT  15.138 0.108 15.408 0.144 ;
     RECT  15.426 0.108 15.696 0.144 ;
     RECT  15.714 0.108 15.948 0.144 ;
     RECT  15.966 0.108 16.236 0.144 ;
     RECT  16.254 0.108 16.524 0.144 ;
     RECT  16.542 0.108 16.776 0.144 ;
     RECT  16.794 0.108 17.064 0.144 ;
     RECT  17.082 0.108 17.352 0.144 ;
     RECT  17.37 0.108 17.604 0.144 ;
     RECT  17.622 0.108 17.892 0.144 ;
     RECT  17.91 0.108 18.18 0.144 ;
     RECT  18.198 0.108 18.432 0.144 ;
     RECT  18.45 0.108 18.72 0.144 ;
     RECT  18.738 0.108 19.008 0.144 ;
     RECT  19.026 0.108 19.26 0.144 ;
     RECT  19.278 0.108 19.548 0.144 ;
     RECT  19.566 0.108 19.836 0.144 ;
     RECT  19.854 0.108 20.088 0.144 ;
     RECT  20.106 0.108 20.376 0.144 ;
     RECT  20.394 0.108 20.664 0.144 ;
     RECT  20.682 0.108 20.916 0.144 ;
     RECT  20.934 0.108 21.204 0.144 ;
     RECT  21.222 0.108 21.492 0.144 ;
     RECT  21.51 0.108 21.744 0.144 ;
     RECT  21.762 0.108 22.032 0.144 ;
     RECT  22.05 0.108 22.32 0.144 ;
     RECT  22.338 0.108 22.572 0.144 ;
     RECT  22.59 0.108 22.86 0.144 ;
     RECT  22.878 0.108 23.148 0.144 ;
     RECT  23.166 0.108 23.4 0.144 ;
     RECT  23.418 0.108 23.688 0.144 ;
     RECT  23.706 0.108 23.94 0.144 ;
     RECT  23.958 0.108 24.228 0.144 ;
     RECT  24.246 0.108 24.516 0.144 ;
     RECT  24.534 0.108 24.768 0.144 ;
     RECT  24.786 0.108 25.056 0.144 ;
     RECT  25.074 0.108 25.344 0.144 ;
     RECT  25.362 0.108 25.596 0.144 ;
     RECT  25.614 0.108 25.884 0.144 ;
     RECT  25.902 0.108 26.172 0.144 ;
     RECT  26.19 0.108 26.424 0.144 ;
     RECT  26.442 0.108 26.712 0.144 ;
     RECT  26.73 0.108 27 0.144 ;
     RECT  27.018 0.108 27.252 0.144 ;
     RECT  27.27 0.108 27.54 0.144 ;
     RECT  27.558 0.108 27.828 0.144 ;
     RECT  27.846 0.108 28.08 0.144 ;
     RECT  28.098 0.108 28.368 0.144 ;
     RECT  28.386 0.108 28.656 0.144 ;
     RECT  28.674 0.108 28.908 0.144 ;
     RECT  28.926 0.108 29.196 0.144 ;
     RECT  29.214 0.108 29.484 0.144 ;
     RECT  29.502 0.108 29.736 0.144 ;
     RECT  29.754 0.108 30.024 0.144 ;
     RECT  30.042 0.108 30.312 0.144 ;
     RECT  30.33 0.108 30.564 0.144 ;
     RECT  30.582 0.108 30.852 0.144 ;
     RECT  30.87 0.108 31.14 0.144 ;
     RECT  31.158 0.108 31.392 0.144 ;
     RECT  31.41 0.108 31.68 0.144 ;
     RECT  31.698 0.108 31.968 0.144 ;
     RECT  31.986 0.108 32.22 0.144 ;
     RECT  32.238 0.108 32.508 0.144 ;
     RECT  32.526 0.108 32.796 0.144 ;
     RECT  32.814 0.108 33.048 0.144 ;
     RECT  33.066 0.108 33.336 0.144 ;
     RECT  33.354 0.108 33.624 0.144 ;
     RECT  33.642 0.108 33.876 0.144 ;
     RECT  33.894 0.108 34.164 0.144 ;
     RECT  34.182 0.108 34.452 0.144 ;
     RECT  34.47 0.108 34.704 0.144 ;
     RECT  34.722 0.108 34.992 0.144 ;
     RECT  35.01 0.108 35.28 0.144 ;
     RECT  35.298 0.108 35.532 0.144 ;
     RECT  35.55 0.108 35.82 0.144 ;
     RECT  35.838 0.108 36.108 0.144 ;
     RECT  36.126 0.108 36.36 0.144 ;
     RECT  36.378 0.108 36.648 0.144 ;
     RECT  36.666 0.108 36.9 0.144 ;
     RECT  36.918 0.108 37.188 0.144 ;
     RECT  37.206 0.108 37.476 0.144 ;
     RECT  37.494 0.108 37.728 0.144 ;
     RECT  37.746 0.108 38.016 0.144 ;
     RECT  38.034 0.108 38.304 0.144 ;
     RECT  38.322 0.108 38.556 0.144 ;
     RECT  38.574 0.108 38.844 0.144 ;
     RECT  38.862 0.108 39.132 0.144 ;
     RECT  39.15 0.108 39.384 0.144 ;
     RECT  39.402 0.108 39.672 0.144 ;
     RECT  39.69 0.108 39.96 0.144 ;
     RECT  39.978 0.108 40.212 0.144 ;
     RECT  40.23 0.108 40.5 0.144 ;
     RECT  40.518 0.108 40.788 0.144 ;
     RECT  40.806 0.108 41.04 0.144 ;
     RECT  41.058 0.108 41.328 0.144 ;
     RECT  41.346 0.108 41.616 0.144 ;
     RECT  41.634 0.108 41.868 0.144 ;
     RECT  41.886 0.108 42.156 0.144 ;
     RECT  42.174 0.108 42.444 0.144 ;
     RECT  42.462 0.108 42.696 0.144 ;
     RECT  42.714 0.108 42.984 0.144 ;
     RECT  43.002 0.108 43.272 0.144 ;
     RECT  43.29 0.108 43.524 0.144 ;
     RECT  43.542 0.108 43.812 0.144 ;
     RECT  43.83 0.108 44.1 0.144 ;
     RECT  44.118 0.108 44.352 0.144 ;
     RECT  44.37 0.108 44.64 0.144 ;
     RECT  44.658 0.108 44.928 0.144 ;
     RECT  44.946 0.108 45.18 0.144 ;
     RECT  45.198 0.108 45.468 0.144 ;
     RECT  45.486 0.108 45.756 0.144 ;
     RECT  45.774 0.108 46.008 0.144 ;
     RECT  46.026 0.108 46.296 0.144 ;
     RECT  46.314 0.108 46.584 0.144 ;
     RECT  46.602 0.108 46.836 0.144 ;
     RECT  46.854 0.108 47.124 0.144 ;
     RECT  47.142 0.108 47.412 0.144 ;
     RECT  47.43 0.108 47.664 0.144 ;
     RECT  47.682 0.108 47.952 0.144 ;
     RECT  47.97 0.108 48.24 0.144 ;
     RECT  48.258 0.108 48.492 0.144 ;
     RECT  48.51 0.108 48.78 0.144 ;
     RECT  48.798 0.108 49.068 0.144 ;
     RECT  49.086 0.108 49.32 0.144 ;
     RECT  49.338 0.108 49.608 0.144 ;
     RECT  49.626 0.108 49.86 0.144 ;
     RECT  49.878 0.108 50.148 0.144 ;
     RECT  50.166 0.108 50.436 0.144 ;
     RECT  50.454 0.108 50.688 0.144 ;
     RECT  50.706 0.108 50.976 0.144 ;
     RECT  50.994 0.108 51.264 0.144 ;
     RECT  51.282 0.108 51.516 0.144 ;
     RECT  51.534 0.108 51.804 0.144 ;
     RECT  51.822 0.108 52.092 0.144 ;
     RECT  52.11 0.108 52.344 0.144 ;
     RECT  52.362 0.108 52.632 0.144 ;
     RECT  52.65 0.108 52.92 0.144 ;
     RECT  52.938 0.108 53.172 0.144 ;
     RECT  53.19 0.108 53.46 0.144 ;
     RECT  53.478 0.108 53.748 0.144 ;
     RECT  53.766 0.108 54 0.144 ;
     RECT  54.018 0.108 54.288 0.144 ;
     RECT  54.306 0.108 54.576 0.144 ;
     RECT  54.594 0.108 54.828 0.144 ;
     RECT  54.846 0.108 55.116 0.144 ;
     RECT  55.134 0.108 55.404 0.144 ;
     RECT  55.422 0.108 55.656 0.144 ;
     RECT  55.674 0.108 55.944 0.144 ;
     RECT  55.962 0.108 56.232 0.144 ;
     RECT  56.25 0.108 56.484 0.144 ;
     RECT  56.502 0.108 56.772 0.144 ;
     RECT  56.79 0.108 57.06 0.144 ;
     RECT  57.078 0.108 57.312 0.144 ;
     RECT  57.33 0.108 57.6 0.144 ;
     RECT  57.618 0.108 57.888 0.144 ;
     RECT  57.906 0.108 58.14 0.144 ;
     RECT  58.158 0.108 58.428 0.144 ;
     RECT  58.446 0.108 58.716 0.144 ;
     RECT  58.734 0.108 58.968 0.144 ;
     RECT  58.986 0.108 59.256 0.144 ;
     RECT  59.274 0.108 59.544 0.144 ;
     RECT  59.562 0.108 59.796 0.144 ;
     RECT  59.814 0.108 60.084 0.144 ;
     RECT  60.102 0.108 60.372 0.144 ;
     RECT  60.39 0.108 60.624 0.144 ;
     RECT  60.642 0.108 60.912 0.144 ;
     RECT  60.93 0.108 61.2 0.144 ;
     RECT  61.218 0.108 61.452 0.144 ;
     RECT  61.47 0.108 61.74 0.144 ;
     RECT  61.758 0.108 62.028 0.144 ;
     RECT  62.046 0.108 62.28 0.144 ;
     RECT  62.298 0.108 62.568 0.144 ;
     RECT  62.586 0.108 62.82 0.144 ;
     RECT  62.838 0.108 63.108 0.144 ;
     RECT  63.126 0.108 63.396 0.144 ;
     RECT  63.414 0.108 63.648 0.144 ;
     RECT  63.666 0.108 63.936 0.144 ;
     RECT  63.954 0.108 64.224 0.144 ;
     RECT  64.242 0.108 64.476 0.144 ;
     RECT  64.494 0.108 64.764 0.144 ;
     RECT  64.782 0.108 65.052 0.144 ;
     RECT  65.07 0.108 65.304 0.144 ;
     RECT  65.322 0.108 65.592 0.144 ;
     RECT  65.61 0.108 65.88 0.144 ;
     RECT  65.898 0.108 66.132 0.144 ;
     RECT  66.15 0.108 66.42 0.144 ;
     RECT  66.438 0.108 66.708 0.144 ;
     RECT  66.726 0.108 66.96 0.144 ;
     RECT  66.978 0.108 67.248 0.144 ;
     RECT  67.266 0.108 67.536 0.144 ;
     RECT  67.554 0.108 67.788 0.144 ;
     RECT  67.806 0.108 68.076 0.144 ;
     RECT  68.094 0.108 68.364 0.144 ;
     RECT  68.382 0.108 68.616 0.144 ;
     RECT  68.634 0.108 68.904 0.144 ;
     RECT  68.922 0.108 69.192 0.144 ;
     RECT  69.21 0.108 69.444 0.144 ;
     RECT  69.462 0.108 69.732 0.144 ;
     RECT  69.75 0.108 70.02 0.144 ;
     RECT  70.038 0.108 70.272 0.144 ;
     RECT  70.29 0.108 70.56 0.144 ;
     RECT  70.578 0.108 70.848 0.144 ;
     RECT  70.866 0.108 71.1 0.144 ;
     RECT  71.118 0.108 71.388 0.144 ;
     RECT  71.406 0.108 71.676 0.144 ;
     RECT  71.694 0.108 71.928 0.144 ;
     RECT  71.946 0.108 72.216 0.144 ;
     RECT  72.234 0.108 72.504 0.144 ;
     RECT  72.522 0.108 72.756 0.144 ;
     RECT  72.774 0.108 73.044 0.144 ;
     RECT  73.062 0.108 73.332 0.144 ;
     RECT  73.35 0.108 73.584 0.144 ;
     RECT  73.602 0.108 73.872 0.144 ;
     RECT  73.89 0.108 74.16 0.144 ;
     RECT  74.178 0.108 74.412 0.144 ;
     RECT  74.43 0.108 74.7 0.144 ;
     RECT  74.718 0.108 74.988 0.144 ;
     RECT  75.006 0.108 75.24 0.144 ;
     RECT  75.258 0.108 75.528 0.144 ;
     RECT  75.546 0.108 75.78 0.144 ;
     RECT  75.798 0.108 76.068 0.144 ;
     RECT  76.086 0.108 76.356 0.144 ;
     RECT  76.374 0.108 76.608 0.144 ;
     RECT  76.626 0.108 76.896 0.144 ;
     RECT  76.914 0.108 77.184 0.144 ;
     RECT  77.202 0.108 77.436 0.144 ;
     RECT  77.454 0.108 77.724 0.144 ;
     RECT  77.742 0.108 78.012 0.144 ;
     RECT  78.03 0.108 78.264 0.144 ;
     RECT  78.282 0.108 78.552 0.144 ;
     RECT  78.57 0.108 78.84 0.144 ;
     RECT  78.858 0.108 79.092 0.144 ;
     RECT  79.11 0.108 79.38 0.144 ;
     RECT  79.398 0.108 79.668 0.144 ;
     RECT  79.686 0.108 79.92 0.144 ;
     RECT  79.938 0.108 80.208 0.144 ;
     RECT  80.226 0.108 80.496 0.144 ;
     RECT  80.514 0.108 80.748 0.144 ;
     RECT  80.766 0.108 81.036 0.144 ;
     RECT  81.054 0.108 81.324 0.144 ;
     RECT  81.342 0.108 81.576 0.144 ;
     RECT  81.594 0.108 81.864 0.144 ;
     RECT  4.392 0.144 81.882 0.284 ;
     RECT  16.452 0.284 81.882 0.329 ;
     RECT  16.452 0.329 29.286 1.175 ;
     RECT  4.392 0.284 15.714 1.723 ;
     RECT  16.452 1.175 23.706 1.723 ;
     RECT  24.444 1.175 29.286 1.723 ;
     RECT  30.024 0.329 80.586 1.723 ;
     RECT  4.392 1.723 23.706 2.101 ;
     RECT  4.032 2.101 23.706 2.143 ;
     RECT  24.444 1.723 80.586 2.143 ;
     RECT  81.324 0.329 81.882 2.143 ;
     RECT  2.232 1.723 2.826 2.263 ;
     RECT  2.232 2.263 2.862 2.461 ;
     RECT  2.232 2.461 2.934 2.489 ;
     RECT  2.415 2.489 2.934 2.605 ;
     RECT  4.032 2.143 81.882 2.605 ;
     RECT  2.415 2.605 81.882 3.181 ;
     RECT  2.415 3.181 82.062 3.335 ;
     RECT  2.415 3.335 47.322 3.407 ;
     RECT  42.84 3.407 47.322 3.437 ;
     RECT  45.468 3.437 47.322 3.605 ;
     RECT  2.415 3.407 41.922 4.117 ;
     RECT  2.34 4.117 41.922 4.451 ;
     RECT  2.415 4.451 41.922 6.845 ;
     RECT  45.615 3.605 47.322 6.845 ;
     RECT  2.415 6.845 9.414 10.049 ;
     RECT  42.84 3.437 44.622 11.419 ;
     RECT  42.84 11.419 44.658 11.911 ;
     RECT  10.188 6.845 41.922 11.995 ;
     RECT  42.84 11.911 44.766 11.995 ;
     RECT  45.615 6.845 46.206 11.995 ;
     RECT  46.98 6.845 47.322 11.995 ;
     RECT  10.188 11.995 47.322 12.523 ;
     RECT  48.06 3.335 82.062 12.523 ;
     RECT  10.188 12.523 82.062 13.055 ;
     RECT  42.84 13.055 82.062 14.045 ;
     RECT  45.432 14.045 82.062 14.243 ;
     RECT  10.188 13.055 41.922 14.251 ;
     RECT  42.84 14.045 44.622 14.251 ;
     RECT  2.415 10.049 2.934 14.369 ;
     RECT  45.432 14.243 46.206 14.405 ;
     RECT  3.672 10.049 9.414 14.521 ;
     RECT  10.188 14.251 44.622 14.521 ;
     RECT  3.672 14.521 44.622 14.813 ;
     RECT  10.188 14.813 44.622 15.101 ;
     RECT  2.415 14.369 2.898 15.331 ;
     RECT  3.672 14.813 9.414 15.331 ;
     RECT  46.98 14.243 82.062 15.389 ;
     RECT  2.415 15.331 9.414 16.105 ;
     RECT  2.376 16.105 9.414 16.123 ;
     RECT  2.304 16.123 9.414 16.565 ;
     RECT  10.188 15.101 41.922 18.805 ;
     RECT  46.98 15.389 47.322 18.805 ;
     RECT  48.06 15.389 82.062 18.805 ;
     RECT  46.98 18.805 82.062 20.191 ;
     RECT  46.98 20.191 82.35 20.461 ;
     RECT  45.615 14.405 46.206 21.091 ;
     RECT  46.98 20.461 82.386 21.091 ;
     RECT  45.54 21.091 82.386 21.115 ;
     RECT  42.84 15.101 44.622 21.163 ;
     RECT  45.396 21.115 82.386 21.163 ;
     RECT  10.188 18.805 42.102 21.211 ;
     RECT  42.84 21.163 82.386 21.211 ;
     RECT  2.415 16.565 9.414 22.027 ;
     RECT  10.188 21.211 82.386 22.027 ;
     RECT  2.415 22.027 82.386 24.431 ;
     RECT  2.415 24.431 82.35 25.015 ;
     RECT  2.376 25.015 82.35 25.241 ;
     RECT  2.376 25.241 82.278 27.715 ;
     RECT  2.304 27.715 82.278 27.779 ;
     RECT  2.304 27.779 82.026 27.913 ;
     RECT  2.232 27.913 82.026 27.941 ;
     RECT  4.284 27.941 82.026 27.977 ;
     RECT  4.284 27.977 81.882 29.069 ;
     RECT  2.232 27.941 3.402 30.096 ;
     RECT  2.25 30.096 2.52 30.108 ;
     RECT  2.538 30.096 2.808 30.108 ;
     RECT  2.826 30.096 3.096 30.108 ;
     RECT  3.114 30.096 3.384 30.108 ;
     RECT  4.392 29.069 81.882 30.096 ;
     RECT  4.41 30.096 4.644 30.108 ;
     RECT  4.662 30.096 4.932 30.108 ;
     RECT  4.95 30.096 5.22 30.108 ;
     RECT  5.238 30.096 5.472 30.108 ;
     RECT  5.49 30.096 5.76 30.108 ;
     RECT  5.778 30.096 6.048 30.108 ;
     RECT  6.066 30.096 6.3 30.108 ;
     RECT  6.318 30.096 6.588 30.108 ;
     RECT  6.606 30.096 6.876 30.108 ;
     RECT  6.894 30.096 7.128 30.108 ;
     RECT  7.146 30.096 7.416 30.108 ;
     RECT  7.434 30.096 7.704 30.108 ;
     RECT  7.722 30.096 7.956 30.108 ;
     RECT  7.974 30.096 8.244 30.108 ;
     RECT  8.262 30.096 8.532 30.108 ;
     RECT  8.55 30.096 8.784 30.108 ;
     RECT  8.802 30.096 9.072 30.108 ;
     RECT  9.09 30.096 9.36 30.108 ;
     RECT  9.378 30.096 9.612 30.108 ;
     RECT  9.63 30.096 9.9 30.108 ;
     RECT  9.918 30.096 10.188 30.108 ;
     RECT  10.206 30.096 10.44 30.108 ;
     RECT  10.458 30.096 10.728 30.108 ;
     RECT  10.746 30.096 10.98 30.108 ;
     RECT  10.998 30.096 11.268 30.108 ;
     RECT  11.286 30.096 11.556 30.108 ;
     RECT  11.574 30.096 11.808 30.108 ;
     RECT  11.826 30.096 12.096 30.108 ;
     RECT  12.114 30.096 12.384 30.108 ;
     RECT  12.402 30.096 12.636 30.108 ;
     RECT  12.654 30.096 12.924 30.108 ;
     RECT  12.942 30.096 13.212 30.108 ;
     RECT  13.23 30.096 13.464 30.108 ;
     RECT  13.482 30.096 13.752 30.108 ;
     RECT  13.77 30.096 14.04 30.108 ;
     RECT  14.058 30.096 14.292 30.108 ;
     RECT  14.31 30.096 14.58 30.108 ;
     RECT  14.598 30.096 14.868 30.108 ;
     RECT  14.886 30.096 15.12 30.108 ;
     RECT  15.138 30.096 15.408 30.108 ;
     RECT  15.426 30.096 15.696 30.108 ;
     RECT  15.714 30.096 15.948 30.108 ;
     RECT  15.966 30.096 16.236 30.108 ;
     RECT  16.254 30.096 16.524 30.108 ;
     RECT  16.542 30.096 16.776 30.108 ;
     RECT  16.794 30.096 17.064 30.108 ;
     RECT  17.082 30.096 17.352 30.108 ;
     RECT  17.37 30.096 17.604 30.108 ;
     RECT  17.622 30.096 17.892 30.108 ;
     RECT  17.91 30.096 18.18 30.108 ;
     RECT  18.198 30.096 18.432 30.108 ;
     RECT  18.45 30.096 18.72 30.108 ;
     RECT  18.738 30.096 19.008 30.108 ;
     RECT  19.026 30.096 19.26 30.108 ;
     RECT  19.278 30.096 19.548 30.108 ;
     RECT  19.566 30.096 19.836 30.108 ;
     RECT  19.854 30.096 20.088 30.108 ;
     RECT  20.106 30.096 20.376 30.108 ;
     RECT  20.394 30.096 20.664 30.108 ;
     RECT  20.682 30.096 20.916 30.108 ;
     RECT  20.934 30.096 21.204 30.108 ;
     RECT  21.222 30.096 21.492 30.108 ;
     RECT  21.51 30.096 21.744 30.108 ;
     RECT  21.762 30.096 22.032 30.108 ;
     RECT  22.05 30.096 22.32 30.108 ;
     RECT  22.338 30.096 22.572 30.108 ;
     RECT  22.59 30.096 22.86 30.108 ;
     RECT  22.878 30.096 23.148 30.108 ;
     RECT  23.166 30.096 23.4 30.108 ;
     RECT  23.418 30.096 23.688 30.108 ;
     RECT  23.706 30.096 23.94 30.108 ;
     RECT  23.958 30.096 24.228 30.108 ;
     RECT  24.246 30.096 24.516 30.108 ;
     RECT  24.534 30.096 24.768 30.108 ;
     RECT  24.786 30.096 25.056 30.108 ;
     RECT  25.074 30.096 25.344 30.108 ;
     RECT  25.362 30.096 25.596 30.108 ;
     RECT  25.614 30.096 25.884 30.108 ;
     RECT  25.902 30.096 26.172 30.108 ;
     RECT  26.19 30.096 26.424 30.108 ;
     RECT  26.442 30.096 26.712 30.108 ;
     RECT  26.73 30.096 27 30.108 ;
     RECT  27.018 30.096 27.252 30.108 ;
     RECT  27.27 30.096 27.54 30.108 ;
     RECT  27.558 30.096 27.828 30.108 ;
     RECT  27.846 30.096 28.08 30.108 ;
     RECT  28.098 30.096 28.368 30.108 ;
     RECT  28.386 30.096 28.656 30.108 ;
     RECT  28.674 30.096 28.908 30.108 ;
     RECT  28.926 30.096 29.196 30.108 ;
     RECT  29.214 30.096 29.484 30.108 ;
     RECT  29.502 30.096 29.736 30.108 ;
     RECT  29.754 30.096 30.024 30.108 ;
     RECT  30.042 30.096 30.312 30.108 ;
     RECT  30.33 30.096 30.564 30.108 ;
     RECT  30.582 30.096 30.852 30.108 ;
     RECT  30.87 30.096 31.14 30.108 ;
     RECT  31.158 30.096 31.392 30.108 ;
     RECT  31.41 30.096 31.68 30.108 ;
     RECT  31.698 30.096 31.968 30.108 ;
     RECT  31.986 30.096 32.22 30.108 ;
     RECT  32.238 30.096 32.508 30.108 ;
     RECT  32.526 30.096 32.796 30.108 ;
     RECT  32.814 30.096 33.048 30.108 ;
     RECT  33.066 30.096 33.336 30.108 ;
     RECT  33.354 30.096 33.624 30.108 ;
     RECT  33.642 30.096 33.876 30.108 ;
     RECT  33.894 30.096 34.164 30.108 ;
     RECT  34.182 30.096 34.452 30.108 ;
     RECT  34.47 30.096 34.704 30.108 ;
     RECT  34.722 30.096 34.992 30.108 ;
     RECT  35.01 30.096 35.28 30.108 ;
     RECT  35.298 30.096 35.532 30.108 ;
     RECT  35.55 30.096 35.82 30.108 ;
     RECT  35.838 30.096 36.108 30.108 ;
     RECT  36.126 30.096 36.36 30.108 ;
     RECT  36.378 30.096 36.648 30.108 ;
     RECT  36.666 30.096 36.9 30.108 ;
     RECT  36.918 30.096 37.188 30.108 ;
     RECT  37.206 30.096 37.476 30.108 ;
     RECT  37.494 30.096 37.728 30.108 ;
     RECT  37.746 30.096 38.016 30.108 ;
     RECT  38.034 30.096 38.304 30.108 ;
     RECT  38.322 30.096 38.556 30.108 ;
     RECT  38.574 30.096 38.844 30.108 ;
     RECT  38.862 30.096 39.132 30.108 ;
     RECT  39.15 30.096 39.384 30.108 ;
     RECT  39.402 30.096 39.672 30.108 ;
     RECT  39.69 30.096 39.96 30.108 ;
     RECT  39.978 30.096 40.212 30.108 ;
     RECT  40.23 30.096 40.5 30.108 ;
     RECT  40.518 30.096 40.788 30.108 ;
     RECT  40.806 30.096 41.04 30.108 ;
     RECT  41.058 30.096 41.328 30.108 ;
     RECT  41.346 30.096 41.616 30.108 ;
     RECT  41.634 30.096 41.868 30.108 ;
     RECT  41.886 30.096 42.156 30.108 ;
     RECT  42.174 30.096 42.444 30.108 ;
     RECT  42.462 30.096 42.696 30.108 ;
     RECT  42.714 30.096 42.984 30.108 ;
     RECT  43.002 30.096 43.272 30.108 ;
     RECT  43.29 30.096 43.524 30.108 ;
     RECT  43.542 30.096 43.812 30.108 ;
     RECT  43.83 30.096 44.1 30.108 ;
     RECT  44.118 30.096 44.352 30.108 ;
     RECT  44.37 30.096 44.64 30.108 ;
     RECT  44.658 30.096 44.928 30.108 ;
     RECT  44.946 30.096 45.18 30.108 ;
     RECT  45.198 30.096 45.468 30.108 ;
     RECT  45.486 30.096 45.756 30.108 ;
     RECT  45.774 30.096 46.008 30.108 ;
     RECT  46.026 30.096 46.296 30.108 ;
     RECT  46.314 30.096 46.584 30.108 ;
     RECT  46.602 30.096 46.836 30.108 ;
     RECT  46.854 30.096 47.124 30.108 ;
     RECT  47.142 30.096 47.412 30.108 ;
     RECT  47.43 30.096 47.664 30.108 ;
     RECT  47.682 30.096 47.952 30.108 ;
     RECT  47.97 30.096 48.24 30.108 ;
     RECT  48.258 30.096 48.492 30.108 ;
     RECT  48.51 30.096 48.78 30.108 ;
     RECT  48.798 30.096 49.068 30.108 ;
     RECT  49.086 30.096 49.32 30.108 ;
     RECT  49.338 30.096 49.608 30.108 ;
     RECT  49.626 30.096 49.86 30.108 ;
     RECT  49.878 30.096 50.148 30.108 ;
     RECT  50.166 30.096 50.436 30.108 ;
     RECT  50.454 30.096 50.688 30.108 ;
     RECT  50.706 30.096 50.976 30.108 ;
     RECT  50.994 30.096 51.264 30.108 ;
     RECT  51.282 30.096 51.516 30.108 ;
     RECT  51.534 30.096 51.804 30.108 ;
     RECT  51.822 30.096 52.092 30.108 ;
     RECT  52.11 30.096 52.344 30.108 ;
     RECT  52.362 30.096 52.632 30.108 ;
     RECT  52.65 30.096 52.92 30.108 ;
     RECT  52.938 30.096 53.172 30.108 ;
     RECT  53.19 30.096 53.46 30.108 ;
     RECT  53.478 30.096 53.748 30.108 ;
     RECT  53.766 30.096 54 30.108 ;
     RECT  54.018 30.096 54.288 30.108 ;
     RECT  54.306 30.096 54.576 30.108 ;
     RECT  54.594 30.096 54.828 30.108 ;
     RECT  54.846 30.096 55.116 30.108 ;
     RECT  55.134 30.096 55.404 30.108 ;
     RECT  55.422 30.096 55.656 30.108 ;
     RECT  55.674 30.096 55.944 30.108 ;
     RECT  55.962 30.096 56.232 30.108 ;
     RECT  56.25 30.096 56.484 30.108 ;
     RECT  56.502 30.096 56.772 30.108 ;
     RECT  56.79 30.096 57.06 30.108 ;
     RECT  57.078 30.096 57.312 30.108 ;
     RECT  57.33 30.096 57.6 30.108 ;
     RECT  57.618 30.096 57.888 30.108 ;
     RECT  57.906 30.096 58.14 30.108 ;
     RECT  58.158 30.096 58.428 30.108 ;
     RECT  58.446 30.096 58.716 30.108 ;
     RECT  58.734 30.096 58.968 30.108 ;
     RECT  58.986 30.096 59.256 30.108 ;
     RECT  59.274 30.096 59.544 30.108 ;
     RECT  59.562 30.096 59.796 30.108 ;
     RECT  59.814 30.096 60.084 30.108 ;
     RECT  60.102 30.096 60.372 30.108 ;
     RECT  60.39 30.096 60.624 30.108 ;
     RECT  60.642 30.096 60.912 30.108 ;
     RECT  60.93 30.096 61.2 30.108 ;
     RECT  61.218 30.096 61.452 30.108 ;
     RECT  61.47 30.096 61.74 30.108 ;
     RECT  61.758 30.096 62.028 30.108 ;
     RECT  62.046 30.096 62.28 30.108 ;
     RECT  62.298 30.096 62.568 30.108 ;
     RECT  62.586 30.096 62.82 30.108 ;
     RECT  62.838 30.096 63.108 30.108 ;
     RECT  63.126 30.096 63.396 30.108 ;
     RECT  63.414 30.096 63.648 30.108 ;
     RECT  63.666 30.096 63.936 30.108 ;
     RECT  63.954 30.096 64.224 30.108 ;
     RECT  64.242 30.096 64.476 30.108 ;
     RECT  64.494 30.096 64.764 30.108 ;
     RECT  64.782 30.096 65.052 30.108 ;
     RECT  65.07 30.096 65.304 30.108 ;
     RECT  65.322 30.096 65.592 30.108 ;
     RECT  65.61 30.096 65.88 30.108 ;
     RECT  65.898 30.096 66.132 30.108 ;
     RECT  66.15 30.096 66.42 30.108 ;
     RECT  66.438 30.096 66.708 30.108 ;
     RECT  66.726 30.096 66.96 30.108 ;
     RECT  66.978 30.096 67.248 30.108 ;
     RECT  67.266 30.096 67.536 30.108 ;
     RECT  67.554 30.096 67.788 30.108 ;
     RECT  67.806 30.096 68.076 30.108 ;
     RECT  68.094 30.096 68.364 30.108 ;
     RECT  68.382 30.096 68.616 30.108 ;
     RECT  68.634 30.096 68.904 30.108 ;
     RECT  68.922 30.096 69.192 30.108 ;
     RECT  69.21 30.096 69.444 30.108 ;
     RECT  69.462 30.096 69.732 30.108 ;
     RECT  69.75 30.096 70.02 30.108 ;
     RECT  70.038 30.096 70.272 30.108 ;
     RECT  70.29 30.096 70.56 30.108 ;
     RECT  70.578 30.096 70.848 30.108 ;
     RECT  70.866 30.096 71.1 30.108 ;
     RECT  71.118 30.096 71.388 30.108 ;
     RECT  71.406 30.096 71.676 30.108 ;
     RECT  71.694 30.096 71.928 30.108 ;
     RECT  71.946 30.096 72.216 30.108 ;
     RECT  72.234 30.096 72.504 30.108 ;
     RECT  72.522 30.096 72.756 30.108 ;
     RECT  72.774 30.096 73.044 30.108 ;
     RECT  73.062 30.096 73.332 30.108 ;
     RECT  73.35 30.096 73.584 30.108 ;
     RECT  73.602 30.096 73.872 30.108 ;
     RECT  73.89 30.096 74.16 30.108 ;
     RECT  74.178 30.096 74.412 30.108 ;
     RECT  74.43 30.096 74.7 30.108 ;
     RECT  74.718 30.096 74.988 30.108 ;
     RECT  75.006 30.096 75.24 30.108 ;
     RECT  75.258 30.096 75.528 30.108 ;
     RECT  75.546 30.096 75.78 30.108 ;
     RECT  75.798 30.096 76.068 30.108 ;
     RECT  76.086 30.096 76.356 30.108 ;
     RECT  76.374 30.096 76.608 30.108 ;
     RECT  76.626 30.096 76.896 30.108 ;
     RECT  76.914 30.096 77.184 30.108 ;
     RECT  77.202 30.096 77.436 30.108 ;
     RECT  77.454 30.096 77.724 30.108 ;
     RECT  77.742 30.096 78.012 30.108 ;
     RECT  78.03 30.096 78.264 30.108 ;
     RECT  78.282 30.096 78.552 30.108 ;
     RECT  78.57 30.096 78.84 30.108 ;
     RECT  78.858 30.096 79.092 30.108 ;
     RECT  79.11 30.096 79.38 30.108 ;
     RECT  79.398 30.096 79.668 30.108 ;
     RECT  79.686 30.096 79.92 30.108 ;
     RECT  79.938 30.096 80.208 30.108 ;
     RECT  80.226 30.096 80.496 30.108 ;
     RECT  80.514 30.096 80.748 30.108 ;
     RECT  80.766 30.096 81.036 30.108 ;
     RECT  81.054 30.096 81.324 30.108 ;
     RECT  81.342 30.096 81.576 30.108 ;
     RECT  81.594 30.096 81.864 30.108 ;
    LAYER M4 ;
     RECT  2.293 28.464 2.387 28.488 ;
     RECT  2.341 1.728 2.408 1.752 ;
     RECT  0.229 21.216 2.408 21.24 ;
     RECT  2.408 1.728 2.704 28.2 ;
     RECT  2.704 25.728 2.819 25.752 ;
     RECT  2.704 27.936 2.819 28.2 ;
     RECT  2.704 1.728 2.837 1.752 ;
     RECT  2.819 27.936 3.539 27.96 ;
     RECT  3.697 25.68 3.733 25.704 ;
     RECT  3.733 25.056 3.985 25.704 ;
     RECT  3.985 25.056 4.201 25.992 ;
     RECT  4.057 27.168 4.201 27.72 ;
     RECT  4.201 25.056 4.453 27.72 ;
     RECT  4.273 29.04 4.705 29.064 ;
     RECT  4.705 28.992 4.741 29.064 ;
     RECT  4.741 28.992 4.789 29.112 ;
     RECT  4.489 1.728 5.036 1.752 ;
     RECT  4.789 28.992 5.105 29.688 ;
     RECT  5.036 1.728 5.108 2.04 ;
     RECT  2.704 4.128 5.108 4.152 ;
     RECT  2.704 21.216 5.108 21.24 ;
     RECT  4.813 23.088 5.108 23.112 ;
     RECT  4.453 24.672 5.108 27.72 ;
     RECT  5.105 28.992 5.108 29.112 ;
     RECT  5.108 1.728 5.404 29.112 ;
     RECT  5.404 23.088 5.645 29.112 ;
     RECT  5.645 28.464 5.651 29.112 ;
     RECT  5.651 28.464 5.753 28.584 ;
     RECT  5.404 1.728 5.939 2.328 ;
     RECT  5.645 23.088 6.227 27.384 ;
     RECT  5.753 28.512 6.227 28.584 ;
     RECT  6.227 23.088 6.541 23.112 ;
     RECT  6.421 29.664 6.581 29.688 ;
     RECT  5.404 21.216 6.709 21.24 ;
     RECT  6.541 22.224 6.709 23.112 ;
     RECT  5.404 4.128 6.755 4.152 ;
     RECT  6.227 24.528 6.755 27.384 ;
     RECT  5.939 1.728 6.965 1.8 ;
     RECT  6.965 1.152 7.049 1.8 ;
     RECT  7.049 1.728 7.244 1.8 ;
     RECT  6.227 28.512 7.285 28.536 ;
     RECT  6.755 24.528 7.441 27.336 ;
     RECT  7.285 28.512 7.505 29.064 ;
     RECT  6.709 21.216 7.693 23.112 ;
     RECT  7.244 1.728 7.808 2.28 ;
     RECT  7.477 15.264 7.808 15.288 ;
     RECT  7.693 21.216 7.808 23.16 ;
     RECT  7.441 24.192 7.808 27.336 ;
     RECT  7.505 28.464 7.808 29.064 ;
     RECT  7.808 1.728 7.912 29.064 ;
     RECT  7.912 1.728 8.104 27.96 ;
     RECT  8.101 0.528 8.201 0.552 ;
     RECT  8.104 22.224 8.489 27.96 ;
     RECT  7.912 29.04 8.705 29.064 ;
     RECT  8.489 22.464 9.011 27.96 ;
     RECT  8.104 15.264 9.413 15.288 ;
     RECT  9.011 23.52 9.425 27.96 ;
     RECT  9.425 27.84 9.445 27.96 ;
     RECT  9.413 14.784 9.497 15.288 ;
     RECT  8.104 21.216 9.853 21.24 ;
     RECT  9.011 22.464 9.853 22.488 ;
     RECT  8.104 1.728 10.021 2.904 ;
     RECT  10.021 1.728 10.109 3.096 ;
     RECT  9.853 21.216 10.172 22.488 ;
     RECT  9.425 23.52 10.172 26.856 ;
     RECT  10.109 2.148 10.357 3.096 ;
     RECT  10.357 2.148 10.508 3.144 ;
     RECT  9.497 15.264 10.508 15.288 ;
     RECT  10.172 21.216 10.508 26.856 ;
     RECT  9.445 27.84 10.508 28.536 ;
     RECT  10.357 0.288 10.595 0.312 ;
     RECT  10.508 2.148 10.612 28.536 ;
     RECT  10.612 2.418 10.804 28.536 ;
     RECT  10.804 15.168 10.829 15.288 ;
     RECT  10.804 28.464 10.837 28.536 ;
     RECT  10.837 0.192 10.979 0.216 ;
     RECT  10.804 24.192 11.009 27.288 ;
     RECT  11.009 27.264 11.117 27.288 ;
     RECT  10.804 21.216 11.153 22.776 ;
     RECT  10.837 28.464 11.297 28.968 ;
     RECT  11.297 28.464 11.657 28.536 ;
     RECT  10.804 2.418 11.699 3.096 ;
     RECT  11.699 2.418 11.761 2.76 ;
     RECT  11.009 24.192 12.013 25.896 ;
     RECT  11.657 28.464 12.025 28.488 ;
     RECT  11.153 21.216 12.625 21.24 ;
     RECT  12.013 24.192 12.661 26.184 ;
     RECT  11.761 2.256 12.757 2.76 ;
     RECT  12.229 27.936 12.769 28.296 ;
     RECT  11.153 22.464 12.805 22.776 ;
     RECT  12.661 23.904 12.805 26.232 ;
     RECT  12.805 22.464 13.004 26.232 ;
     RECT  12.769 27.36 13.004 28.296 ;
     RECT  12.757 1.728 13.021 2.76 ;
     RECT  13.021 1.728 13.208 2.904 ;
     RECT  10.829 15.168 13.208 15.192 ;
     RECT  12.625 21.12 13.208 21.24 ;
     RECT  13.004 22.464 13.208 28.296 ;
     RECT  13.208 1.728 13.333 28.296 ;
     RECT  13.333 1.728 13.504 28.488 ;
     RECT  13.504 21.216 13.673 28.488 ;
     RECT  12.517 29.664 13.961 29.688 ;
     RECT  13.673 21.216 14.033 28.008 ;
     RECT  14.033 21.216 14.393 26.856 ;
     RECT  13.504 15.168 14.821 15.192 ;
     RECT  13.504 1.728 14.825 3.096 ;
     RECT  14.033 27.936 14.857 28.008 ;
     RECT  14.821 15.168 14.861 15.288 ;
     RECT  14.825 2.256 15.253 3.096 ;
     RECT  15.733 0.192 15.875 0.216 ;
     RECT  15.253 2.256 15.908 3.336 ;
     RECT  14.861 15.264 15.908 15.288 ;
     RECT  14.393 21.216 15.908 26.76 ;
     RECT  14.857 27.936 15.908 28.488 ;
     RECT  15.908 2.148 16.069 28.488 ;
     RECT  16.069 1.728 16.204 28.488 ;
     RECT  16.204 1.728 16.481 3.048 ;
     RECT  16.204 27.936 16.645 28.488 ;
     RECT  16.645 27.936 16.949 28.536 ;
     RECT  16.204 21.216 17.449 26.904 ;
     RECT  16.949 27.936 17.449 28.488 ;
     RECT  16.481 1.728 17.461 2.952 ;
     RECT  17.449 21.216 18.277 28.488 ;
     RECT  18.277 21.216 18.467 29.064 ;
     RECT  17.461 1.728 18.608 3 ;
     RECT  16.204 15.264 18.608 15.288 ;
     RECT  18.467 21.216 18.608 28.488 ;
     RECT  18.608 1.728 18.904 28.488 ;
     RECT  18.904 1.728 19.325 3.432 ;
     RECT  18.904 21.216 19.397 28.488 ;
     RECT  19.381 29.664 19.669 29.688 ;
     RECT  19.325 1.728 19.721 2.856 ;
     RECT  19.721 2.784 19.801 2.856 ;
     RECT  19.397 21.216 19.937 27.96 ;
     RECT  19.669 29.664 19.937 29.736 ;
     RECT  19.937 21.216 19.957 26.856 ;
     RECT  19.957 29.088 20.044 29.112 ;
     RECT  19.721 1.728 20.837 1.8 ;
     RECT  19.801 2.832 21.061 2.856 ;
     RECT  21.061 2.832 21.157 2.904 ;
     RECT  19.957 21.12 21.157 26.856 ;
     RECT  19.937 27.936 21.157 27.96 ;
     RECT  21.157 2.016 21.308 2.904 ;
     RECT  21.013 3.936 21.308 3.96 ;
     RECT  18.904 15.168 21.308 15.192 ;
     RECT  21.157 21.12 21.308 27.96 ;
     RECT  21.121 29.088 21.347 29.112 ;
     RECT  21.308 2.016 21.581 28.092 ;
     RECT  21.581 2.016 21.604 28.536 ;
     RECT  21.604 2.016 21.701 2.856 ;
     RECT  21.604 21.216 22.259 22.824 ;
     RECT  21.701 2.736 22.717 2.856 ;
     RECT  21.604 15.168 22.813 15.192 ;
     RECT  22.813 15.168 22.853 15.288 ;
     RECT  21.604 24.096 22.885 25.128 ;
     RECT  21.604 26.208 22.981 28.536 ;
     RECT  21.869 1.728 23.065 1.752 ;
     RECT  22.981 26.208 23.141 29.112 ;
     RECT  22.885 24.096 23.228 25.176 ;
     RECT  23.141 26.208 23.357 28.488 ;
     RECT  23.065 1.728 23.609 2.28 ;
     RECT  23.609 2.148 23.701 2.28 ;
     RECT  23.509 29.664 23.717 29.688 ;
     RECT  23.228 23.808 23.749 25.176 ;
     RECT  23.701 2.148 23.797 2.856 ;
     RECT  22.259 21.216 23.797 22.776 ;
     RECT  23.749 23.808 23.797 25.224 ;
     RECT  23.797 21.216 23.845 25.224 ;
     RECT  23.357 26.208 23.845 28.248 ;
     RECT  23.797 2.148 24.008 2.904 ;
     RECT  22.853 15.264 24.008 15.288 ;
     RECT  23.845 21.216 24.008 28.248 ;
     RECT  24.008 2.148 24.304 28.248 ;
     RECT  24.085 0.288 24.373 0.312 ;
     RECT  24.304 26.736 24.373 28.248 ;
     RECT  24.373 0.192 24.419 0.312 ;
     RECT  24.419 0.192 24.515 0.216 ;
     RECT  24.304 2.148 24.515 3.096 ;
     RECT  24.515 2.148 24.605 2.856 ;
     RECT  24.373 26.736 24.725 28.344 ;
     RECT  24.725 27.936 24.893 28.344 ;
     RECT  24.893 27.936 24.977 28.488 ;
     RECT  25.148 29.664 25.235 29.688 ;
     RECT  24.304 21.216 25.477 23.352 ;
     RECT  25.477 21.12 25.619 23.352 ;
     RECT  24.304 24.48 25.669 25.704 ;
     RECT  24.725 26.736 25.669 26.904 ;
     RECT  25.669 24.48 25.717 26.904 ;
     RECT  24.977 27.936 25.717 27.96 ;
     RECT  25.619 21.216 26.125 23.352 ;
     RECT  25.717 24.48 26.125 27.96 ;
     RECT  26.005 29.088 26.129 29.112 ;
     RECT  26.293 29.664 26.417 29.688 ;
     RECT  24.605 1.728 26.708 2.856 ;
     RECT  24.304 15.264 26.708 15.288 ;
     RECT  26.125 21.216 26.708 27.96 ;
     RECT  26.708 1.728 26.821 28.092 ;
     RECT  26.821 1.728 27.004 28.248 ;
     RECT  27.004 28.224 27.109 28.248 ;
     RECT  27.109 28.224 27.155 28.344 ;
     RECT  27.004 23.856 27.317 27.24 ;
     RECT  27.155 28.32 27.397 28.344 ;
     RECT  27.397 28.32 27.821 28.488 ;
     RECT  27.821 28.32 27.893 28.44 ;
     RECT  27.781 29.664 27.971 29.688 ;
     RECT  27.004 1.728 28.109 3.24 ;
     RECT  27.317 23.904 28.213 27.24 ;
     RECT  28.109 2.256 28.357 3.24 ;
     RECT  28.357 2.256 28.441 3.432 ;
     RECT  28.213 23.904 28.681 27.912 ;
     RECT  27.004 21.216 28.837 22.776 ;
     RECT  28.681 23.856 28.837 27.912 ;
     RECT  28.837 21.216 29.221 27.912 ;
     RECT  29.221 21.216 29.269 28.2 ;
     RECT  29.221 0.192 29.363 0.216 ;
     RECT  28.441 2.256 29.408 3.096 ;
     RECT  27.004 15.264 29.408 15.288 ;
     RECT  29.269 21.216 29.408 28.296 ;
     RECT  29.408 2.148 29.605 28.296 ;
     RECT  29.605 2.016 29.651 28.296 ;
     RECT  29.651 2.016 29.704 27.96 ;
     RECT  29.704 2.016 29.801 2.904 ;
     RECT  29.801 2.016 29.861 2.856 ;
     RECT  29.861 1.728 29.909 2.856 ;
     RECT  29.704 27.936 30.179 27.96 ;
     RECT  29.704 21.12 30.371 26.808 ;
     RECT  30.371 21.216 30.385 26.808 ;
     RECT  30.385 21.216 30.413 26.76 ;
     RECT  29.704 15.168 30.769 15.192 ;
     RECT  30.413 24.624 30.773 26.76 ;
     RECT  30.769 15.168 30.809 15.288 ;
     RECT  29.909 1.728 30.877 1.752 ;
     RECT  29.909 2.832 30.877 2.856 ;
     RECT  30.709 27.84 31.165 27.864 ;
     RECT  29.893 29.664 31.187 29.688 ;
     RECT  31.165 27.84 31.283 28.536 ;
     RECT  30.877 1.728 31.313 2.856 ;
     RECT  30.413 21.216 31.633 23.256 ;
     RECT  30.773 24.624 31.633 26.664 ;
     RECT  31.633 21.216 31.777 26.664 ;
     RECT  31.313 2.016 31.957 2.856 ;
     RECT  31.957 2.016 32.108 2.904 ;
     RECT  30.809 15.264 32.108 15.288 ;
     RECT  31.777 21.216 32.108 26.808 ;
     RECT  31.283 27.84 32.108 28.248 ;
     RECT  31.957 0.192 32.147 0.216 ;
     RECT  32.108 2.016 32.404 28.248 ;
     RECT  32.404 21.216 32.429 28.248 ;
     RECT  32.429 23.856 32.465 28.248 ;
     RECT  32.404 2.016 32.629 2.904 ;
     RECT  32.465 24.96 32.629 28.248 ;
     RECT  32.629 24.96 32.861 28.536 ;
     RECT  32.465 23.856 33.12 23.976 ;
     RECT  32.861 24.96 33.299 28.488 ;
     RECT  32.629 1.728 33.301 2.904 ;
     RECT  33.301 1.728 33.509 1.8 ;
     RECT  33.12 23.904 33.509 23.976 ;
     RECT  33.299 25.056 33.581 28.488 ;
     RECT  33.581 25.056 33.617 27.96 ;
     RECT  32.429 21.216 33.689 22.776 ;
     RECT  33.301 2.832 33.973 2.904 ;
     RECT  33.689 22.224 34.189 22.776 ;
     RECT  33.509 23.904 34.189 23.928 ;
     RECT  34.261 29.664 34.348 29.688 ;
     RECT  33.509 1.728 34.516 1.752 ;
     RECT  34.516 1.728 34.549 1.8 ;
     RECT  33.973 2.832 34.549 3.432 ;
     RECT  34.189 22.224 34.549 23.928 ;
     RECT  34.549 22.224 34.657 23.976 ;
     RECT  33.617 25.104 34.657 27.96 ;
     RECT  34.549 1.728 34.808 3.432 ;
     RECT  32.404 15.264 34.808 15.288 ;
     RECT  33.689 21.216 34.808 21.24 ;
     RECT  34.657 22.224 34.808 27.96 ;
     RECT  34.808 1.728 34.837 28.092 ;
     RECT  34.837 1.728 35.104 29.064 ;
     RECT  34.837 0.288 35.125 0.312 ;
     RECT  35.125 0.192 35.219 0.312 ;
     RECT  35.104 1.728 35.219 3.24 ;
     RECT  35.219 0.192 35.267 0.216 ;
     RECT  35.104 21.12 35.267 29.064 ;
     RECT  35.219 1.728 35.741 3 ;
     RECT  35.267 21.12 35.747 25.176 ;
     RECT  35.267 26.208 35.849 29.064 ;
     RECT  35.104 12 36.281 13.656 ;
     RECT  35.747 21.216 36.281 25.176 ;
     RECT  35.849 27.888 36.469 29.064 ;
     RECT  35.849 26.208 36.505 26.856 ;
     RECT  36.281 12 36.533 13.512 ;
     RECT  36.469 27.888 36.893 29.112 ;
     RECT  35.741 1.728 36.997 2.904 ;
     RECT  36.281 21.216 37.177 22.584 ;
     RECT  37.285 29.664 37.379 29.688 ;
     RECT  36.997 1.728 37.381 3.432 ;
     RECT  37.381 1.728 37.433 3.96 ;
     RECT  37.433 2.064 37.508 3.96 ;
     RECT  36.533 12 37.508 12.936 ;
     RECT  35.104 15.264 37.508 15.288 ;
     RECT  37.177 21.12 37.508 22.584 ;
     RECT  36.281 23.568 37.508 25.176 ;
     RECT  36.505 26.544 37.508 26.856 ;
     RECT  36.893 27.888 37.508 28.248 ;
     RECT  36.757 0.288 37.619 0.312 ;
     RECT  37.508 2.064 37.619 28.248 ;
     RECT  37.619 2.064 37.804 28.2 ;
     RECT  37.804 22.56 38.003 28.2 ;
     RECT  38.003 22.56 38.195 28.056 ;
     RECT  38.195 22.56 38.405 27.24 ;
     RECT  38.405 22.56 38.657 26.904 ;
     RECT  37.804 15.168 38.801 15.288 ;
     RECT  37.804 2.064 38.965 2.904 ;
     RECT  38.965 29.088 39.053 29.112 ;
     RECT  37.804 21.216 39.205 21.528 ;
     RECT  38.657 22.56 39.205 24.504 ;
     RECT  38.965 1.728 39.541 2.904 ;
     RECT  38.657 25.68 39.553 26.904 ;
     RECT  39.253 27.936 39.553 27.96 ;
     RECT  39.541 1.728 39.781 2.952 ;
     RECT  39.205 21.216 39.973 24.504 ;
     RECT  39.553 25.68 39.973 27.96 ;
     RECT  39.781 1.728 40.205 3.048 ;
     RECT  40.205 2.148 40.208 3.048 ;
     RECT  38.801 15.264 40.208 15.288 ;
     RECT  39.973 18.816 40.208 18.84 ;
     RECT  39.973 21.216 40.208 27.96 ;
     RECT  40.208 2.148 40.312 28.092 ;
     RECT  40.312 2.208 40.316 28.092 ;
     RECT  40.021 0.288 40.403 0.312 ;
     RECT  40.316 2.208 40.403 28.2 ;
     RECT  40.403 2.208 40.504 27.96 ;
     RECT  40.504 21.216 40.739 25.656 ;
     RECT  40.504 2.208 40.745 3.432 ;
     RECT  40.645 29.088 40.817 29.112 ;
     RECT  40.745 2.256 40.853 3.432 ;
     RECT  40.739 21.216 40.883 25.32 ;
     RECT  40.883 23.856 41.069 25.32 ;
     RECT  40.853 2.832 41.213 3.432 ;
     RECT  40.504 26.736 41.393 27.96 ;
     RECT  40.883 21.216 41.497 22.824 ;
     RECT  41.393 26.736 41.501 27.432 ;
     RECT  41.497 21.12 41.581 22.824 ;
     RECT  41.069 23.904 41.717 25.176 ;
     RECT  41.717 24.096 41.861 25.176 ;
     RECT  41.501 26.736 41.929 27.336 ;
     RECT  41.509 12.384 41.941 12.408 ;
     RECT  41.941 12.384 41.965 12.552 ;
     RECT  41.749 29.664 41.969 29.688 ;
     RECT  41.965 12 42.085 12.552 ;
     RECT  41.581 21.216 42.085 22.824 ;
     RECT  40.504 15.264 42.133 15.288 ;
     RECT  41.989 1.728 42.149 1.752 ;
     RECT  42.133 15.072 42.289 15.288 ;
     RECT  41.861 24.144 42.325 25.176 ;
     RECT  41.929 26.208 42.325 27.336 ;
     RECT  42.277 1.824 42.421 1.848 ;
     RECT  41.213 2.832 42.421 3 ;
     RECT  42.421 1.824 42.565 3 ;
     RECT  42.085 12 42.757 13.032 ;
     RECT  42.325 24.144 42.829 27.336 ;
     RECT  41.461 28.464 42.853 28.488 ;
     RECT  42.757 0.192 42.899 0.216 ;
     RECT  42.565 1.824 42.908 3.336 ;
     RECT  42.757 12 42.908 13.08 ;
     RECT  42.289 14.256 42.908 15.288 ;
     RECT  42.085 21.216 42.908 22.872 ;
     RECT  42.829 23.952 42.908 27.336 ;
     RECT  42.853 28.464 42.908 29.064 ;
     RECT  42.908 1.824 43.204 29.064 ;
     RECT  43.204 23.76 43.265 29.064 ;
     RECT  43.204 1.824 43.381 2.904 ;
     RECT  43.381 1.728 43.481 2.904 ;
     RECT  43.204 14.256 43.985 15.384 ;
     RECT  43.204 21.36 44.189 22.776 ;
     RECT  43.265 23.76 44.189 28.488 ;
     RECT  43.204 12 44.197 13.08 ;
     RECT  43.985 14.256 44.197 15.288 ;
     RECT  44.197 12 44.201 15.288 ;
     RECT  44.189 21.36 44.269 28.488 ;
     RECT  44.201 12 44.341 14.04 ;
     RECT  44.269 21.312 44.341 28.488 ;
     RECT  43.481 1.728 44.485 2.856 ;
     RECT  44.341 11.952 44.629 14.04 ;
     RECT  44.485 1.728 44.773 2.904 ;
     RECT  44.773 1.728 44.837 2.952 ;
     RECT  44.341 21.12 45.061 28.488 ;
     RECT  44.629 11.424 45.397 14.04 ;
     RECT  44.201 15.264 45.397 15.288 ;
     RECT  45.301 0.192 45.491 0.216 ;
     RECT  45.061 21.12 45.589 28.536 ;
     RECT  44.837 1.728 45.608 3.432 ;
     RECT  45.397 11.424 45.608 15.288 ;
     RECT  45.589 21.12 45.608 29.064 ;
     RECT  45.608 1.728 45.712 29.064 ;
     RECT  45.712 29.04 45.877 29.064 ;
     RECT  45.712 1.728 45.904 27.822 ;
     RECT  45.877 29.04 46.067 29.112 ;
     RECT  46.067 29.088 46.165 29.112 ;
     RECT  45.904 21.12 46.636 27.384 ;
     RECT  45.904 12 46.643 15.384 ;
     RECT  46.165 29.088 46.721 29.688 ;
     RECT  45.904 1.728 46.739 3.432 ;
     RECT  46.636 21.12 46.931 21.144 ;
     RECT  46.636 22.176 47.149 27.384 ;
     RECT  46.721 29.088 47.153 29.112 ;
     RECT  47.141 3.936 47.225 3.96 ;
     RECT  47.149 22.176 47.761 27.96 ;
     RECT  46.739 1.728 47.797 2.856 ;
     RECT  47.797 1.728 47.837 2.904 ;
     RECT  47.761 22.032 47.941 27.96 ;
     RECT  46.643 12.528 48.037 15.384 ;
     RECT  47.941 21.648 48.085 27.96 ;
     RECT  48.085 21.648 48.181 28.008 ;
     RECT  47.837 2.016 48.308 2.904 ;
     RECT  48.037 12 48.308 15.384 ;
     RECT  48.181 21.648 48.308 28.248 ;
     RECT  48.308 2.016 48.412 28.248 ;
     RECT  48.412 2.016 48.604 28.008 ;
     RECT  48.613 0.192 48.755 0.216 ;
     RECT  48.613 29.04 48.755 29.064 ;
     RECT  48.604 12 48.803 13.656 ;
     RECT  48.803 12.528 48.853 13.656 ;
     RECT  48.604 2.016 48.917 2.952 ;
     RECT  48.604 21.648 48.947 22.248 ;
     RECT  48.604 25.056 48.953 26.856 ;
     RECT  48.604 27.888 48.953 28.008 ;
     RECT  48.853 12.528 48.961 12.552 ;
     RECT  48.604 23.28 48.989 24.024 ;
     RECT  48.917 2.016 49.061 2.904 ;
     RECT  48.947 22.224 49.385 22.248 ;
     RECT  48.953 27.936 49.516 28.008 ;
     RECT  48.604 14.832 49.609 15.384 ;
     RECT  48.989 23.328 49.661 24.024 ;
     RECT  48.953 25.056 49.661 25.224 ;
     RECT  48.853 13.632 49.849 13.656 ;
     RECT  48.953 26.208 49.921 26.856 ;
     RECT  49.516 27.936 49.921 27.96 ;
     RECT  49.849 13.632 49.957 13.704 ;
     RECT  49.609 14.832 49.957 15.288 ;
     RECT  49.661 23.328 49.957 25.224 ;
     RECT  49.921 26.208 49.957 27.96 ;
     RECT  49.061 2.832 49.985 2.904 ;
     RECT  49.957 23.328 49.993 27.96 ;
     RECT  49.957 13.104 50.065 13.704 ;
     RECT  49.957 14.736 50.065 15.288 ;
     RECT  49.717 29.04 50.293 29.064 ;
     RECT  49.189 1.728 50.533 1.752 ;
     RECT  50.533 1.728 50.629 1.8 ;
     RECT  49.985 2.832 50.629 2.952 ;
     RECT  50.293 29.04 50.645 29.112 ;
     RECT  50.029 22.032 50.677 22.056 ;
     RECT  49.993 23.136 50.677 27.96 ;
     RECT  50.065 13.104 50.725 15.288 ;
     RECT  50.725 13.104 50.773 15.336 ;
     RECT  50.677 22.032 50.821 27.96 ;
     RECT  50.773 13.056 50.869 15.336 ;
     RECT  50.821 22.032 51.005 28.488 ;
     RECT  50.629 1.728 51.008 2.952 ;
     RECT  50.869 12.528 51.008 15.336 ;
     RECT  51.005 22.032 51.008 28.248 ;
     RECT  51.008 1.728 51.304 28.248 ;
     RECT  51.304 13.056 51.329 13.08 ;
     RECT  51.304 26.208 51.437 28.248 ;
     RECT  51.304 14.256 51.539 15.336 ;
     RECT  51.539 14.736 51.545 15.336 ;
     RECT  51.304 2.88 51.553 3.432 ;
     RECT  51.545 14.832 51.661 15.336 ;
     RECT  51.661 15.264 51.761 15.336 ;
     RECT  51.553 2.88 51.905 3.24 ;
     RECT  51.469 29.664 51.971 29.688 ;
     RECT  51.437 27.936 52.213 28.248 ;
     RECT  51.304 22.032 52.301 22.056 ;
     RECT  52.213 27.936 52.337 29.064 ;
     RECT  51.304 1.728 52.357 1.752 ;
     RECT  51.905 2.88 52.357 2.904 ;
     RECT  52.337 27.936 52.661 28.968 ;
     RECT  51.437 26.208 52.765 26.952 ;
     RECT  52.661 27.936 52.765 28.536 ;
     RECT  51.304 23.088 52.94 25.224 ;
     RECT  52.94 22.752 53.017 25.224 ;
     RECT  52.765 26.208 53.017 28.536 ;
     RECT  52.357 1.728 53.029 2.904 ;
     RECT  53.029 1.728 53.708 3.336 ;
     RECT  51.761 15.264 53.708 15.288 ;
     RECT  53.017 22.752 53.708 28.536 ;
     RECT  53.708 1.728 54.004 28.536 ;
     RECT  54.004 23.328 54.101 28.536 ;
     RECT  54.004 1.728 54.469 2.856 ;
     RECT  54.004 21.12 54.563 21.816 ;
     RECT  54.133 29.664 54.641 29.688 ;
     RECT  54.004 14.832 54.893 15.288 ;
     RECT  54.469 1.728 54.965 1.896 ;
     RECT  54.101 23.328 55.1 27.96 ;
     RECT  54.563 21.648 55.289 21.816 ;
     RECT  55.289 21.792 55.357 21.816 ;
     RECT  55.1 22.8 55.357 27.96 ;
     RECT  54.965 1.776 55.484 1.896 ;
     RECT  55.213 3.072 55.484 3.096 ;
     RECT  55.357 21.792 55.525 27.96 ;
     RECT  55.525 21.792 55.897 28.008 ;
     RECT  54.709 29.04 55.897 29.064 ;
     RECT  55.484 1.776 56.053 3.096 ;
     RECT  56.053 1.728 56.189 3.096 ;
     RECT  56.189 2.148 56.245 3.096 ;
     RECT  55.897 21.792 56.405 29.064 ;
     RECT  56.245 2.148 56.408 3.336 ;
     RECT  54.893 15.264 56.408 15.288 ;
     RECT  56.405 21.792 56.408 28.2 ;
     RECT  56.408 2.148 56.704 28.2 ;
     RECT  56.245 0.192 56.819 0.216 ;
     RECT  56.704 21.312 57.017 28.2 ;
     RECT  57.017 21.312 57.155 27.96 ;
     RECT  56.704 2.148 57.157 3.096 ;
     RECT  57.157 1.728 57.529 3.096 ;
     RECT  57.155 21.696 57.701 27.96 ;
     RECT  57.529 1.728 58.517 2.28 ;
     RECT  57.701 21.696 58.549 26.856 ;
     RECT  57.701 27.936 58.549 27.96 ;
     RECT  58.549 27.936 58.669 28.536 ;
     RECT  58.549 21.552 58.885 26.856 ;
     RECT  58.669 27.84 58.885 28.536 ;
     RECT  58.517 1.728 59.108 2.904 ;
     RECT  56.704 15.264 59.108 15.288 ;
     RECT  58.885 21.552 59.108 28.536 ;
     RECT  59.108 1.728 59.404 28.536 ;
     RECT  59.404 27.936 59.795 28.536 ;
     RECT  59.404 21.648 59.861 26.856 ;
     RECT  59.941 29.664 60.113 29.688 ;
     RECT  59.404 1.728 60.179 3.432 ;
     RECT  59.861 21.648 60.221 26.76 ;
     RECT  60.179 1.728 60.329 2.952 ;
     RECT  60.329 2.16 60.515 2.952 ;
     RECT  59.795 28.512 60.653 28.536 ;
     RECT  60.515 2.256 60.803 2.952 ;
     RECT  60.757 29.04 61.091 29.112 ;
     RECT  60.221 21.648 61.189 26.28 ;
     RECT  61.189 21.648 61.237 26.328 ;
     RECT  61.091 29.04 61.373 29.064 ;
     RECT  60.803 2.832 61.669 2.952 ;
     RECT  61.669 2.832 61.808 3.048 ;
     RECT  59.404 15.264 61.808 15.288 ;
     RECT  61.237 21.648 61.808 26.808 ;
     RECT  60.757 27.936 61.808 27.96 ;
     RECT  61.808 2.148 62.104 28.488 ;
     RECT  62.104 22.608 62.273 28.488 ;
     RECT  62.273 28.464 62.389 28.488 ;
     RECT  62.104 2.928 62.435 2.952 ;
     RECT  62.273 22.608 62.569 27.048 ;
     RECT  62.149 29.664 62.677 29.688 ;
     RECT  62.104 15.168 62.741 15.288 ;
     RECT  62.389 28.464 62.773 28.536 ;
     RECT  62.677 29.664 62.773 30.024 ;
     RECT  61.669 0.192 62.819 0.216 ;
     RECT  62.773 28.464 62.819 30.024 ;
     RECT  62.117 1.728 63.029 1.8 ;
     RECT  62.819 28.464 63.052 29.688 ;
     RECT  63.052 28.464 63.101 29.112 ;
     RECT  62.569 22.608 63.253 25.08 ;
     RECT  62.569 26.208 63.253 27.048 ;
     RECT  63.169 3.072 63.299 3.096 ;
     RECT  63.253 21.552 63.317 25.08 ;
     RECT  63.253 26.208 63.317 27.336 ;
     RECT  63.317 21.552 63.353 24.024 ;
     RECT  63.101 28.464 63.461 29.064 ;
     RECT  63.317 27.312 63.493 27.336 ;
     RECT  63.029 1.776 63.673 1.8 ;
     RECT  63.493 2.88 63.673 2.904 ;
     RECT  63.317 26.208 64.033 26.232 ;
     RECT  63.673 1.776 64.061 2.904 ;
     RECT  63.461 29.04 64.115 29.064 ;
     RECT  63.889 25.104 64.213 25.128 ;
     RECT  64.033 26.112 64.213 26.232 ;
     RECT  64.061 1.728 64.357 2.904 ;
     RECT  64.213 25.104 64.429 26.232 ;
     RECT  63.493 27.312 64.429 28.056 ;
     RECT  64.357 1.728 64.508 3.048 ;
     RECT  62.741 15.264 64.508 15.288 ;
     RECT  63.353 21.792 64.508 24.024 ;
     RECT  64.429 25.104 64.508 28.056 ;
     RECT  64.508 1.728 64.804 28.248 ;
     RECT  64.804 21.648 64.973 25.08 ;
     RECT  64.804 26.112 65.173 28.248 ;
     RECT  64.973 21.648 65.189 24.984 ;
     RECT  64.804 1.728 65.261 3.096 ;
     RECT  65.189 24.96 65.513 24.984 ;
     RECT  65.173 26.112 65.621 28.488 ;
     RECT  65.261 2.256 65.989 3.096 ;
     RECT  65.989 2.256 66.125 3.336 ;
     RECT  65.621 26.208 66.125 28.488 ;
     RECT  66.125 2.256 66.277 3.24 ;
     RECT  65.189 21.648 66.517 23.976 ;
     RECT  66.517 21.648 66.553 24.072 ;
     RECT  66.092 25.056 66.553 25.08 ;
     RECT  66.553 21.648 66.565 25.08 ;
     RECT  66.565 21.552 66.589 25.08 ;
     RECT  66.125 26.208 66.589 27.96 ;
     RECT  66.277 29.04 66.701 29.064 ;
     RECT  66.589 21.552 67.093 27.96 ;
     RECT  66.277 1.728 67.208 3.24 ;
     RECT  64.804 15.264 67.208 15.288 ;
     RECT  67.093 21.552 67.208 28.488 ;
     RECT  67.208 1.728 67.504 28.488 ;
     RECT  67.504 22.224 67.619 28.488 ;
     RECT  67.619 27.936 67.669 28.488 ;
     RECT  67.669 27.936 67.811 28.584 ;
     RECT  67.504 1.728 67.889 3 ;
     RECT  67.909 29.088 68.249 29.112 ;
     RECT  67.619 22.224 68.393 26.952 ;
     RECT  68.393 22.704 68.749 26.952 ;
     RECT  67.811 27.936 68.749 27.96 ;
     RECT  68.749 22.704 68.773 27.96 ;
     RECT  68.773 22.704 68.861 29.064 ;
     RECT  67.889 1.728 69.301 2.856 ;
     RECT  68.861 22.704 69.469 27.96 ;
     RECT  69.301 1.728 69.637 3.096 ;
     RECT  69.637 1.728 69.781 3.432 ;
     RECT  69.469 22.56 69.865 27.96 ;
     RECT  68.861 29.04 69.865 29.064 ;
     RECT  69.781 1.728 69.908 3.48 ;
     RECT  67.504 15.264 69.908 15.288 ;
     RECT  69.865 22.56 69.908 29.064 ;
     RECT  69.908 1.728 70.204 29.064 ;
     RECT  70.204 22.176 70.355 29.064 ;
     RECT  70.204 1.728 70.445 3.432 ;
     RECT  70.445 1.728 70.451 3 ;
     RECT  69.781 0.192 70.547 0.216 ;
     RECT  70.355 22.176 70.589 28.488 ;
     RECT  70.589 23.904 70.697 28.488 ;
     RECT  70.204 15.168 70.733 15.288 ;
     RECT  70.589 22.176 70.949 22.776 ;
     RECT  70.949 22.512 71.021 22.776 ;
     RECT  70.697 23.904 71.021 28.056 ;
     RECT  71.021 26.112 71.309 28.056 ;
     RECT  70.451 1.728 71.849 1.752 ;
     RECT  70.451 2.832 71.989 3 ;
     RECT  71.797 29.088 72.085 29.112 ;
     RECT  71.309 26.208 72.305 28.056 ;
     RECT  72.085 29.088 72.305 29.16 ;
     RECT  71.989 2.784 72.325 3 ;
     RECT  72.305 26.208 72.353 29.16 ;
     RECT  71.021 23.904 72.373 25.128 ;
     RECT  72.353 26.208 72.373 28.536 ;
     RECT  71.021 22.752 72.421 22.776 ;
     RECT  72.373 23.904 72.421 28.536 ;
     RECT  72.325 2.784 72.457 3.336 ;
     RECT  72.421 22.368 72.469 22.776 ;
     RECT  72.421 23.856 72.469 28.536 ;
     RECT  72.457 2.016 72.608 3.336 ;
     RECT  70.733 15.264 72.608 15.288 ;
     RECT  72.469 22.368 72.608 28.536 ;
     RECT  72.608 2.016 72.904 28.536 ;
     RECT  72.904 21.648 72.965 28.536 ;
     RECT  73.141 29.664 73.325 29.688 ;
     RECT  72.904 2.016 73.429 2.952 ;
     RECT  72.965 21.648 73.657 28.488 ;
     RECT  73.657 21.648 73.909 24.552 ;
     RECT  73.957 18.816 74.099 18.84 ;
     RECT  74.389 13.632 74.473 13.656 ;
     RECT  73.429 1.728 74.533 2.952 ;
     RECT  73.657 25.68 74.821 28.488 ;
     RECT  73.909 21.12 74.869 24.552 ;
     RECT  74.821 25.68 74.869 28.536 ;
     RECT  74.869 21.12 75.053 28.536 ;
     RECT  74.533 1.728 75.109 3 ;
     RECT  75.109 1.728 75.308 3.048 ;
     RECT  74.473 13.104 75.308 13.656 ;
     RECT  72.904 15.264 75.308 15.288 ;
     RECT  75.053 21.12 75.308 28.248 ;
     RECT  75.308 1.728 75.395 28.248 ;
     RECT  75.395 1.728 75.604 28.2 ;
     RECT  75.604 12 75.745 12.552 ;
     RECT  75.604 22.128 75.779 28.2 ;
     RECT  75.604 1.728 75.845 2.856 ;
     RECT  75.745 12.528 75.917 12.552 ;
     RECT  75.845 2.832 76.285 2.856 ;
     RECT  75.845 1.728 76.349 1.8 ;
     RECT  75.604 21.12 76.355 21.144 ;
     RECT  75.779 22.128 76.393 28.056 ;
     RECT  76.393 25.728 76.403 28.056 ;
     RECT  75.604 3.984 76.601 4.008 ;
     RECT  76.393 22.128 76.705 24.696 ;
     RECT  76.813 13.104 76.877 13.128 ;
     RECT  76.805 3.408 76.889 3.432 ;
     RECT  76.877 13.104 76.961 13.656 ;
     RECT  76.403 26.208 77.281 28.056 ;
     RECT  77.317 3.072 77.381 3.096 ;
     RECT  77.281 26.208 77.413 28.488 ;
     RECT  77.381 2.832 77.461 3.096 ;
     RECT  77.413 25.68 77.557 28.488 ;
     RECT  77.125 13.008 77.605 13.032 ;
     RECT  76.349 1.728 77.845 1.752 ;
     RECT  77.461 2.736 77.845 3.096 ;
     RECT  77.845 1.728 78.008 3.096 ;
     RECT  77.605 12.528 78.008 13.032 ;
     RECT  75.604 15.264 78.008 15.288 ;
     RECT  76.705 21.6 78.008 24.696 ;
     RECT  77.557 25.68 78.008 29.064 ;
     RECT  78.008 1.728 78.112 29.064 ;
     RECT  78.112 28.944 78.133 29.064 ;
     RECT  78.112 1.728 78.304 27.96 ;
     RECT  78.304 21.12 78.467 27.96 ;
     RECT  78.304 1.728 78.689 2.856 ;
     RECT  78.133 28.944 78.829 29.112 ;
     RECT  78.467 21.12 78.841 25.8 ;
     RECT  78.841 22.752 79.013 25.8 ;
     RECT  78.467 26.784 79.049 27.96 ;
     RECT  78.829 28.944 79.121 29.688 ;
     RECT  79.013 22.752 79.187 24.6 ;
     RECT  79.187 22.752 79.193 24.552 ;
     RECT  79.193 22.8 79.265 24.552 ;
     RECT  79.237 28.464 79.373 28.488 ;
     RECT  79.013 25.584 79.469 25.8 ;
     RECT  79.049 26.784 79.469 27.48 ;
     RECT  78.841 21.12 79.477 21.672 ;
     RECT  78.689 2.832 79.505 2.856 ;
     RECT  79.505 2.832 79.573 3.144 ;
     RECT  78.689 1.728 79.657 1.8 ;
     RECT  79.573 2.832 79.657 3.96 ;
     RECT  78.304 12.384 79.717 12.408 ;
     RECT  79.121 29.664 79.763 29.688 ;
     RECT  79.469 25.584 80.053 27.48 ;
     RECT  79.265 23.04 80.197 24.552 ;
     RECT  80.053 25.584 80.197 27.96 ;
     RECT  79.657 1.728 80.237 3.96 ;
     RECT  80.197 23.04 80.413 27.96 ;
     RECT  79.477 21.072 80.485 21.672 ;
     RECT  80.413 22.944 80.485 27.96 ;
     RECT  80.237 2.016 80.675 3.96 ;
     RECT  80.675 2.148 80.708 3.96 ;
     RECT  79.717 12 80.708 12.408 ;
     RECT  78.304 15.168 80.708 15.192 ;
     RECT  80.485 21.072 80.708 27.96 ;
     RECT  80.629 29.04 80.708 29.064 ;
     RECT  80.708 2.148 80.713 29.064 ;
     RECT  80.713 2.148 80.812 28.536 ;
     RECT  80.581 0.288 80.915 0.312 ;
     RECT  80.812 2.256 81.004 28.536 ;
     RECT  81.004 28.176 81.101 28.536 ;
     RECT  81.004 21.504 81.155 23.928 ;
     RECT  81.155 21.648 81.209 23.928 ;
     RECT  81.209 21.648 81.281 22.824 ;
     RECT  81.101 28.512 81.353 28.536 ;
     RECT  81.004 25.104 81.361 25.128 ;
     RECT  81.004 18.864 81.389 18.888 ;
     RECT  81.281 21.648 81.425 22.776 ;
     RECT  81.004 2.256 81.491 4.008 ;
     RECT  81.004 26.208 81.569 26.808 ;
     RECT  81.491 2.256 81.779 3.432 ;
     RECT  81.425 22.464 81.875 22.776 ;
     RECT  81.779 2.832 81.901 3.432 ;
     RECT  81.569 26.784 81.971 26.808 ;
     RECT  81.209 23.904 82.009 23.928 ;
     RECT  81.901 3.408 82.019 3.432 ;
     RECT  81.673 29.664 82.019 29.688 ;
     RECT  81.875 22.464 82.073 22.488 ;
    LAYER M5 ;
     RECT  4.536 0.144 4.8 0.192 ;
     RECT  4.824 0.144 5.088 0.192 ;
     RECT  5.112 0.144 5.328 0.192 ;
     RECT  5.352 0.144 5.616 0.192 ;
     RECT  5.64 0.144 5.904 0.192 ;
     RECT  5.928 0.144 6.192 0.192 ;
     RECT  6.216 0.144 6.432 0.192 ;
     RECT  6.456 0.144 6.72 0.192 ;
     RECT  6.744 0.144 7.008 0.192 ;
     RECT  7.032 0.144 7.296 0.192 ;
     RECT  7.32 0.144 7.536 0.192 ;
     RECT  7.56 0.144 7.824 0.192 ;
     RECT  7.848 0.144 8.112 0.192 ;
     RECT  8.136 0.144 8.352 0.192 ;
     RECT  8.376 0.144 8.64 0.192 ;
     RECT  8.664 0.144 8.928 0.192 ;
     RECT  8.952 0.144 9.216 0.192 ;
     RECT  9.24 0.144 9.456 0.192 ;
     RECT  9.48 0.144 9.744 0.192 ;
     RECT  9.768 0.144 10.032 0.192 ;
     RECT  10.056 0.144 10.32 0.192 ;
     RECT  10.344 0.144 10.56 0.192 ;
     RECT  10.584 0.144 10.848 0.192 ;
     RECT  10.872 0.144 11.136 0.192 ;
     RECT  11.16 0.144 11.424 0.192 ;
     RECT  11.448 0.144 11.664 0.192 ;
     RECT  11.688 0.144 11.952 0.192 ;
     RECT  11.976 0.144 12.24 0.192 ;
     RECT  12.264 0.144 12.528 0.192 ;
     RECT  12.552 0.144 12.768 0.192 ;
     RECT  12.792 0.144 13.056 0.192 ;
     RECT  13.08 0.144 13.344 0.192 ;
     RECT  13.368 0.144 13.632 0.192 ;
     RECT  13.656 0.144 13.872 0.192 ;
     RECT  13.896 0.144 14.16 0.192 ;
     RECT  14.184 0.144 14.448 0.192 ;
     RECT  14.472 0.144 14.736 0.192 ;
     RECT  14.76 0.144 14.976 0.192 ;
     RECT  15 0.144 15.264 0.192 ;
     RECT  15.288 0.144 15.552 0.192 ;
     RECT  15.576 0.144 15.84 0.192 ;
     RECT  15.864 0.144 16.08 0.192 ;
     RECT  16.104 0.144 16.368 0.192 ;
     RECT  16.392 0.144 16.656 0.192 ;
     RECT  16.68 0.144 16.944 0.192 ;
     RECT  16.968 0.144 17.184 0.192 ;
     RECT  17.208 0.144 17.472 0.192 ;
     RECT  17.496 0.144 17.76 0.192 ;
     RECT  17.784 0.144 18.048 0.192 ;
     RECT  18.072 0.144 18.288 0.192 ;
     RECT  18.312 0.144 18.576 0.192 ;
     RECT  18.6 0.144 18.864 0.192 ;
     RECT  18.888 0.144 19.152 0.192 ;
     RECT  19.176 0.144 19.392 0.192 ;
     RECT  19.416 0.144 19.68 0.192 ;
     RECT  19.704 0.144 19.968 0.192 ;
     RECT  19.992 0.144 20.256 0.192 ;
     RECT  20.28 0.144 20.496 0.192 ;
     RECT  20.52 0.144 20.784 0.192 ;
     RECT  20.808 0.144 21.072 0.192 ;
     RECT  21.096 0.144 21.312 0.192 ;
     RECT  21.336 0.144 21.6 0.192 ;
     RECT  21.624 0.144 21.888 0.192 ;
     RECT  21.912 0.144 22.176 0.192 ;
     RECT  22.2 0.144 22.416 0.192 ;
     RECT  22.44 0.144 22.704 0.192 ;
     RECT  22.728 0.144 22.992 0.192 ;
     RECT  23.016 0.144 23.28 0.192 ;
     RECT  23.304 0.144 23.52 0.192 ;
     RECT  23.544 0.144 23.808 0.192 ;
     RECT  23.832 0.144 24.096 0.192 ;
     RECT  24.12 0.144 24.384 0.192 ;
     RECT  24.408 0.144 24.624 0.192 ;
     RECT  24.648 0.144 24.912 0.192 ;
     RECT  24.936 0.144 25.2 0.192 ;
     RECT  25.224 0.144 25.488 0.192 ;
     RECT  25.512 0.144 25.728 0.192 ;
     RECT  25.752 0.144 26.016 0.192 ;
     RECT  26.04 0.144 26.304 0.192 ;
     RECT  26.328 0.144 26.592 0.192 ;
     RECT  26.616 0.144 26.832 0.192 ;
     RECT  26.856 0.144 27.12 0.192 ;
     RECT  27.144 0.144 27.408 0.192 ;
     RECT  27.432 0.144 27.696 0.192 ;
     RECT  27.72 0.144 27.936 0.192 ;
     RECT  27.96 0.144 28.224 0.192 ;
     RECT  28.248 0.144 28.512 0.192 ;
     RECT  28.536 0.144 28.8 0.192 ;
     RECT  28.824 0.144 29.04 0.192 ;
     RECT  29.064 0.144 29.328 0.192 ;
     RECT  29.352 0.144 29.616 0.192 ;
     RECT  29.64 0.144 29.904 0.192 ;
     RECT  29.928 0.144 30.144 0.192 ;
     RECT  30.168 0.144 30.432 0.192 ;
     RECT  30.456 0.144 30.72 0.192 ;
     RECT  30.744 0.144 31.008 0.192 ;
     RECT  31.032 0.144 31.248 0.192 ;
     RECT  31.272 0.144 31.536 0.192 ;
     RECT  31.56 0.144 31.824 0.192 ;
     RECT  31.848 0.144 32.112 0.192 ;
     RECT  32.136 0.144 32.352 0.192 ;
     RECT  32.376 0.144 32.64 0.192 ;
     RECT  32.664 0.144 32.928 0.192 ;
     RECT  32.952 0.144 33.216 0.192 ;
     RECT  33.24 0.144 33.456 0.192 ;
     RECT  33.48 0.144 33.744 0.192 ;
     RECT  33.768 0.144 34.032 0.192 ;
     RECT  34.056 0.144 34.272 0.192 ;
     RECT  34.296 0.144 34.56 0.192 ;
     RECT  34.584 0.144 34.848 0.192 ;
     RECT  34.872 0.144 35.136 0.192 ;
     RECT  35.16 0.144 35.376 0.192 ;
     RECT  35.4 0.144 35.664 0.192 ;
     RECT  35.688 0.144 35.952 0.192 ;
     RECT  35.976 0.144 36.24 0.192 ;
     RECT  36.264 0.144 36.48 0.192 ;
     RECT  36.504 0.144 36.768 0.192 ;
     RECT  36.792 0.144 37.056 0.192 ;
     RECT  37.08 0.144 37.344 0.192 ;
     RECT  37.368 0.144 37.584 0.192 ;
     RECT  37.608 0.144 37.872 0.192 ;
     RECT  37.896 0.144 38.16 0.192 ;
     RECT  38.184 0.144 38.448 0.192 ;
     RECT  38.472 0.144 38.688 0.192 ;
     RECT  38.712 0.144 38.976 0.192 ;
     RECT  39 0.144 39.264 0.192 ;
     RECT  39.288 0.144 39.552 0.192 ;
     RECT  39.576 0.144 39.792 0.192 ;
     RECT  39.816 0.144 40.08 0.192 ;
     RECT  40.104 0.144 40.368 0.192 ;
     RECT  40.392 0.144 40.656 0.192 ;
     RECT  40.68 0.144 40.896 0.192 ;
     RECT  40.92 0.144 41.184 0.192 ;
     RECT  41.208 0.144 41.472 0.192 ;
     RECT  41.496 0.144 41.76 0.192 ;
     RECT  41.784 0.144 42 0.192 ;
     RECT  42.024 0.144 42.288 0.192 ;
     RECT  42.312 0.144 42.576 0.192 ;
     RECT  42.6 0.144 42.864 0.192 ;
     RECT  42.888 0.144 43.104 0.192 ;
     RECT  43.128 0.144 43.392 0.192 ;
     RECT  43.416 0.144 43.68 0.192 ;
     RECT  43.704 0.144 43.968 0.192 ;
     RECT  43.992 0.144 44.208 0.192 ;
     RECT  44.232 0.144 44.496 0.192 ;
     RECT  44.52 0.144 44.784 0.192 ;
     RECT  44.808 0.144 45.072 0.192 ;
     RECT  45.096 0.144 45.312 0.192 ;
     RECT  45.336 0.144 45.6 0.192 ;
     RECT  45.624 0.144 45.888 0.192 ;
     RECT  45.912 0.144 46.176 0.192 ;
     RECT  46.2 0.144 46.416 0.192 ;
     RECT  46.44 0.144 46.704 0.192 ;
     RECT  46.728 0.144 46.992 0.192 ;
     RECT  47.016 0.144 47.232 0.192 ;
     RECT  47.256 0.144 47.52 0.192 ;
     RECT  47.544 0.144 47.808 0.192 ;
     RECT  47.832 0.144 48.096 0.192 ;
     RECT  48.12 0.144 48.336 0.192 ;
     RECT  48.36 0.144 48.624 0.192 ;
     RECT  48.648 0.144 48.912 0.192 ;
     RECT  48.936 0.144 49.2 0.192 ;
     RECT  49.224 0.144 49.44 0.192 ;
     RECT  49.464 0.144 49.728 0.192 ;
     RECT  49.752 0.144 50.016 0.192 ;
     RECT  50.04 0.144 50.304 0.192 ;
     RECT  50.328 0.144 50.544 0.192 ;
     RECT  50.568 0.144 50.832 0.192 ;
     RECT  50.856 0.144 51.12 0.192 ;
     RECT  51.144 0.144 51.408 0.192 ;
     RECT  51.432 0.144 51.648 0.192 ;
     RECT  51.672 0.144 51.936 0.192 ;
     RECT  51.96 0.144 52.224 0.192 ;
     RECT  52.248 0.144 52.512 0.192 ;
     RECT  52.536 0.144 52.752 0.192 ;
     RECT  52.776 0.144 53.04 0.192 ;
     RECT  53.064 0.144 53.328 0.192 ;
     RECT  53.352 0.144 53.616 0.192 ;
     RECT  53.64 0.144 53.856 0.192 ;
     RECT  53.88 0.144 54.144 0.192 ;
     RECT  54.168 0.144 54.432 0.192 ;
     RECT  54.456 0.144 54.72 0.192 ;
     RECT  54.744 0.144 54.96 0.192 ;
     RECT  54.984 0.144 55.248 0.192 ;
     RECT  55.272 0.144 55.536 0.192 ;
     RECT  55.56 0.144 55.824 0.192 ;
     RECT  55.848 0.144 56.064 0.192 ;
     RECT  56.088 0.144 56.352 0.192 ;
     RECT  56.376 0.144 56.64 0.192 ;
     RECT  56.664 0.144 56.928 0.192 ;
     RECT  56.952 0.144 57.168 0.192 ;
     RECT  57.192 0.144 57.456 0.192 ;
     RECT  57.48 0.144 57.744 0.192 ;
     RECT  57.768 0.144 58.032 0.192 ;
     RECT  58.056 0.144 58.272 0.192 ;
     RECT  58.296 0.144 58.56 0.192 ;
     RECT  58.584 0.144 58.848 0.192 ;
     RECT  58.872 0.144 59.136 0.192 ;
     RECT  59.16 0.144 59.376 0.192 ;
     RECT  59.4 0.144 59.664 0.192 ;
     RECT  59.688 0.144 59.952 0.192 ;
     RECT  59.976 0.144 60.192 0.192 ;
     RECT  60.216 0.144 60.48 0.192 ;
     RECT  60.504 0.144 60.768 0.192 ;
     RECT  60.792 0.144 61.056 0.192 ;
     RECT  61.08 0.144 61.296 0.192 ;
     RECT  61.32 0.144 61.584 0.192 ;
     RECT  61.608 0.144 61.872 0.192 ;
     RECT  61.896 0.144 62.16 0.192 ;
     RECT  62.184 0.144 62.4 0.192 ;
     RECT  62.424 0.144 62.688 0.192 ;
     RECT  62.712 0.144 62.976 0.192 ;
     RECT  63 0.144 63.264 0.192 ;
     RECT  63.288 0.144 63.504 0.192 ;
     RECT  63.528 0.144 63.792 0.192 ;
     RECT  63.816 0.144 64.08 0.192 ;
     RECT  64.104 0.144 64.368 0.192 ;
     RECT  64.392 0.144 64.608 0.192 ;
     RECT  64.632 0.144 64.896 0.192 ;
     RECT  64.92 0.144 65.184 0.192 ;
     RECT  65.208 0.144 65.472 0.192 ;
     RECT  65.496 0.144 65.712 0.192 ;
     RECT  65.736 0.144 66 0.192 ;
     RECT  66.024 0.144 66.288 0.192 ;
     RECT  66.312 0.144 66.576 0.192 ;
     RECT  66.6 0.144 66.816 0.192 ;
     RECT  66.84 0.144 67.104 0.192 ;
     RECT  67.128 0.144 67.392 0.192 ;
     RECT  67.416 0.144 67.68 0.192 ;
     RECT  67.704 0.144 67.92 0.192 ;
     RECT  67.944 0.144 68.208 0.192 ;
     RECT  68.232 0.144 68.496 0.192 ;
     RECT  68.52 0.144 68.784 0.192 ;
     RECT  68.808 0.144 69.024 0.192 ;
     RECT  69.048 0.144 69.312 0.192 ;
     RECT  69.336 0.144 69.6 0.192 ;
     RECT  69.624 0.144 69.888 0.192 ;
     RECT  69.912 0.144 70.128 0.192 ;
     RECT  70.152 0.144 70.416 0.192 ;
     RECT  70.44 0.144 70.704 0.192 ;
     RECT  70.728 0.144 70.992 0.192 ;
     RECT  71.016 0.144 71.232 0.192 ;
     RECT  71.256 0.144 71.52 0.192 ;
     RECT  71.544 0.144 71.808 0.192 ;
     RECT  71.832 0.144 72.096 0.192 ;
     RECT  72.12 0.144 72.336 0.192 ;
     RECT  72.36 0.144 72.624 0.192 ;
     RECT  72.648 0.144 72.912 0.192 ;
     RECT  72.936 0.144 73.152 0.192 ;
     RECT  73.176 0.144 73.44 0.192 ;
     RECT  73.464 0.144 73.728 0.192 ;
     RECT  73.752 0.144 74.016 0.192 ;
     RECT  74.04 0.144 74.256 0.192 ;
     RECT  74.28 0.144 74.544 0.192 ;
     RECT  74.568 0.144 74.832 0.192 ;
     RECT  74.856 0.144 75.12 0.192 ;
     RECT  75.144 0.144 75.36 0.192 ;
     RECT  75.384 0.144 75.648 0.192 ;
     RECT  75.672 0.144 75.936 0.192 ;
     RECT  75.96 0.144 76.224 0.192 ;
     RECT  76.248 0.144 76.464 0.192 ;
     RECT  76.488 0.144 76.752 0.192 ;
     RECT  76.776 0.144 77.04 0.192 ;
     RECT  77.064 0.144 77.328 0.192 ;
     RECT  77.352 0.144 77.568 0.192 ;
     RECT  77.592 0.144 77.856 0.192 ;
     RECT  77.88 0.144 78.144 0.192 ;
     RECT  78.168 0.144 78.432 0.192 ;
     RECT  78.456 0.144 78.672 0.192 ;
     RECT  78.696 0.144 78.96 0.192 ;
     RECT  78.984 0.144 79.248 0.192 ;
     RECT  79.272 0.144 79.536 0.192 ;
     RECT  79.56 0.144 79.776 0.192 ;
     RECT  79.8 0.144 80.064 0.192 ;
     RECT  80.088 0.144 80.352 0.192 ;
     RECT  80.376 0.144 80.64 0.192 ;
     RECT  80.664 0.144 80.88 0.192 ;
     RECT  80.904 0.144 81.168 0.192 ;
     RECT  81.192 0.144 81.456 0.192 ;
     RECT  81.48 0.144 81.744 0.192 ;
     RECT  81.768 0.144 81.984 0.192 ;
     RECT  4.512 0.192 82.008 1.763 ;
     RECT  5.088 1.763 29.832 1.811 ;
     RECT  31.008 1.763 76.248 1.811 ;
     RECT  77.328 1.763 82.008 1.811 ;
     RECT  7.296 1.811 19.704 1.859 ;
     RECT  77.328 1.811 78.552 1.859 ;
     RECT  5.088 1.811 5.928 2.051 ;
     RECT  18.576 1.859 19.704 2.051 ;
     RECT  2.4 2.137 2.52 2.151 ;
     RECT  7.296 1.859 17.592 2.291 ;
     RECT  31.008 1.811 75.72 2.291 ;
     RECT  5.1 2.051 5.928 2.339 ;
     RECT  18.6 2.051 19.704 2.773 ;
     RECT  18.6 2.773 19.752 2.821 ;
     RECT  21.072 1.811 29.832 2.821 ;
     RECT  31.008 2.291 57.48 2.821 ;
     RECT  58.56 2.291 75.72 2.821 ;
     RECT  77.328 1.859 78.504 2.821 ;
     RECT  79.536 1.811 82.008 2.821 ;
     RECT  58.56 2.821 76.248 2.915 ;
     RECT  58.608 2.915 76.248 2.963 ;
     RECT  7.632 2.291 17.592 3.107 ;
     RECT  18.6 2.821 57.48 3.107 ;
     RECT  63.264 2.963 76.248 3.107 ;
     RECT  63.936 3.107 76.248 3.397 ;
     RECT  77.328 2.821 82.008 3.397 ;
     RECT  63.936 3.397 82.008 3.443 ;
     RECT  7.632 3.107 10.812 4.117 ;
     RECT  18.6 3.107 54.456 14.867 ;
     RECT  52.368 14.867 54.456 21.109 ;
     RECT  0.24 15.109 0.264 21.251 ;
     RECT  58.608 2.963 62.112 21.541 ;
     RECT  63.936 3.443 81.864 21.541 ;
     RECT  12.192 3.107 17.592 21.637 ;
     RECT  18.6 14.867 51.312 21.637 ;
     RECT  52.368 21.109 54.552 21.637 ;
     RECT  55.536 3.107 57.336 21.637 ;
     RECT  6.72 4.117 10.812 21.683 ;
     RECT  52.368 21.637 57.336 22.165 ;
     RECT  58.56 21.541 62.112 22.165 ;
     RECT  7.632 21.683 10.812 22.549 ;
     RECT  63.264 21.541 81.864 22.787 ;
     RECT  12.192 21.637 51.312 23.077 ;
     RECT  52.368 22.165 62.112 23.077 ;
     RECT  5.1 2.339 5.412 23.317 ;
     RECT  5.1 23.317 5.736 23.749 ;
     RECT  5.1 23.749 5.928 23.845 ;
     RECT  63.264 22.787 81.336 23.893 ;
     RECT  5.1 23.845 6.216 24.659 ;
     RECT  7.632 22.549 10.92 24.659 ;
     RECT  63.264 23.893 81.96 24.949 ;
     RECT  12.192 23.077 62.112 25.093 ;
     RECT  63.168 24.949 81.96 25.093 ;
     RECT  12.192 25.093 81.96 25.139 ;
     RECT  5.1 24.659 5.592 25.141 ;
     RECT  4.752 25.141 5.592 25.283 ;
     RECT  12.192 25.139 63.192 25.667 ;
     RECT  5.1 25.283 5.592 25.669 ;
     RECT  3.744 25.045 3.768 25.715 ;
     RECT  2.4 2.151 2.712 25.717 ;
     RECT  64.224 25.139 81.96 25.763 ;
     RECT  12.192 25.667 32.412 25.859 ;
     RECT  64.224 25.763 74.088 25.859 ;
     RECT  7.632 24.659 10.812 25.861 ;
     RECT  5.1 25.669 5.784 26.147 ;
     RECT  12.672 25.859 32.412 26.243 ;
     RECT  33.6 25.667 63.192 26.243 ;
     RECT  64.5 25.859 74.088 26.243 ;
     RECT  75.12 25.763 81.96 26.243 ;
     RECT  12.816 26.243 32.412 26.291 ;
     RECT  33.6 26.243 60.168 26.291 ;
     RECT  61.2 26.243 62.232 26.339 ;
     RECT  14.976 26.291 25.128 26.387 ;
     RECT  34.032 26.291 60.168 26.387 ;
     RECT  7.632 25.861 11.16 26.677 ;
     RECT  59.1 26.387 60.168 26.771 ;
     RECT  20.496 26.387 25.128 26.819 ;
     RECT  26.112 26.291 32.412 26.819 ;
     RECT  34.032 26.387 57.912 26.819 ;
     RECT  61.248 26.339 62.232 26.819 ;
     RECT  69.792 26.243 74.088 26.819 ;
     RECT  77.28 26.243 81.96 26.819 ;
     RECT  7.008 26.677 11.16 26.867 ;
     RECT  14.976 26.387 19.416 26.867 ;
     RECT  23.52 26.819 24.648 26.867 ;
     RECT  36.768 26.819 43.992 26.867 ;
     RECT  45.216 26.819 57.768 26.867 ;
     RECT  64.5 26.243 67.704 26.867 ;
     RECT  14.976 26.867 16.488 26.915 ;
     RECT  26.112 26.819 29.712 26.915 ;
     RECT  53.136 26.867 57.768 26.963 ;
     RECT  71.52 26.819 74.088 27.011 ;
     RECT  75.12 26.243 75.816 27.253 ;
     RECT  77.28 26.819 81.768 27.253 ;
     RECT  26.112 26.915 27.144 27.301 ;
     RECT  64.5 26.867 64.812 27.301 ;
     RECT  68.784 26.243 68.808 27.301 ;
     RECT  69.792 26.819 70.344 27.301 ;
     RECT  7.008 26.867 8.112 27.349 ;
     RECT  59.1 26.771 59.784 27.349 ;
     RECT  17.472 26.867 19.416 27.395 ;
     RECT  34.032 26.819 35.784 27.395 ;
     RECT  31.008 26.819 32.412 27.829 ;
     RECT  37.344 26.867 43.992 27.877 ;
     RECT  45.216 26.867 48.612 27.877 ;
     RECT  68.784 27.301 70.344 27.877 ;
     RECT  71.52 27.011 71.544 27.877 ;
     RECT  2.4 25.717 2.808 27.925 ;
     RECT  6.72 27.349 8.112 27.925 ;
     RECT  9.216 26.867 9.24 27.925 ;
     RECT  10.5 26.867 11.16 27.925 ;
     RECT  12.816 26.291 13.944 27.925 ;
     RECT  14.976 26.915 16.392 27.925 ;
     RECT  17.472 27.395 19.176 27.925 ;
     RECT  20.496 26.819 22.2 27.925 ;
     RECT  23.808 26.867 24.648 27.925 ;
     RECT  25.728 27.301 27.144 27.925 ;
     RECT  28.224 26.915 29.712 27.925 ;
     RECT  30.72 27.829 32.412 27.925 ;
     RECT  34.032 27.395 35.4 27.925 ;
     RECT  36.768 27.877 43.992 27.925 ;
     RECT  45.216 27.877 48.744 27.925 ;
     RECT  50.016 26.867 51.312 27.925 ;
     RECT  53.328 26.963 57.768 27.925 ;
     RECT  58.992 27.349 59.784 27.925 ;
     RECT  61.8 26.819 62.232 27.925 ;
     RECT  63.264 27.301 64.812 27.925 ;
     RECT  66 26.867 67.704 27.925 ;
     RECT  68.784 27.877 71.544 27.925 ;
     RECT  20.256 27.925 22.2 27.973 ;
     RECT  36.768 27.925 48.936 27.973 ;
     RECT  50.016 27.925 51.432 27.973 ;
     RECT  63.264 27.925 64.92 27.973 ;
     RECT  66 27.925 71.544 27.973 ;
     RECT  72.6 27.011 74.088 27.973 ;
     RECT  75.12 27.253 81.768 27.973 ;
     RECT  23.808 27.925 27.144 28.405 ;
     RECT  28.224 27.925 35.4 28.405 ;
     RECT  2.4 27.925 3.528 28.453 ;
     RECT  6.72 27.925 11.16 28.453 ;
     RECT  12.24 27.925 19.176 28.453 ;
     RECT  20.256 27.973 22.728 28.453 ;
     RECT  23.808 28.405 35.4 28.453 ;
     RECT  36.768 27.973 51.672 28.453 ;
     RECT  63.264 27.973 71.544 28.453 ;
     RECT  72.6 27.973 81.768 28.453 ;
     RECT  5.1 26.147 5.544 28.501 ;
     RECT  6.72 28.453 19.176 28.501 ;
     RECT  52.752 27.925 59.784 28.501 ;
     RECT  60.768 27.925 62.232 28.501 ;
     RECT  63.264 28.453 81.768 28.501 ;
     RECT  20.256 28.453 51.672 28.933 ;
     RECT  52.752 28.501 81.768 28.933 ;
     RECT  5.1 28.501 19.176 28.981 ;
     RECT  5.088 28.981 19.176 29.029 ;
     RECT  4.512 29.029 19.176 29.077 ;
     RECT  20.256 28.933 81.768 29.077 ;
     RECT  4.512 29.077 81.768 29.653 ;
     RECT  2.352 28.453 3.528 30.048 ;
     RECT  2.376 30.048 2.64 30.096 ;
     RECT  2.664 30.048 2.928 30.096 ;
     RECT  2.952 30.048 3.216 30.096 ;
     RECT  3.24 30.048 3.504 30.096 ;
     RECT  4.512 29.653 82.008 30.048 ;
     RECT  4.536 30.048 4.8 30.096 ;
     RECT  4.824 30.048 5.088 30.096 ;
     RECT  5.112 30.048 5.328 30.096 ;
     RECT  5.352 30.048 5.616 30.096 ;
     RECT  5.64 30.048 5.904 30.096 ;
     RECT  5.928 30.048 6.192 30.096 ;
     RECT  6.216 30.048 6.432 30.096 ;
     RECT  6.456 30.048 6.72 30.096 ;
     RECT  6.744 30.048 7.008 30.096 ;
     RECT  7.032 30.048 7.296 30.096 ;
     RECT  7.32 30.048 7.536 30.096 ;
     RECT  7.56 30.048 7.824 30.096 ;
     RECT  7.848 30.048 8.112 30.096 ;
     RECT  8.136 30.048 8.352 30.096 ;
     RECT  8.376 30.048 8.64 30.096 ;
     RECT  8.664 30.048 8.928 30.096 ;
     RECT  8.952 30.048 9.216 30.096 ;
     RECT  9.24 30.048 9.456 30.096 ;
     RECT  9.48 30.048 9.744 30.096 ;
     RECT  9.768 30.048 10.032 30.096 ;
     RECT  10.056 30.048 10.32 30.096 ;
     RECT  10.344 30.048 10.56 30.096 ;
     RECT  10.584 30.048 10.848 30.096 ;
     RECT  10.872 30.048 11.136 30.096 ;
     RECT  11.16 30.048 11.424 30.096 ;
     RECT  11.448 30.048 11.664 30.096 ;
     RECT  11.688 30.048 11.952 30.096 ;
     RECT  11.976 30.048 12.24 30.096 ;
     RECT  12.264 30.048 12.528 30.096 ;
     RECT  12.552 30.048 12.768 30.096 ;
     RECT  12.792 30.048 13.056 30.096 ;
     RECT  13.08 30.048 13.344 30.096 ;
     RECT  13.368 30.048 13.632 30.096 ;
     RECT  13.656 30.048 13.872 30.096 ;
     RECT  13.896 30.048 14.16 30.096 ;
     RECT  14.184 30.048 14.448 30.096 ;
     RECT  14.472 30.048 14.736 30.096 ;
     RECT  14.76 30.048 14.976 30.096 ;
     RECT  15 30.048 15.264 30.096 ;
     RECT  15.288 30.048 15.552 30.096 ;
     RECT  15.576 30.048 15.84 30.096 ;
     RECT  15.864 30.048 16.08 30.096 ;
     RECT  16.104 30.048 16.368 30.096 ;
     RECT  16.392 30.048 16.656 30.096 ;
     RECT  16.68 30.048 16.944 30.096 ;
     RECT  16.968 30.048 17.184 30.096 ;
     RECT  17.208 30.048 17.472 30.096 ;
     RECT  17.496 30.048 17.76 30.096 ;
     RECT  17.784 30.048 18.048 30.096 ;
     RECT  18.072 30.048 18.288 30.096 ;
     RECT  18.312 30.048 18.576 30.096 ;
     RECT  18.6 30.048 18.864 30.096 ;
     RECT  18.888 30.048 19.152 30.096 ;
     RECT  19.176 30.048 19.392 30.096 ;
     RECT  19.416 30.048 19.68 30.096 ;
     RECT  19.704 30.048 19.968 30.096 ;
     RECT  19.992 30.048 20.256 30.096 ;
     RECT  20.28 30.048 20.496 30.096 ;
     RECT  20.52 30.048 20.784 30.096 ;
     RECT  20.808 30.048 21.072 30.096 ;
     RECT  21.096 30.048 21.312 30.096 ;
     RECT  21.336 30.048 21.6 30.096 ;
     RECT  21.624 30.048 21.888 30.096 ;
     RECT  21.912 30.048 22.176 30.096 ;
     RECT  22.2 30.048 22.416 30.096 ;
     RECT  22.44 30.048 22.704 30.096 ;
     RECT  22.728 30.048 22.992 30.096 ;
     RECT  23.016 30.048 23.28 30.096 ;
     RECT  23.304 30.048 23.52 30.096 ;
     RECT  23.544 30.048 23.808 30.096 ;
     RECT  23.832 30.048 24.096 30.096 ;
     RECT  24.12 30.048 24.384 30.096 ;
     RECT  24.408 30.048 24.624 30.096 ;
     RECT  24.648 30.048 24.912 30.096 ;
     RECT  24.936 30.048 25.2 30.096 ;
     RECT  25.224 30.048 25.488 30.096 ;
     RECT  25.512 30.048 25.728 30.096 ;
     RECT  25.752 30.048 26.016 30.096 ;
     RECT  26.04 30.048 26.304 30.096 ;
     RECT  26.328 30.048 26.592 30.096 ;
     RECT  26.616 30.048 26.832 30.096 ;
     RECT  26.856 30.048 27.12 30.096 ;
     RECT  27.144 30.048 27.408 30.096 ;
     RECT  27.432 30.048 27.696 30.096 ;
     RECT  27.72 30.048 27.936 30.096 ;
     RECT  27.96 30.048 28.224 30.096 ;
     RECT  28.248 30.048 28.512 30.096 ;
     RECT  28.536 30.048 28.8 30.096 ;
     RECT  28.824 30.048 29.04 30.096 ;
     RECT  29.064 30.048 29.328 30.096 ;
     RECT  29.352 30.048 29.616 30.096 ;
     RECT  29.64 30.048 29.904 30.096 ;
     RECT  29.928 30.048 30.144 30.096 ;
     RECT  30.168 30.048 30.432 30.096 ;
     RECT  30.456 30.048 30.72 30.096 ;
     RECT  30.744 30.048 31.008 30.096 ;
     RECT  31.032 30.048 31.248 30.096 ;
     RECT  31.272 30.048 31.536 30.096 ;
     RECT  31.56 30.048 31.824 30.096 ;
     RECT  31.848 30.048 32.112 30.096 ;
     RECT  32.136 30.048 32.352 30.096 ;
     RECT  32.376 30.048 32.64 30.096 ;
     RECT  32.664 30.048 32.928 30.096 ;
     RECT  32.952 30.048 33.216 30.096 ;
     RECT  33.24 30.048 33.456 30.096 ;
     RECT  33.48 30.048 33.744 30.096 ;
     RECT  33.768 30.048 34.032 30.096 ;
     RECT  34.056 30.048 34.272 30.096 ;
     RECT  34.296 30.048 34.56 30.096 ;
     RECT  34.584 30.048 34.848 30.096 ;
     RECT  34.872 30.048 35.136 30.096 ;
     RECT  35.16 30.048 35.376 30.096 ;
     RECT  35.4 30.048 35.664 30.096 ;
     RECT  35.688 30.048 35.952 30.096 ;
     RECT  35.976 30.048 36.24 30.096 ;
     RECT  36.264 30.048 36.48 30.096 ;
     RECT  36.504 30.048 36.768 30.096 ;
     RECT  36.792 30.048 37.056 30.096 ;
     RECT  37.08 30.048 37.344 30.096 ;
     RECT  37.368 30.048 37.584 30.096 ;
     RECT  37.608 30.048 37.872 30.096 ;
     RECT  37.896 30.048 38.16 30.096 ;
     RECT  38.184 30.048 38.448 30.096 ;
     RECT  38.472 30.048 38.688 30.096 ;
     RECT  38.712 30.048 38.976 30.096 ;
     RECT  39 30.048 39.264 30.096 ;
     RECT  39.288 30.048 39.552 30.096 ;
     RECT  39.576 30.048 39.792 30.096 ;
     RECT  39.816 30.048 40.08 30.096 ;
     RECT  40.104 30.048 40.368 30.096 ;
     RECT  40.392 30.048 40.656 30.096 ;
     RECT  40.68 30.048 40.896 30.096 ;
     RECT  40.92 30.048 41.184 30.096 ;
     RECT  41.208 30.048 41.472 30.096 ;
     RECT  41.496 30.048 41.76 30.096 ;
     RECT  41.784 30.048 42 30.096 ;
     RECT  42.024 30.048 42.288 30.096 ;
     RECT  42.312 30.048 42.576 30.096 ;
     RECT  42.6 30.048 42.864 30.096 ;
     RECT  42.888 30.048 43.104 30.096 ;
     RECT  43.128 30.048 43.392 30.096 ;
     RECT  43.416 30.048 43.68 30.096 ;
     RECT  43.704 30.048 43.968 30.096 ;
     RECT  43.992 30.048 44.208 30.096 ;
     RECT  44.232 30.048 44.496 30.096 ;
     RECT  44.52 30.048 44.784 30.096 ;
     RECT  44.808 30.048 45.072 30.096 ;
     RECT  45.096 30.048 45.312 30.096 ;
     RECT  45.336 30.048 45.6 30.096 ;
     RECT  45.624 30.048 45.888 30.096 ;
     RECT  45.912 30.048 46.176 30.096 ;
     RECT  46.2 30.048 46.416 30.096 ;
     RECT  46.44 30.048 46.704 30.096 ;
     RECT  46.728 30.048 46.992 30.096 ;
     RECT  47.016 30.048 47.232 30.096 ;
     RECT  47.256 30.048 47.52 30.096 ;
     RECT  47.544 30.048 47.808 30.096 ;
     RECT  47.832 30.048 48.096 30.096 ;
     RECT  48.12 30.048 48.336 30.096 ;
     RECT  48.36 30.048 48.624 30.096 ;
     RECT  48.648 30.048 48.912 30.096 ;
     RECT  48.936 30.048 49.2 30.096 ;
     RECT  49.224 30.048 49.44 30.096 ;
     RECT  49.464 30.048 49.728 30.096 ;
     RECT  49.752 30.048 50.016 30.096 ;
     RECT  50.04 30.048 50.304 30.096 ;
     RECT  50.328 30.048 50.544 30.096 ;
     RECT  50.568 30.048 50.832 30.096 ;
     RECT  50.856 30.048 51.12 30.096 ;
     RECT  51.144 30.048 51.408 30.096 ;
     RECT  51.432 30.048 51.648 30.096 ;
     RECT  51.672 30.048 51.936 30.096 ;
     RECT  51.96 30.048 52.224 30.096 ;
     RECT  52.248 30.048 52.512 30.096 ;
     RECT  52.536 30.048 52.752 30.096 ;
     RECT  52.776 30.048 53.04 30.096 ;
     RECT  53.064 30.048 53.328 30.096 ;
     RECT  53.352 30.048 53.616 30.096 ;
     RECT  53.64 30.048 53.856 30.096 ;
     RECT  53.88 30.048 54.144 30.096 ;
     RECT  54.168 30.048 54.432 30.096 ;
     RECT  54.456 30.048 54.72 30.096 ;
     RECT  54.744 30.048 54.96 30.096 ;
     RECT  54.984 30.048 55.248 30.096 ;
     RECT  55.272 30.048 55.536 30.096 ;
     RECT  55.56 30.048 55.824 30.096 ;
     RECT  55.848 30.048 56.064 30.096 ;
     RECT  56.088 30.048 56.352 30.096 ;
     RECT  56.376 30.048 56.64 30.096 ;
     RECT  56.664 30.048 56.928 30.096 ;
     RECT  56.952 30.048 57.168 30.096 ;
     RECT  57.192 30.048 57.456 30.096 ;
     RECT  57.48 30.048 57.744 30.096 ;
     RECT  57.768 30.048 58.032 30.096 ;
     RECT  58.056 30.048 58.272 30.096 ;
     RECT  58.296 30.048 58.56 30.096 ;
     RECT  58.584 30.048 58.848 30.096 ;
     RECT  58.872 30.048 59.136 30.096 ;
     RECT  59.16 30.048 59.376 30.096 ;
     RECT  59.4 30.048 59.664 30.096 ;
     RECT  59.688 30.048 59.952 30.096 ;
     RECT  59.976 30.048 60.192 30.096 ;
     RECT  60.216 30.048 60.48 30.096 ;
     RECT  60.504 30.048 60.768 30.096 ;
     RECT  60.792 30.048 61.056 30.096 ;
     RECT  61.08 30.048 61.296 30.096 ;
     RECT  61.32 30.048 61.584 30.096 ;
     RECT  61.608 30.048 61.872 30.096 ;
     RECT  61.896 30.048 62.16 30.096 ;
     RECT  62.184 30.048 62.4 30.096 ;
     RECT  62.424 30.048 62.688 30.096 ;
     RECT  62.712 30.048 62.976 30.096 ;
     RECT  63 30.048 63.264 30.096 ;
     RECT  63.288 30.048 63.504 30.096 ;
     RECT  63.528 30.048 63.792 30.096 ;
     RECT  63.816 30.048 64.08 30.096 ;
     RECT  64.104 30.048 64.368 30.096 ;
     RECT  64.392 30.048 64.608 30.096 ;
     RECT  64.632 30.048 64.896 30.096 ;
     RECT  64.92 30.048 65.184 30.096 ;
     RECT  65.208 30.048 65.472 30.096 ;
     RECT  65.496 30.048 65.712 30.096 ;
     RECT  65.736 30.048 66 30.096 ;
     RECT  66.024 30.048 66.288 30.096 ;
     RECT  66.312 30.048 66.576 30.096 ;
     RECT  66.6 30.048 66.816 30.096 ;
     RECT  66.84 30.048 67.104 30.096 ;
     RECT  67.128 30.048 67.392 30.096 ;
     RECT  67.416 30.048 67.68 30.096 ;
     RECT  67.704 30.048 67.92 30.096 ;
     RECT  67.944 30.048 68.208 30.096 ;
     RECT  68.232 30.048 68.496 30.096 ;
     RECT  68.52 30.048 68.784 30.096 ;
     RECT  68.808 30.048 69.024 30.096 ;
     RECT  69.048 30.048 69.312 30.096 ;
     RECT  69.336 30.048 69.6 30.096 ;
     RECT  69.624 30.048 69.888 30.096 ;
     RECT  69.912 30.048 70.128 30.096 ;
     RECT  70.152 30.048 70.416 30.096 ;
     RECT  70.44 30.048 70.704 30.096 ;
     RECT  70.728 30.048 70.992 30.096 ;
     RECT  71.016 30.048 71.232 30.096 ;
     RECT  71.256 30.048 71.52 30.096 ;
     RECT  71.544 30.048 71.808 30.096 ;
     RECT  71.832 30.048 72.096 30.096 ;
     RECT  72.12 30.048 72.336 30.096 ;
     RECT  72.36 30.048 72.624 30.096 ;
     RECT  72.648 30.048 72.912 30.096 ;
     RECT  72.936 30.048 73.152 30.096 ;
     RECT  73.176 30.048 73.44 30.096 ;
     RECT  73.464 30.048 73.728 30.096 ;
     RECT  73.752 30.048 74.016 30.096 ;
     RECT  74.04 30.048 74.256 30.096 ;
     RECT  74.28 30.048 74.544 30.096 ;
     RECT  74.568 30.048 74.832 30.096 ;
     RECT  74.856 30.048 75.12 30.096 ;
     RECT  75.144 30.048 75.36 30.096 ;
     RECT  75.384 30.048 75.648 30.096 ;
     RECT  75.672 30.048 75.936 30.096 ;
     RECT  75.96 30.048 76.224 30.096 ;
     RECT  76.248 30.048 76.464 30.096 ;
     RECT  76.488 30.048 76.752 30.096 ;
     RECT  76.776 30.048 77.04 30.096 ;
     RECT  77.064 30.048 77.328 30.096 ;
     RECT  77.352 30.048 77.568 30.096 ;
     RECT  77.592 30.048 77.856 30.096 ;
     RECT  77.88 30.048 78.144 30.096 ;
     RECT  78.168 30.048 78.432 30.096 ;
     RECT  78.456 30.048 78.672 30.096 ;
     RECT  78.696 30.048 78.96 30.096 ;
     RECT  78.984 30.048 79.248 30.096 ;
     RECT  79.272 30.048 79.536 30.096 ;
     RECT  79.56 30.048 79.776 30.096 ;
     RECT  79.8 30.048 80.064 30.096 ;
     RECT  80.088 30.048 80.352 30.096 ;
     RECT  80.376 30.048 80.64 30.096 ;
     RECT  80.664 30.048 80.88 30.096 ;
     RECT  80.904 30.048 81.168 30.096 ;
     RECT  81.192 30.048 81.456 30.096 ;
     RECT  81.48 30.048 81.744 30.096 ;
     RECT  81.768 30.048 81.984 30.096 ;
     RECT  29.832 1.763 31.008 2.821 ;
     RECT  76.248 1.763 77.328 1.811 ;
     RECT  5.928 1.811 7.296 2.291 ;
     RECT  19.704 1.811 21.072 2.773 ;
     RECT  75.72 1.811 77.328 2.821 ;
     RECT  78.552 1.811 79.536 1.859 ;
     RECT  17.592 1.859 18.576 2.051 ;
     RECT  78.504 1.859 79.536 2.821 ;
     RECT  17.592 2.051 18.6 21.637 ;
     RECT  57.48 2.291 58.56 2.915 ;
     RECT  19.752 2.773 21.072 2.821 ;
     RECT  76.248 2.821 77.328 3.397 ;
     RECT  57.48 2.915 58.608 3.107 ;
     RECT  62.112 2.963 63.264 3.107 ;
     RECT  10.812 3.107 12.192 22.549 ;
     RECT  54.456 3.107 55.536 21.109 ;
     RECT  57.336 3.107 58.608 21.541 ;
     RECT  5.412 4.117 6.72 21.683 ;
     RECT  51.312 14.867 52.368 23.077 ;
     RECT  54.552 21.109 55.536 21.637 ;
     RECT  57.336 21.541 58.56 22.165 ;
     RECT  62.112 21.541 63.264 24.949 ;
     RECT  10.92 22.549 12.192 24.659 ;
     RECT  81.336 22.787 81.864 23.893 ;
     RECT  6.216 23.845 7.632 24.659 ;
     RECT  5.592 24.659 5.784 25.669 ;
     RECT  10.812 24.659 12.192 25.859 ;
     RECT  62.112 24.949 63.168 25.093 ;
     RECT  2.712 25.045 3.744 25.715 ;
     RECT  3.768 25.045 5.1 25.141 ;
     RECT  63.192 25.139 64.224 25.859 ;
     RECT  3.768 25.141 4.752 25.283 ;
     RECT  3.768 25.283 5.1 25.715 ;
     RECT  32.412 25.667 33.6 26.291 ;
     RECT  2.712 25.715 2.808 25.717 ;
     RECT  74.088 25.763 75.12 27.973 ;
     RECT  10.812 25.859 12.672 25.861 ;
     RECT  63.192 25.859 64.5 26.243 ;
     RECT  11.16 25.861 12.672 26.243 ;
     RECT  5.544 26.147 5.784 26.677 ;
     RECT  60.168 26.243 61.2 26.339 ;
     RECT  62.232 26.243 64.5 27.301 ;
     RECT  67.704 26.243 68.784 27.925 ;
     RECT  68.808 26.243 69.792 27.301 ;
     RECT  75.816 26.243 77.28 27.253 ;
     RECT  13.944 26.291 14.976 27.925 ;
     RECT  25.128 26.291 26.112 26.819 ;
     RECT  60.168 26.339 61.248 26.771 ;
     RECT  19.416 26.387 20.496 27.395 ;
     RECT  57.912 26.387 59.1 26.819 ;
     RECT  5.544 26.677 7.008 27.349 ;
     RECT  59.784 26.771 61.248 26.819 ;
     RECT  22.2 26.819 23.52 26.867 ;
     RECT  24.648 26.819 26.112 27.301 ;
     RECT  29.712 26.819 31.008 27.829 ;
     RECT  35.784 26.819 36.768 26.867 ;
     RECT  43.992 26.819 45.216 27.925 ;
     RECT  57.768 26.819 59.1 27.349 ;
     RECT  59.784 26.819 61.8 27.925 ;
     RECT  70.344 26.819 71.52 27.877 ;
     RECT  8.112 26.867 9.216 27.925 ;
     RECT  9.24 26.867 10.5 27.925 ;
     RECT  16.488 26.867 17.472 26.915 ;
     RECT  22.2 26.867 23.808 27.973 ;
     RECT  35.784 26.867 37.344 27.395 ;
     RECT  48.612 26.867 50.016 27.877 ;
     RECT  51.312 26.867 53.136 26.963 ;
     RECT  64.812 26.867 66 27.925 ;
     RECT  16.392 26.915 17.472 27.925 ;
     RECT  27.144 26.915 28.224 28.405 ;
     RECT  51.312 26.963 53.328 27.925 ;
     RECT  71.544 27.011 72.6 28.453 ;
     RECT  24.648 27.301 25.728 27.925 ;
     RECT  62.232 27.301 63.264 28.501 ;
     RECT  5.544 27.349 6.72 28.501 ;
     RECT  57.768 27.349 58.992 27.925 ;
     RECT  19.176 27.395 20.496 27.925 ;
     RECT  35.4 27.395 37.344 27.877 ;
     RECT  29.712 27.829 30.72 27.925 ;
     RECT  35.4 27.877 36.768 28.453 ;
     RECT  48.744 27.877 50.016 27.925 ;
     RECT  11.16 27.925 12.24 28.453 ;
     RECT  19.176 27.925 20.256 29.077 ;
     RECT  48.936 27.925 50.016 27.973 ;
     RECT  51.432 27.925 52.752 27.973 ;
     RECT  59.784 27.925 60.768 28.501 ;
     RECT  64.92 27.925 66 27.973 ;
     RECT  22.728 27.973 23.808 28.453 ;
     RECT  51.672 27.973 52.752 28.933 ;
     RECT  3.528 29.029 4.512 30 ;
     RECT  3.576 30 4.464 30.096 ;
  END
END ot_s81_sstn_base566
END LIBRARY
